VERSION 5.8 ;
BUSBITCHARS "[]" ;
DIVIDERCHAR "/" ;
UNITS
    DATABASE MICRONS 1000 ;
END UNITS

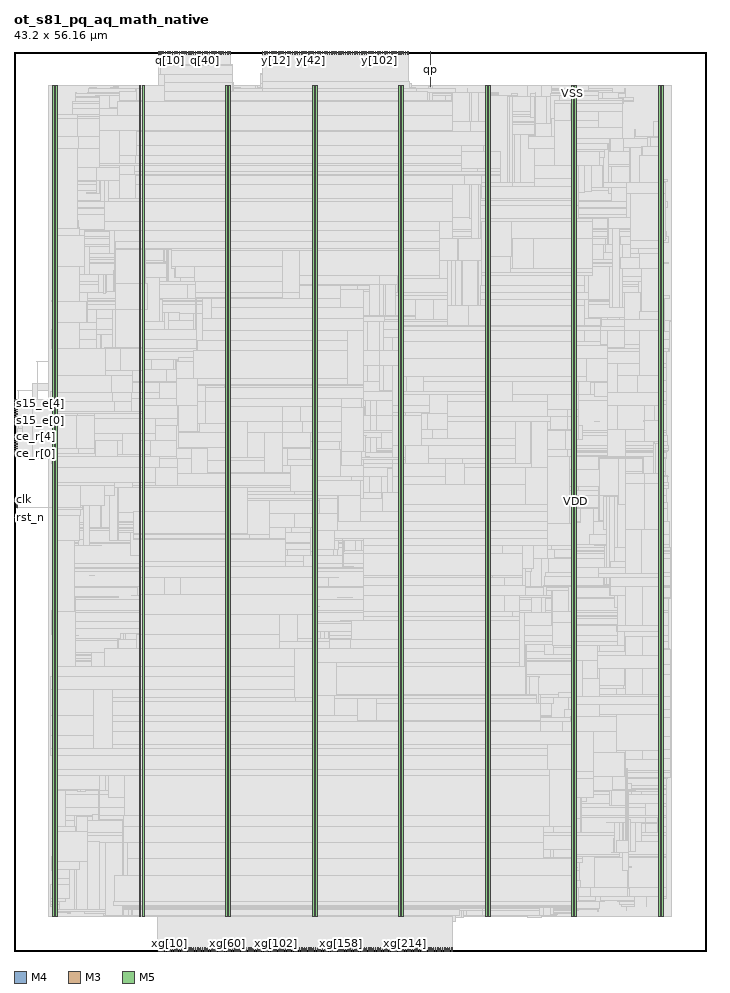
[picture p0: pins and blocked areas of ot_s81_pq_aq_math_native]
MACRO ot_s81_pq_aq_math_native
  FOREIGN ot_s81_pq_aq_math_native 0 0 ;
  CLASS BLOCK ;
  SIZE 43.2 BY 56.16 ;
  PIN ce_r[0]
    DIRECTION INPUT ;
    USE SIGNAL ;
    PORT
      LAYER M4 ;
        RECT  0 31.056 0.192 31.08 ;
    END
  END ce_r[0]
  PIN ce_r[1]
    DIRECTION INPUT ;
    USE SIGNAL ;
    PORT
      LAYER M4 ;
        RECT  0 31.2 0.192 31.224 ;
    END
  END ce_r[1]
  PIN ce_r[2]
    DIRECTION INPUT ;
    USE SIGNAL ;
    PORT
      LAYER M4 ;
        RECT  0 31.344 0.192 31.368 ;
    END
  END ce_r[2]
  PIN ce_r[3]
    DIRECTION INPUT ;
    USE SIGNAL ;
    PORT
      LAYER M4 ;
        RECT  0 31.488 0.192 31.512 ;
    END
  END ce_r[3]
  PIN ce_r[4]
    DIRECTION INPUT ;
    USE SIGNAL ;
    PORT
      LAYER M4 ;
        RECT  0 31.632 0.192 31.656 ;
    END
  END ce_r[4]
  PIN ce_r[5]
    DIRECTION INPUT ;
    USE SIGNAL ;
    PORT
      LAYER M4 ;
        RECT  0 31.776 0.192 31.8 ;
    END
  END ce_r[5]
  PIN ce_r[6]
    DIRECTION INPUT ;
    USE SIGNAL ;
    PORT
      LAYER M4 ;
        RECT  0 31.92 0.192 31.944 ;
    END
  END ce_r[6]
  PIN ce_r[7]
    DIRECTION INPUT ;
    USE SIGNAL ;
    PORT
      LAYER M4 ;
        RECT  0 32.064 0.192 32.088 ;
    END
  END ce_r[7]
  PIN ce_r[8]
    DIRECTION INPUT ;
    USE SIGNAL ;
    PORT
      LAYER M4 ;
        RECT  0 32.208 0.192 32.232 ;
    END
  END ce_r[8]
  PIN clk
    DIRECTION INPUT ;
    USE SIGNAL ;
    PORT
      LAYER M4 ;
        RECT  0 28.032 0.192 28.056 ;
    END
    PORT
      LAYER M4 ;
        RECT  0.156 28.032 0.181 28.056 ;
    END
    PORT
      LAYER M4 ;
        RECT  0.181 27.648 0.227 28.056 ;
    END
  END clk
  PIN q[0]
    DIRECTION OUTPUT ;
    USE SIGNAL ;
    PORT
      LAYER M3 ;
        RECT  9 56.016 9.018 56.16 ;
    END
  END q[0]
  PIN q[10]
    DIRECTION OUTPUT ;
    USE SIGNAL ;
    PORT
      LAYER M3 ;
        RECT  9.72 56.016 9.738 56.16 ;
    END
  END q[10]
  PIN q[11]
    DIRECTION OUTPUT ;
    USE SIGNAL ;
    PORT
      LAYER M5 ;
        RECT  9.744 55.968 9.768 56.16 ;
    END
  END q[11]
  PIN q[12]
    DIRECTION OUTPUT ;
    USE SIGNAL ;
    PORT
      LAYER M3 ;
        RECT  9.864 56.016 9.882 56.16 ;
    END
  END q[12]
  PIN q[13]
    DIRECTION OUTPUT ;
    USE SIGNAL ;
    PORT
      LAYER M5 ;
        RECT  9.888 55.968 9.912 56.16 ;
    END
  END q[13]
  PIN q[14]
    DIRECTION OUTPUT ;
    USE SIGNAL ;
    PORT
      LAYER M3 ;
        RECT  10.008 56.016 10.026 56.16 ;
    END
  END q[14]
  PIN q[15]
    DIRECTION OUTPUT ;
    USE SIGNAL ;
    PORT
      LAYER M5 ;
        RECT  10.032 55.968 10.056 56.16 ;
    END
  END q[15]
  PIN q[16]
    DIRECTION OUTPUT ;
    USE SIGNAL ;
    PORT
      LAYER M3 ;
        RECT  10.152 56.016 10.17 56.16 ;
    END
  END q[16]
  PIN q[17]
    DIRECTION OUTPUT ;
    USE SIGNAL ;
    PORT
      LAYER M5 ;
        RECT  10.176 55.968 10.2 56.16 ;
    END
  END q[17]
  PIN q[18]
    DIRECTION OUTPUT ;
    USE SIGNAL ;
    PORT
      LAYER M3 ;
        RECT  10.296 56.016 10.314 56.16 ;
    END
  END q[18]
  PIN q[19]
    DIRECTION OUTPUT ;
    USE SIGNAL ;
    PORT
      LAYER M5 ;
        RECT  10.32 55.968 10.344 56.16 ;
    END
  END q[19]
  PIN q[1]
    DIRECTION OUTPUT ;
    USE SIGNAL ;
    PORT
      LAYER M5 ;
        RECT  9.024 55.968 9.048 56.16 ;
    END
  END q[1]
  PIN q[20]
    DIRECTION OUTPUT ;
    USE SIGNAL ;
    PORT
      LAYER M3 ;
        RECT  10.44 56.016 10.458 56.16 ;
    END
  END q[20]
  PIN q[21]
    DIRECTION OUTPUT ;
    USE SIGNAL ;
    PORT
      LAYER M5 ;
        RECT  10.464 55.968 10.488 56.16 ;
    END
  END q[21]
  PIN q[22]
    DIRECTION OUTPUT ;
    USE SIGNAL ;
    PORT
      LAYER M3 ;
        RECT  10.584 56.016 10.602 56.16 ;
    END
  END q[22]
  PIN q[23]
    DIRECTION OUTPUT ;
    USE SIGNAL ;
    PORT
      LAYER M5 ;
        RECT  10.608 55.968 10.632 56.16 ;
    END
  END q[23]
  PIN q[24]
    DIRECTION OUTPUT ;
    USE SIGNAL ;
    PORT
      LAYER M3 ;
        RECT  10.728 56.016 10.746 56.16 ;
    END
  END q[24]
  PIN q[25]
    DIRECTION OUTPUT ;
    USE SIGNAL ;
    PORT
      LAYER M5 ;
        RECT  10.752 55.968 10.776 56.16 ;
    END
  END q[25]
  PIN q[26]
    DIRECTION OUTPUT ;
    USE SIGNAL ;
    PORT
      LAYER M3 ;
        RECT  10.872 56.016 10.89 56.16 ;
    END
  END q[26]
  PIN q[27]
    DIRECTION OUTPUT ;
    USE SIGNAL ;
    PORT
      LAYER M5 ;
        RECT  10.896 55.968 10.92 56.16 ;
    END
  END q[27]
  PIN q[28]
    DIRECTION OUTPUT ;
    USE SIGNAL ;
    PORT
      LAYER M3 ;
        RECT  11.016 56.016 11.034 56.16 ;
    END
  END q[28]
  PIN q[29]
    DIRECTION OUTPUT ;
    USE SIGNAL ;
    PORT
      LAYER M5 ;
        RECT  11.04 55.968 11.064 56.16 ;
    END
  END q[29]
  PIN q[2]
    DIRECTION OUTPUT ;
    USE SIGNAL ;
    PORT
      LAYER M3 ;
        RECT  9.144 56.016 9.162 56.16 ;
    END
  END q[2]
  PIN q[30]
    DIRECTION OUTPUT ;
    USE SIGNAL ;
    PORT
      LAYER M3 ;
        RECT  11.16 56.016 11.178 56.16 ;
    END
  END q[30]
  PIN q[31]
    DIRECTION OUTPUT ;
    USE SIGNAL ;
    PORT
      LAYER M5 ;
        RECT  11.184 55.968 11.208 56.16 ;
    END
  END q[31]
  PIN q[32]
    DIRECTION OUTPUT ;
    USE SIGNAL ;
    PORT
      LAYER M3 ;
        RECT  11.304 56.016 11.322 56.16 ;
    END
  END q[32]
  PIN q[33]
    DIRECTION OUTPUT ;
    USE SIGNAL ;
    PORT
      LAYER M5 ;
        RECT  11.328 55.968 11.352 56.16 ;
    END
  END q[33]
  PIN q[34]
    DIRECTION OUTPUT ;
    USE SIGNAL ;
    PORT
      LAYER M3 ;
        RECT  11.448 56.016 11.466 56.16 ;
    END
  END q[34]
  PIN q[35]
    DIRECTION OUTPUT ;
    USE SIGNAL ;
    PORT
      LAYER M5 ;
        RECT  11.472 55.968 11.496 56.16 ;
    END
  END q[35]
  PIN q[36]
    DIRECTION OUTPUT ;
    USE SIGNAL ;
    PORT
      LAYER M3 ;
        RECT  11.592 56.016 11.61 56.16 ;
    END
  END q[36]
  PIN q[37]
    DIRECTION OUTPUT ;
    USE SIGNAL ;
    PORT
      LAYER M5 ;
        RECT  11.616 55.968 11.64 56.16 ;
    END
  END q[37]
  PIN q[38]
    DIRECTION OUTPUT ;
    USE SIGNAL ;
    PORT
      LAYER M3 ;
        RECT  11.736 56.016 11.754 56.16 ;
    END
  END q[38]
  PIN q[39]
    DIRECTION OUTPUT ;
    USE SIGNAL ;
    PORT
      LAYER M5 ;
        RECT  11.76 55.968 11.784 56.16 ;
    END
  END q[39]
  PIN q[3]
    DIRECTION OUTPUT ;
    USE SIGNAL ;
    PORT
      LAYER M5 ;
        RECT  9.168 55.968 9.192 56.16 ;
    END
  END q[3]
  PIN q[40]
    DIRECTION OUTPUT ;
    USE SIGNAL ;
    PORT
      LAYER M3 ;
        RECT  11.88 56.016 11.898 56.16 ;
    END
  END q[40]
  PIN q[41]
    DIRECTION OUTPUT ;
    USE SIGNAL ;
    PORT
      LAYER M5 ;
        RECT  11.904 55.968 11.928 56.16 ;
    END
  END q[41]
  PIN q[42]
    DIRECTION OUTPUT ;
    USE SIGNAL ;
    PORT
      LAYER M3 ;
        RECT  12.024 56.016 12.042 56.16 ;
    END
  END q[42]
  PIN q[43]
    DIRECTION OUTPUT ;
    USE SIGNAL ;
    PORT
      LAYER M5 ;
        RECT  12.048 55.968 12.072 56.16 ;
    END
  END q[43]
  PIN q[44]
    DIRECTION OUTPUT ;
    USE SIGNAL ;
    PORT
      LAYER M3 ;
        RECT  12.168 56.016 12.186 56.16 ;
    END
  END q[44]
  PIN q[45]
    DIRECTION OUTPUT ;
    USE SIGNAL ;
    PORT
      LAYER M5 ;
        RECT  12.192 55.968 12.216 56.16 ;
    END
  END q[45]
  PIN q[46]
    DIRECTION OUTPUT ;
    USE SIGNAL ;
    PORT
      LAYER M3 ;
        RECT  12.312 56.016 12.33 56.16 ;
    END
  END q[46]
  PIN q[47]
    DIRECTION OUTPUT ;
    USE SIGNAL ;
    PORT
      LAYER M5 ;
        RECT  12.336 55.968 12.36 56.16 ;
    END
  END q[47]
  PIN q[48]
    DIRECTION OUTPUT ;
    USE SIGNAL ;
    PORT
      LAYER M3 ;
        RECT  12.456 56.016 12.474 56.16 ;
    END
  END q[48]
  PIN q[49]
    DIRECTION OUTPUT ;
    USE SIGNAL ;
    PORT
      LAYER M5 ;
        RECT  12.48 55.968 12.504 56.16 ;
    END
  END q[49]
  PIN q[4]
    DIRECTION OUTPUT ;
    USE SIGNAL ;
    PORT
      LAYER M3 ;
        RECT  9.288 56.016 9.306 56.16 ;
    END
  END q[4]
  PIN q[50]
    DIRECTION OUTPUT ;
    USE SIGNAL ;
    PORT
      LAYER M3 ;
        RECT  12.6 56.016 12.618 56.16 ;
    END
  END q[50]
  PIN q[51]
    DIRECTION OUTPUT ;
    USE SIGNAL ;
    PORT
      LAYER M5 ;
        RECT  12.624 55.968 12.648 56.16 ;
    END
  END q[51]
  PIN q[52]
    DIRECTION OUTPUT ;
    USE SIGNAL ;
    PORT
      LAYER M3 ;
        RECT  12.744 56.016 12.762 56.16 ;
    END
  END q[52]
  PIN q[53]
    DIRECTION OUTPUT ;
    USE SIGNAL ;
    PORT
      LAYER M5 ;
        RECT  12.768 55.968 12.792 56.16 ;
    END
  END q[53]
  PIN q[54]
    DIRECTION OUTPUT ;
    USE SIGNAL ;
    PORT
      LAYER M3 ;
        RECT  12.888 56.016 12.906 56.16 ;
    END
  END q[54]
  PIN q[55]
    DIRECTION OUTPUT ;
    USE SIGNAL ;
    PORT
      LAYER M5 ;
        RECT  12.912 55.968 12.936 56.16 ;
    END
  END q[55]
  PIN q[56]
    DIRECTION OUTPUT ;
    USE SIGNAL ;
    PORT
      LAYER M3 ;
        RECT  13.032 56.016 13.05 56.16 ;
    END
  END q[56]
  PIN q[57]
    DIRECTION OUTPUT ;
    USE SIGNAL ;
    PORT
      LAYER M5 ;
        RECT  13.056 55.968 13.08 56.16 ;
    END
  END q[57]
  PIN q[58]
    DIRECTION OUTPUT ;
    USE SIGNAL ;
    PORT
      LAYER M3 ;
        RECT  13.176 56.016 13.194 56.16 ;
    END
  END q[58]
  PIN q[59]
    DIRECTION OUTPUT ;
    USE SIGNAL ;
    PORT
      LAYER M5 ;
        RECT  13.2 55.968 13.224 56.16 ;
    END
  END q[59]
  PIN q[5]
    DIRECTION OUTPUT ;
    USE SIGNAL ;
    PORT
      LAYER M5 ;
        RECT  9.312 55.968 9.336 56.16 ;
    END
  END q[5]
  PIN q[60]
    DIRECTION OUTPUT ;
    USE SIGNAL ;
    PORT
      LAYER M3 ;
        RECT  13.32 56.016 13.338 56.16 ;
    END
  END q[60]
  PIN q[61]
    DIRECTION OUTPUT ;
    USE SIGNAL ;
    PORT
      LAYER M5 ;
        RECT  13.344 55.968 13.368 56.16 ;
    END
  END q[61]
  PIN q[62]
    DIRECTION OUTPUT ;
    USE SIGNAL ;
    PORT
      LAYER M3 ;
        RECT  13.464 56.016 13.482 56.16 ;
    END
  END q[62]
  PIN q[63]
    DIRECTION OUTPUT ;
    USE SIGNAL ;
    PORT
      LAYER M5 ;
        RECT  13.488 55.968 13.512 56.16 ;
    END
  END q[63]
  PIN q[6]
    DIRECTION OUTPUT ;
    USE SIGNAL ;
    PORT
      LAYER M3 ;
        RECT  9.432 56.016 9.45 56.16 ;
    END
  END q[6]
  PIN q[7]
    DIRECTION OUTPUT ;
    USE SIGNAL ;
    PORT
      LAYER M5 ;
        RECT  9.456 55.968 9.48 56.16 ;
    END
  END q[7]
  PIN q[8]
    DIRECTION OUTPUT ;
    USE SIGNAL ;
    PORT
      LAYER M3 ;
        RECT  9.576 56.016 9.594 56.16 ;
    END
  END q[8]
  PIN q[9]
    DIRECTION OUTPUT ;
    USE SIGNAL ;
    PORT
      LAYER M5 ;
        RECT  9.6 55.968 9.624 56.16 ;
    END
  END q[9]
  PIN qp
    DIRECTION OUTPUT ;
    USE SIGNAL ;
    PORT
      LAYER M3 ;
        RECT  25.992 56.016 26.01 56.16 ;
    END
    PORT
      LAYER M3 ;
        RECT  25.992 53.969 26.01 56.028 ;
    END
  END qp
  PIN rst_n
    DIRECTION INPUT ;
    USE SIGNAL ;
    PORT
      LAYER M4 ;
        RECT  0 27.024 0.192 27.048 ;
    END
  END rst_n
  PIN s15_e[0]
    DIRECTION INPUT ;
    USE SIGNAL ;
    PORT
      LAYER M4 ;
        RECT  0 33.072 0.192 33.096 ;
    END
  END s15_e[0]
  PIN s15_e[1]
    DIRECTION INPUT ;
    USE SIGNAL ;
    PORT
      LAYER M4 ;
        RECT  0 33.216 0.192 33.24 ;
    END
  END s15_e[1]
  PIN s15_e[2]
    DIRECTION INPUT ;
    USE SIGNAL ;
    PORT
      LAYER M4 ;
        RECT  0 33.36 0.192 33.384 ;
    END
  END s15_e[2]
  PIN s15_e[3]
    DIRECTION INPUT ;
    USE SIGNAL ;
    PORT
      LAYER M4 ;
        RECT  0 33.504 0.192 33.528 ;
    END
  END s15_e[3]
  PIN s15_e[4]
    DIRECTION INPUT ;
    USE SIGNAL ;
    PORT
      LAYER M4 ;
        RECT  0 33.648 0.192 33.672 ;
    END
  END s15_e[4]
  PIN s15_e[5]
    DIRECTION INPUT ;
    USE SIGNAL ;
    PORT
      LAYER M4 ;
        RECT  0 33.792 0.192 33.816 ;
    END
  END s15_e[5]
  PIN s15_e[6]
    DIRECTION INPUT ;
    USE SIGNAL ;
    PORT
      LAYER M4 ;
        RECT  0 33.936 0.192 33.96 ;
    END
  END s15_e[6]
  PIN s15_e[7]
    DIRECTION INPUT ;
    USE SIGNAL ;
    PORT
      LAYER M4 ;
        RECT  0 34.08 0.192 34.104 ;
    END
  END s15_e[7]
  PIN s15_e[8]
    DIRECTION INPUT ;
    USE SIGNAL ;
    PORT
      LAYER M4 ;
        RECT  0 34.224 0.192 34.248 ;
    END
  END s15_e[8]
  PIN s15_e[9]
    DIRECTION INPUT ;
    USE SIGNAL ;
    PORT
      LAYER M4 ;
        RECT  0 34.368 0.192 34.392 ;
    END
  END s15_e[9]
  PIN xg[0]
    DIRECTION INPUT ;
    USE SIGNAL ;
    PORT
      LAYER M3 ;
        RECT  9 0 9.018 0.144 ;
    END
  END xg[0]
  PIN xg[100]
    DIRECTION INPUT ;
    USE SIGNAL ;
    PORT
      LAYER M3 ;
        RECT  16.2 0 16.218 0.144 ;
    END
  END xg[100]
  PIN xg[101]
    DIRECTION INPUT ;
    USE SIGNAL ;
    PORT
      LAYER M5 ;
        RECT  16.224 0 16.248 0.192 ;
    END
  END xg[101]
  PIN xg[102]
    DIRECTION INPUT ;
    USE SIGNAL ;
    PORT
      LAYER M3 ;
        RECT  16.344 0 16.362 0.144 ;
    END
  END xg[102]
  PIN xg[103]
    DIRECTION INPUT ;
    USE SIGNAL ;
    PORT
      LAYER M5 ;
        RECT  16.368 0 16.392 0.192 ;
    END
  END xg[103]
  PIN xg[104]
    DIRECTION INPUT ;
    USE SIGNAL ;
    PORT
      LAYER M3 ;
        RECT  16.488 0 16.506 0.144 ;
    END
  END xg[104]
  PIN xg[105]
    DIRECTION INPUT ;
    USE SIGNAL ;
    PORT
      LAYER M5 ;
        RECT  16.512 0 16.536 0.192 ;
    END
  END xg[105]
  PIN xg[106]
    DIRECTION INPUT ;
    USE SIGNAL ;
    PORT
      LAYER M3 ;
        RECT  16.632 0 16.65 0.144 ;
    END
  END xg[106]
  PIN xg[107]
    DIRECTION INPUT ;
    USE SIGNAL ;
    PORT
      LAYER M5 ;
        RECT  16.656 0 16.68 0.192 ;
    END
  END xg[107]
  PIN xg[108]
    DIRECTION INPUT ;
    USE SIGNAL ;
    PORT
      LAYER M3 ;
        RECT  16.776 0 16.794 0.144 ;
    END
  END xg[108]
  PIN xg[109]
    DIRECTION INPUT ;
    USE SIGNAL ;
    PORT
      LAYER M5 ;
        RECT  16.8 0 16.824 0.192 ;
    END
  END xg[109]
  PIN xg[10]
    DIRECTION INPUT ;
    USE SIGNAL ;
    PORT
      LAYER M3 ;
        RECT  9.72 0 9.738 0.144 ;
    END
  END xg[10]
  PIN xg[110]
    DIRECTION INPUT ;
    USE SIGNAL ;
    PORT
      LAYER M3 ;
        RECT  16.92 0 16.938 0.144 ;
    END
  END xg[110]
  PIN xg[111]
    DIRECTION INPUT ;
    USE SIGNAL ;
    PORT
      LAYER M5 ;
        RECT  16.944 0 16.968 0.192 ;
    END
  END xg[111]
  PIN xg[112]
    DIRECTION INPUT ;
    USE SIGNAL ;
    PORT
      LAYER M3 ;
        RECT  17.064 0 17.082 0.144 ;
    END
  END xg[112]
  PIN xg[113]
    DIRECTION INPUT ;
    USE SIGNAL ;
    PORT
      LAYER M5 ;
        RECT  17.088 0 17.112 0.192 ;
    END
  END xg[113]
  PIN xg[114]
    DIRECTION INPUT ;
    USE SIGNAL ;
    PORT
      LAYER M3 ;
        RECT  17.208 0 17.226 0.144 ;
    END
  END xg[114]
  PIN xg[115]
    DIRECTION INPUT ;
    USE SIGNAL ;
    PORT
      LAYER M5 ;
        RECT  17.232 0 17.256 0.192 ;
    END
  END xg[115]
  PIN xg[116]
    DIRECTION INPUT ;
    USE SIGNAL ;
    PORT
      LAYER M3 ;
        RECT  17.352 0 17.37 0.144 ;
    END
  END xg[116]
  PIN xg[117]
    DIRECTION INPUT ;
    USE SIGNAL ;
    PORT
      LAYER M5 ;
        RECT  17.376 0 17.4 0.192 ;
    END
  END xg[117]
  PIN xg[118]
    DIRECTION INPUT ;
    USE SIGNAL ;
    PORT
      LAYER M3 ;
        RECT  17.496 0 17.514 0.144 ;
    END
  END xg[118]
  PIN xg[119]
    DIRECTION INPUT ;
    USE SIGNAL ;
    PORT
      LAYER M5 ;
        RECT  17.52 0 17.544 0.192 ;
    END
  END xg[119]
  PIN xg[11]
    DIRECTION INPUT ;
    USE SIGNAL ;
    PORT
      LAYER M5 ;
        RECT  9.744 0 9.768 0.192 ;
    END
  END xg[11]
  PIN xg[120]
    DIRECTION INPUT ;
    USE SIGNAL ;
    PORT
      LAYER M3 ;
        RECT  17.64 0 17.658 0.144 ;
    END
  END xg[120]
  PIN xg[121]
    DIRECTION INPUT ;
    USE SIGNAL ;
    PORT
      LAYER M5 ;
        RECT  17.664 0 17.688 0.192 ;
    END
  END xg[121]
  PIN xg[122]
    DIRECTION INPUT ;
    USE SIGNAL ;
    PORT
      LAYER M3 ;
        RECT  17.784 0 17.802 0.144 ;
    END
  END xg[122]
  PIN xg[123]
    DIRECTION INPUT ;
    USE SIGNAL ;
    PORT
      LAYER M5 ;
        RECT  17.808 0 17.832 0.192 ;
    END
  END xg[123]
  PIN xg[124]
    DIRECTION INPUT ;
    USE SIGNAL ;
    PORT
      LAYER M3 ;
        RECT  17.928 0 17.946 0.144 ;
    END
  END xg[124]
  PIN xg[125]
    DIRECTION INPUT ;
    USE SIGNAL ;
    PORT
      LAYER M5 ;
        RECT  17.952 0 17.976 0.192 ;
    END
  END xg[125]
  PIN xg[126]
    DIRECTION INPUT ;
    USE SIGNAL ;
    PORT
      LAYER M3 ;
        RECT  18.072 0 18.09 0.144 ;
    END
  END xg[126]
  PIN xg[127]
    DIRECTION INPUT ;
    USE SIGNAL ;
    PORT
      LAYER M5 ;
        RECT  18.096 0 18.12 0.192 ;
    END
  END xg[127]
  PIN xg[128]
    DIRECTION INPUT ;
    USE SIGNAL ;
    PORT
      LAYER M3 ;
        RECT  18.216 0 18.234 0.144 ;
    END
  END xg[128]
  PIN xg[129]
    DIRECTION INPUT ;
    USE SIGNAL ;
    PORT
      LAYER M5 ;
        RECT  18.24 0 18.264 0.192 ;
    END
  END xg[129]
  PIN xg[12]
    DIRECTION INPUT ;
    USE SIGNAL ;
    PORT
      LAYER M3 ;
        RECT  9.864 0 9.882 0.144 ;
    END
  END xg[12]
  PIN xg[130]
    DIRECTION INPUT ;
    USE SIGNAL ;
    PORT
      LAYER M3 ;
        RECT  18.36 0 18.378 0.144 ;
    END
  END xg[130]
  PIN xg[131]
    DIRECTION INPUT ;
    USE SIGNAL ;
    PORT
      LAYER M5 ;
        RECT  18.384 0 18.408 0.192 ;
    END
  END xg[131]
  PIN xg[132]
    DIRECTION INPUT ;
    USE SIGNAL ;
    PORT
      LAYER M3 ;
        RECT  18.504 0 18.522 0.144 ;
    END
  END xg[132]
  PIN xg[133]
    DIRECTION INPUT ;
    USE SIGNAL ;
    PORT
      LAYER M5 ;
        RECT  18.528 0 18.552 0.192 ;
    END
  END xg[133]
  PIN xg[134]
    DIRECTION INPUT ;
    USE SIGNAL ;
    PORT
      LAYER M3 ;
        RECT  18.648 0 18.666 0.144 ;
    END
  END xg[134]
  PIN xg[135]
    DIRECTION INPUT ;
    USE SIGNAL ;
    PORT
      LAYER M5 ;
        RECT  18.672 0 18.696 0.192 ;
    END
  END xg[135]
  PIN xg[136]
    DIRECTION INPUT ;
    USE SIGNAL ;
    PORT
      LAYER M3 ;
        RECT  18.792 0 18.81 0.144 ;
    END
  END xg[136]
  PIN xg[137]
    DIRECTION INPUT ;
    USE SIGNAL ;
    PORT
      LAYER M5 ;
        RECT  18.816 0 18.84 0.192 ;
    END
  END xg[137]
  PIN xg[138]
    DIRECTION INPUT ;
    USE SIGNAL ;
    PORT
      LAYER M3 ;
        RECT  18.936 0 18.954 0.144 ;
    END
  END xg[138]
  PIN xg[139]
    DIRECTION INPUT ;
    USE SIGNAL ;
    PORT
      LAYER M5 ;
        RECT  18.96 0 18.984 0.192 ;
    END
  END xg[139]
  PIN xg[13]
    DIRECTION INPUT ;
    USE SIGNAL ;
    PORT
      LAYER M5 ;
        RECT  9.888 0 9.912 0.192 ;
    END
  END xg[13]
  PIN xg[140]
    DIRECTION INPUT ;
    USE SIGNAL ;
    PORT
      LAYER M3 ;
        RECT  19.08 0 19.098 0.144 ;
    END
  END xg[140]
  PIN xg[141]
    DIRECTION INPUT ;
    USE SIGNAL ;
    PORT
      LAYER M5 ;
        RECT  19.104 0 19.128 0.192 ;
    END
  END xg[141]
  PIN xg[142]
    DIRECTION INPUT ;
    USE SIGNAL ;
    PORT
      LAYER M3 ;
        RECT  19.224 0 19.242 0.144 ;
    END
  END xg[142]
  PIN xg[143]
    DIRECTION INPUT ;
    USE SIGNAL ;
    PORT
      LAYER M5 ;
        RECT  19.248 0 19.272 0.192 ;
    END
  END xg[143]
  PIN xg[144]
    DIRECTION INPUT ;
    USE SIGNAL ;
    PORT
      LAYER M3 ;
        RECT  19.368 0 19.386 0.144 ;
    END
  END xg[144]
  PIN xg[145]
    DIRECTION INPUT ;
    USE SIGNAL ;
    PORT
      LAYER M5 ;
        RECT  19.392 0 19.416 0.192 ;
    END
  END xg[145]
  PIN xg[146]
    DIRECTION INPUT ;
    USE SIGNAL ;
    PORT
      LAYER M3 ;
        RECT  19.512 0 19.53 0.144 ;
    END
  END xg[146]
  PIN xg[147]
    DIRECTION INPUT ;
    USE SIGNAL ;
    PORT
      LAYER M5 ;
        RECT  19.536 0 19.56 0.192 ;
    END
  END xg[147]
  PIN xg[148]
    DIRECTION INPUT ;
    USE SIGNAL ;
    PORT
      LAYER M3 ;
        RECT  19.656 0 19.674 0.144 ;
    END
  END xg[148]
  PIN xg[149]
    DIRECTION INPUT ;
    USE SIGNAL ;
    PORT
      LAYER M5 ;
        RECT  19.68 0 19.704 0.192 ;
    END
  END xg[149]
  PIN xg[14]
    DIRECTION INPUT ;
    USE SIGNAL ;
    PORT
      LAYER M3 ;
        RECT  10.008 0 10.026 0.144 ;
    END
  END xg[14]
  PIN xg[150]
    DIRECTION INPUT ;
    USE SIGNAL ;
    PORT
      LAYER M3 ;
        RECT  19.8 0 19.818 0.144 ;
    END
  END xg[150]
  PIN xg[151]
    DIRECTION INPUT ;
    USE SIGNAL ;
    PORT
      LAYER M5 ;
        RECT  19.824 0 19.848 0.192 ;
    END
  END xg[151]
  PIN xg[152]
    DIRECTION INPUT ;
    USE SIGNAL ;
    PORT
      LAYER M3 ;
        RECT  19.944 0 19.962 0.144 ;
    END
  END xg[152]
  PIN xg[153]
    DIRECTION INPUT ;
    USE SIGNAL ;
    PORT
      LAYER M5 ;
        RECT  19.968 0 19.992 0.192 ;
    END
  END xg[153]
  PIN xg[154]
    DIRECTION INPUT ;
    USE SIGNAL ;
    PORT
      LAYER M3 ;
        RECT  20.088 0 20.106 0.144 ;
    END
  END xg[154]
  PIN xg[155]
    DIRECTION INPUT ;
    USE SIGNAL ;
    PORT
      LAYER M5 ;
        RECT  20.112 0 20.136 0.192 ;
    END
  END xg[155]
  PIN xg[156]
    DIRECTION INPUT ;
    USE SIGNAL ;
    PORT
      LAYER M3 ;
        RECT  20.232 0 20.25 0.144 ;
    END
  END xg[156]
  PIN xg[157]
    DIRECTION INPUT ;
    USE SIGNAL ;
    PORT
      LAYER M5 ;
        RECT  20.256 0 20.28 0.192 ;
    END
  END xg[157]
  PIN xg[158]
    DIRECTION INPUT ;
    USE SIGNAL ;
    PORT
      LAYER M3 ;
        RECT  20.376 0 20.394 0.144 ;
    END
  END xg[158]
  PIN xg[159]
    DIRECTION INPUT ;
    USE SIGNAL ;
    PORT
      LAYER M5 ;
        RECT  20.4 0 20.424 0.192 ;
    END
  END xg[159]
  PIN xg[15]
    DIRECTION INPUT ;
    USE SIGNAL ;
    PORT
      LAYER M5 ;
        RECT  10.032 0 10.056 0.192 ;
    END
  END xg[15]
  PIN xg[160]
    DIRECTION INPUT ;
    USE SIGNAL ;
    PORT
      LAYER M3 ;
        RECT  20.52 0 20.538 0.144 ;
    END
  END xg[160]
  PIN xg[161]
    DIRECTION INPUT ;
    USE SIGNAL ;
    PORT
      LAYER M5 ;
        RECT  20.544 0 20.568 0.192 ;
    END
  END xg[161]
  PIN xg[162]
    DIRECTION INPUT ;
    USE SIGNAL ;
    PORT
      LAYER M3 ;
        RECT  20.664 0 20.682 0.144 ;
    END
  END xg[162]
  PIN xg[163]
    DIRECTION INPUT ;
    USE SIGNAL ;
    PORT
      LAYER M5 ;
        RECT  20.688 0 20.712 0.192 ;
    END
  END xg[163]
  PIN xg[164]
    DIRECTION INPUT ;
    USE SIGNAL ;
    PORT
      LAYER M3 ;
        RECT  20.808 0 20.826 0.144 ;
    END
  END xg[164]
  PIN xg[165]
    DIRECTION INPUT ;
    USE SIGNAL ;
    PORT
      LAYER M5 ;
        RECT  20.832 0 20.856 0.192 ;
    END
  END xg[165]
  PIN xg[166]
    DIRECTION INPUT ;
    USE SIGNAL ;
    PORT
      LAYER M3 ;
        RECT  20.952 0 20.97 0.144 ;
    END
  END xg[166]
  PIN xg[167]
    DIRECTION INPUT ;
    USE SIGNAL ;
    PORT
      LAYER M5 ;
        RECT  20.976 0 21 0.192 ;
    END
  END xg[167]
  PIN xg[168]
    DIRECTION INPUT ;
    USE SIGNAL ;
    PORT
      LAYER M3 ;
        RECT  21.096 0 21.114 0.144 ;
    END
  END xg[168]
  PIN xg[169]
    DIRECTION INPUT ;
    USE SIGNAL ;
    PORT
      LAYER M5 ;
        RECT  21.12 0 21.144 0.192 ;
    END
  END xg[169]
  PIN xg[16]
    DIRECTION INPUT ;
    USE SIGNAL ;
    PORT
      LAYER M3 ;
        RECT  10.152 0 10.17 0.144 ;
    END
  END xg[16]
  PIN xg[170]
    DIRECTION INPUT ;
    USE SIGNAL ;
    PORT
      LAYER M3 ;
        RECT  21.24 0 21.258 0.144 ;
    END
  END xg[170]
  PIN xg[171]
    DIRECTION INPUT ;
    USE SIGNAL ;
    PORT
      LAYER M5 ;
        RECT  21.264 0 21.288 0.192 ;
    END
  END xg[171]
  PIN xg[172]
    DIRECTION INPUT ;
    USE SIGNAL ;
    PORT
      LAYER M3 ;
        RECT  21.384 0 21.402 0.144 ;
    END
  END xg[172]
  PIN xg[173]
    DIRECTION INPUT ;
    USE SIGNAL ;
    PORT
      LAYER M5 ;
        RECT  21.408 0 21.432 0.192 ;
    END
  END xg[173]
  PIN xg[174]
    DIRECTION INPUT ;
    USE SIGNAL ;
    PORT
      LAYER M3 ;
        RECT  21.528 0 21.546 0.144 ;
    END
  END xg[174]
  PIN xg[175]
    DIRECTION INPUT ;
    USE SIGNAL ;
    PORT
      LAYER M5 ;
        RECT  21.552 0 21.576 0.192 ;
    END
  END xg[175]
  PIN xg[176]
    DIRECTION INPUT ;
    USE SIGNAL ;
    PORT
      LAYER M3 ;
        RECT  21.672 0 21.69 0.144 ;
    END
  END xg[176]
  PIN xg[177]
    DIRECTION INPUT ;
    USE SIGNAL ;
    PORT
      LAYER M5 ;
        RECT  21.696 0 21.72 0.192 ;
    END
  END xg[177]
  PIN xg[178]
    DIRECTION INPUT ;
    USE SIGNAL ;
    PORT
      LAYER M3 ;
        RECT  21.816 0 21.834 0.144 ;
    END
  END xg[178]
  PIN xg[179]
    DIRECTION INPUT ;
    USE SIGNAL ;
    PORT
      LAYER M5 ;
        RECT  21.84 0 21.864 0.192 ;
    END
  END xg[179]
  PIN xg[17]
    DIRECTION INPUT ;
    USE SIGNAL ;
    PORT
      LAYER M5 ;
        RECT  10.176 0 10.2 0.192 ;
    END
  END xg[17]
  PIN xg[180]
    DIRECTION INPUT ;
    USE SIGNAL ;
    PORT
      LAYER M3 ;
        RECT  21.96 0 21.978 0.144 ;
    END
  END xg[180]
  PIN xg[181]
    DIRECTION INPUT ;
    USE SIGNAL ;
    PORT
      LAYER M5 ;
        RECT  21.984 0 22.008 0.192 ;
    END
  END xg[181]
  PIN xg[182]
    DIRECTION INPUT ;
    USE SIGNAL ;
    PORT
      LAYER M3 ;
        RECT  22.104 0 22.122 0.144 ;
    END
  END xg[182]
  PIN xg[183]
    DIRECTION INPUT ;
    USE SIGNAL ;
    PORT
      LAYER M5 ;
        RECT  22.128 0 22.152 0.192 ;
    END
  END xg[183]
  PIN xg[184]
    DIRECTION INPUT ;
    USE SIGNAL ;
    PORT
      LAYER M3 ;
        RECT  22.248 0 22.266 0.144 ;
    END
  END xg[184]
  PIN xg[185]
    DIRECTION INPUT ;
    USE SIGNAL ;
    PORT
      LAYER M5 ;
        RECT  22.272 0 22.296 0.192 ;
    END
  END xg[185]
  PIN xg[186]
    DIRECTION INPUT ;
    USE SIGNAL ;
    PORT
      LAYER M3 ;
        RECT  22.392 0 22.41 0.144 ;
    END
  END xg[186]
  PIN xg[187]
    DIRECTION INPUT ;
    USE SIGNAL ;
    PORT
      LAYER M5 ;
        RECT  22.416 0 22.44 0.192 ;
    END
  END xg[187]
  PIN xg[188]
    DIRECTION INPUT ;
    USE SIGNAL ;
    PORT
      LAYER M3 ;
        RECT  22.536 0 22.554 0.144 ;
    END
  END xg[188]
  PIN xg[189]
    DIRECTION INPUT ;
    USE SIGNAL ;
    PORT
      LAYER M5 ;
        RECT  22.56 0 22.584 0.192 ;
    END
  END xg[189]
  PIN xg[18]
    DIRECTION INPUT ;
    USE SIGNAL ;
    PORT
      LAYER M3 ;
        RECT  10.296 0 10.314 0.144 ;
    END
  END xg[18]
  PIN xg[190]
    DIRECTION INPUT ;
    USE SIGNAL ;
    PORT
      LAYER M3 ;
        RECT  22.68 0 22.698 0.144 ;
    END
  END xg[190]
  PIN xg[191]
    DIRECTION INPUT ;
    USE SIGNAL ;
    PORT
      LAYER M5 ;
        RECT  22.704 0 22.728 0.192 ;
    END
  END xg[191]
  PIN xg[192]
    DIRECTION INPUT ;
    USE SIGNAL ;
    PORT
      LAYER M3 ;
        RECT  22.824 0 22.842 0.144 ;
    END
  END xg[192]
  PIN xg[193]
    DIRECTION INPUT ;
    USE SIGNAL ;
    PORT
      LAYER M5 ;
        RECT  22.848 0 22.872 0.192 ;
    END
  END xg[193]
  PIN xg[194]
    DIRECTION INPUT ;
    USE SIGNAL ;
    PORT
      LAYER M3 ;
        RECT  22.968 0 22.986 0.144 ;
    END
  END xg[194]
  PIN xg[195]
    DIRECTION INPUT ;
    USE SIGNAL ;
    PORT
      LAYER M5 ;
        RECT  22.992 0 23.016 0.192 ;
    END
  END xg[195]
  PIN xg[196]
    DIRECTION INPUT ;
    USE SIGNAL ;
    PORT
      LAYER M3 ;
        RECT  23.112 0 23.13 0.144 ;
    END
  END xg[196]
  PIN xg[197]
    DIRECTION INPUT ;
    USE SIGNAL ;
    PORT
      LAYER M5 ;
        RECT  23.136 0 23.16 0.192 ;
    END
  END xg[197]
  PIN xg[198]
    DIRECTION INPUT ;
    USE SIGNAL ;
    PORT
      LAYER M3 ;
        RECT  23.256 0 23.274 0.144 ;
    END
  END xg[198]
  PIN xg[199]
    DIRECTION INPUT ;
    USE SIGNAL ;
    PORT
      LAYER M5 ;
        RECT  23.28 0 23.304 0.192 ;
    END
  END xg[199]
  PIN xg[19]
    DIRECTION INPUT ;
    USE SIGNAL ;
    PORT
      LAYER M5 ;
        RECT  10.32 0 10.344 0.192 ;
    END
  END xg[19]
  PIN xg[1]
    DIRECTION INPUT ;
    USE SIGNAL ;
    PORT
      LAYER M5 ;
        RECT  9.024 0 9.048 0.192 ;
    END
  END xg[1]
  PIN xg[200]
    DIRECTION INPUT ;
    USE SIGNAL ;
    PORT
      LAYER M3 ;
        RECT  23.4 0 23.418 0.144 ;
    END
  END xg[200]
  PIN xg[201]
    DIRECTION INPUT ;
    USE SIGNAL ;
    PORT
      LAYER M5 ;
        RECT  23.424 0 23.448 0.192 ;
    END
  END xg[201]
  PIN xg[202]
    DIRECTION INPUT ;
    USE SIGNAL ;
    PORT
      LAYER M3 ;
        RECT  23.544 0 23.562 0.144 ;
    END
  END xg[202]
  PIN xg[203]
    DIRECTION INPUT ;
    USE SIGNAL ;
    PORT
      LAYER M5 ;
        RECT  23.568 0 23.592 0.192 ;
    END
  END xg[203]
  PIN xg[204]
    DIRECTION INPUT ;
    USE SIGNAL ;
    PORT
      LAYER M3 ;
        RECT  23.688 0 23.706 0.144 ;
    END
  END xg[204]
  PIN xg[205]
    DIRECTION INPUT ;
    USE SIGNAL ;
    PORT
      LAYER M5 ;
        RECT  23.712 0 23.736 0.192 ;
    END
  END xg[205]
  PIN xg[206]
    DIRECTION INPUT ;
    USE SIGNAL ;
    PORT
      LAYER M3 ;
        RECT  23.832 0 23.85 0.144 ;
    END
  END xg[206]
  PIN xg[207]
    DIRECTION INPUT ;
    USE SIGNAL ;
    PORT
      LAYER M5 ;
        RECT  23.856 0 23.88 0.192 ;
    END
  END xg[207]
  PIN xg[208]
    DIRECTION INPUT ;
    USE SIGNAL ;
    PORT
      LAYER M3 ;
        RECT  23.976 0 23.994 0.144 ;
    END
  END xg[208]
  PIN xg[209]
    DIRECTION INPUT ;
    USE SIGNAL ;
    PORT
      LAYER M5 ;
        RECT  24 0 24.024 0.192 ;
    END
  END xg[209]
  PIN xg[20]
    DIRECTION INPUT ;
    USE SIGNAL ;
    PORT
      LAYER M3 ;
        RECT  10.44 0 10.458 0.144 ;
    END
  END xg[20]
  PIN xg[210]
    DIRECTION INPUT ;
    USE SIGNAL ;
    PORT
      LAYER M3 ;
        RECT  24.12 0 24.138 0.144 ;
    END
  END xg[210]
  PIN xg[211]
    DIRECTION INPUT ;
    USE SIGNAL ;
    PORT
      LAYER M5 ;
        RECT  24.144 0 24.168 0.192 ;
    END
  END xg[211]
  PIN xg[212]
    DIRECTION INPUT ;
    USE SIGNAL ;
    PORT
      LAYER M3 ;
        RECT  24.264 0 24.282 0.144 ;
    END
  END xg[212]
  PIN xg[213]
    DIRECTION INPUT ;
    USE SIGNAL ;
    PORT
      LAYER M5 ;
        RECT  24.288 0 24.312 0.192 ;
    END
  END xg[213]
  PIN xg[214]
    DIRECTION INPUT ;
    USE SIGNAL ;
    PORT
      LAYER M3 ;
        RECT  24.408 0 24.426 0.144 ;
    END
  END xg[214]
  PIN xg[215]
    DIRECTION INPUT ;
    USE SIGNAL ;
    PORT
      LAYER M5 ;
        RECT  24.432 0 24.456 0.192 ;
    END
  END xg[215]
  PIN xg[216]
    DIRECTION INPUT ;
    USE SIGNAL ;
    PORT
      LAYER M3 ;
        RECT  24.552 0 24.57 0.144 ;
    END
  END xg[216]
  PIN xg[217]
    DIRECTION INPUT ;
    USE SIGNAL ;
    PORT
      LAYER M5 ;
        RECT  24.576 0 24.6 0.192 ;
    END
  END xg[217]
  PIN xg[218]
    DIRECTION INPUT ;
    USE SIGNAL ;
    PORT
      LAYER M3 ;
        RECT  24.696 0 24.714 0.144 ;
    END
  END xg[218]
  PIN xg[219]
    DIRECTION INPUT ;
    USE SIGNAL ;
    PORT
      LAYER M5 ;
        RECT  24.72 0 24.744 0.192 ;
    END
  END xg[219]
  PIN xg[21]
    DIRECTION INPUT ;
    USE SIGNAL ;
    PORT
      LAYER M5 ;
        RECT  10.464 0 10.488 0.192 ;
    END
  END xg[21]
  PIN xg[220]
    DIRECTION INPUT ;
    USE SIGNAL ;
    PORT
      LAYER M3 ;
        RECT  24.84 0 24.858 0.144 ;
    END
  END xg[220]
  PIN xg[221]
    DIRECTION INPUT ;
    USE SIGNAL ;
    PORT
      LAYER M5 ;
        RECT  24.864 0 24.888 0.192 ;
    END
  END xg[221]
  PIN xg[222]
    DIRECTION INPUT ;
    USE SIGNAL ;
    PORT
      LAYER M3 ;
        RECT  24.984 0 25.002 0.144 ;
    END
  END xg[222]
  PIN xg[223]
    DIRECTION INPUT ;
    USE SIGNAL ;
    PORT
      LAYER M5 ;
        RECT  25.008 0 25.032 0.192 ;
    END
  END xg[223]
  PIN xg[224]
    DIRECTION INPUT ;
    USE SIGNAL ;
    PORT
      LAYER M3 ;
        RECT  25.128 0 25.146 0.144 ;
    END
  END xg[224]
  PIN xg[225]
    DIRECTION INPUT ;
    USE SIGNAL ;
    PORT
      LAYER M5 ;
        RECT  25.152 0 25.176 0.192 ;
    END
  END xg[225]
  PIN xg[226]
    DIRECTION INPUT ;
    USE SIGNAL ;
    PORT
      LAYER M3 ;
        RECT  25.272 0 25.29 0.144 ;
    END
  END xg[226]
  PIN xg[227]
    DIRECTION INPUT ;
    USE SIGNAL ;
    PORT
      LAYER M5 ;
        RECT  25.296 0 25.32 0.192 ;
    END
  END xg[227]
  PIN xg[228]
    DIRECTION INPUT ;
    USE SIGNAL ;
    PORT
      LAYER M3 ;
        RECT  25.416 0 25.434 0.144 ;
    END
  END xg[228]
  PIN xg[229]
    DIRECTION INPUT ;
    USE SIGNAL ;
    PORT
      LAYER M5 ;
        RECT  25.44 0 25.464 0.192 ;
    END
  END xg[229]
  PIN xg[22]
    DIRECTION INPUT ;
    USE SIGNAL ;
    PORT
      LAYER M3 ;
        RECT  10.584 0 10.602 0.144 ;
    END
  END xg[22]
  PIN xg[230]
    DIRECTION INPUT ;
    USE SIGNAL ;
    PORT
      LAYER M3 ;
        RECT  25.56 0 25.578 0.144 ;
    END
  END xg[230]
  PIN xg[231]
    DIRECTION INPUT ;
    USE SIGNAL ;
    PORT
      LAYER M5 ;
        RECT  25.584 0 25.608 0.192 ;
    END
  END xg[231]
  PIN xg[232]
    DIRECTION INPUT ;
    USE SIGNAL ;
    PORT
      LAYER M3 ;
        RECT  25.704 0 25.722 0.144 ;
    END
  END xg[232]
  PIN xg[233]
    DIRECTION INPUT ;
    USE SIGNAL ;
    PORT
      LAYER M5 ;
        RECT  25.728 0 25.752 0.192 ;
    END
  END xg[233]
  PIN xg[234]
    DIRECTION INPUT ;
    USE SIGNAL ;
    PORT
      LAYER M3 ;
        RECT  25.848 0 25.866 0.144 ;
    END
  END xg[234]
  PIN xg[235]
    DIRECTION INPUT ;
    USE SIGNAL ;
    PORT
      LAYER M5 ;
        RECT  25.872 0 25.896 0.192 ;
    END
  END xg[235]
  PIN xg[236]
    DIRECTION INPUT ;
    USE SIGNAL ;
    PORT
      LAYER M3 ;
        RECT  25.992 0 26.01 0.144 ;
    END
  END xg[236]
  PIN xg[237]
    DIRECTION INPUT ;
    USE SIGNAL ;
    PORT
      LAYER M5 ;
        RECT  26.016 0 26.04 0.192 ;
    END
  END xg[237]
  PIN xg[238]
    DIRECTION INPUT ;
    USE SIGNAL ;
    PORT
      LAYER M3 ;
        RECT  26.136 0 26.154 0.144 ;
    END
  END xg[238]
  PIN xg[239]
    DIRECTION INPUT ;
    USE SIGNAL ;
    PORT
      LAYER M5 ;
        RECT  26.16 0 26.184 0.192 ;
    END
  END xg[239]
  PIN xg[23]
    DIRECTION INPUT ;
    USE SIGNAL ;
    PORT
      LAYER M5 ;
        RECT  10.608 0 10.632 0.192 ;
    END
  END xg[23]
  PIN xg[240]
    DIRECTION INPUT ;
    USE SIGNAL ;
    PORT
      LAYER M3 ;
        RECT  26.28 0 26.298 0.144 ;
    END
  END xg[240]
  PIN xg[241]
    DIRECTION INPUT ;
    USE SIGNAL ;
    PORT
      LAYER M5 ;
        RECT  26.304 0 26.328 0.192 ;
    END
  END xg[241]
  PIN xg[242]
    DIRECTION INPUT ;
    USE SIGNAL ;
    PORT
      LAYER M3 ;
        RECT  26.424 0 26.442 0.144 ;
    END
  END xg[242]
  PIN xg[243]
    DIRECTION INPUT ;
    USE SIGNAL ;
    PORT
      LAYER M5 ;
        RECT  26.448 0 26.472 0.192 ;
    END
  END xg[243]
  PIN xg[244]
    DIRECTION INPUT ;
    USE SIGNAL ;
    PORT
      LAYER M3 ;
        RECT  26.568 0 26.586 0.144 ;
    END
  END xg[244]
  PIN xg[245]
    DIRECTION INPUT ;
    USE SIGNAL ;
    PORT
      LAYER M5 ;
        RECT  26.592 0 26.616 0.192 ;
    END
  END xg[245]
  PIN xg[246]
    DIRECTION INPUT ;
    USE SIGNAL ;
    PORT
      LAYER M3 ;
        RECT  26.712 0 26.73 0.144 ;
    END
  END xg[246]
  PIN xg[247]
    DIRECTION INPUT ;
    USE SIGNAL ;
    PORT
      LAYER M5 ;
        RECT  26.736 0 26.76 0.192 ;
    END
  END xg[247]
  PIN xg[248]
    DIRECTION INPUT ;
    USE SIGNAL ;
    PORT
      LAYER M3 ;
        RECT  26.856 0 26.874 0.144 ;
    END
  END xg[248]
  PIN xg[249]
    DIRECTION INPUT ;
    USE SIGNAL ;
    PORT
      LAYER M5 ;
        RECT  26.88 0 26.904 0.192 ;
    END
  END xg[249]
  PIN xg[24]
    DIRECTION INPUT ;
    USE SIGNAL ;
    PORT
      LAYER M3 ;
        RECT  10.728 0 10.746 0.144 ;
    END
  END xg[24]
  PIN xg[250]
    DIRECTION INPUT ;
    USE SIGNAL ;
    PORT
      LAYER M3 ;
        RECT  27 0 27.018 0.144 ;
    END
  END xg[250]
  PIN xg[251]
    DIRECTION INPUT ;
    USE SIGNAL ;
    PORT
      LAYER M5 ;
        RECT  27.024 0 27.048 0.192 ;
    END
  END xg[251]
  PIN xg[252]
    DIRECTION INPUT ;
    USE SIGNAL ;
    PORT
      LAYER M3 ;
        RECT  27.144 0 27.162 0.144 ;
    END
  END xg[252]
  PIN xg[253]
    DIRECTION INPUT ;
    USE SIGNAL ;
    PORT
      LAYER M5 ;
        RECT  27.168 0 27.192 0.192 ;
    END
  END xg[253]
  PIN xg[254]
    DIRECTION INPUT ;
    USE SIGNAL ;
    PORT
      LAYER M3 ;
        RECT  27.288 0 27.306 0.144 ;
    END
  END xg[254]
  PIN xg[255]
    DIRECTION INPUT ;
    USE SIGNAL ;
    PORT
      LAYER M5 ;
        RECT  27.312 0 27.336 0.192 ;
    END
  END xg[255]
  PIN xg[25]
    DIRECTION INPUT ;
    USE SIGNAL ;
    PORT
      LAYER M5 ;
        RECT  10.752 0 10.776 0.192 ;
    END
  END xg[25]
  PIN xg[26]
    DIRECTION INPUT ;
    USE SIGNAL ;
    PORT
      LAYER M3 ;
        RECT  10.872 0 10.89 0.144 ;
    END
  END xg[26]
  PIN xg[27]
    DIRECTION INPUT ;
    USE SIGNAL ;
    PORT
      LAYER M5 ;
        RECT  10.896 0 10.92 0.192 ;
    END
  END xg[27]
  PIN xg[28]
    DIRECTION INPUT ;
    USE SIGNAL ;
    PORT
      LAYER M3 ;
        RECT  11.016 0 11.034 0.144 ;
    END
  END xg[28]
  PIN xg[29]
    DIRECTION INPUT ;
    USE SIGNAL ;
    PORT
      LAYER M5 ;
        RECT  11.04 0 11.064 0.192 ;
    END
  END xg[29]
  PIN xg[2]
    DIRECTION INPUT ;
    USE SIGNAL ;
    PORT
      LAYER M3 ;
        RECT  9.144 0 9.162 0.144 ;
    END
  END xg[2]
  PIN xg[30]
    DIRECTION INPUT ;
    USE SIGNAL ;
    PORT
      LAYER M3 ;
        RECT  11.16 0 11.178 0.144 ;
    END
  END xg[30]
  PIN xg[31]
    DIRECTION INPUT ;
    USE SIGNAL ;
    PORT
      LAYER M5 ;
        RECT  11.184 0 11.208 0.192 ;
    END
  END xg[31]
  PIN xg[32]
    DIRECTION INPUT ;
    USE SIGNAL ;
    PORT
      LAYER M3 ;
        RECT  11.304 0 11.322 0.144 ;
    END
  END xg[32]
  PIN xg[33]
    DIRECTION INPUT ;
    USE SIGNAL ;
    PORT
      LAYER M5 ;
        RECT  11.328 0 11.352 0.192 ;
    END
  END xg[33]
  PIN xg[34]
    DIRECTION INPUT ;
    USE SIGNAL ;
    PORT
      LAYER M3 ;
        RECT  11.448 0 11.466 0.144 ;
    END
  END xg[34]
  PIN xg[35]
    DIRECTION INPUT ;
    USE SIGNAL ;
    PORT
      LAYER M5 ;
        RECT  11.472 0 11.496 0.192 ;
    END
  END xg[35]
  PIN xg[36]
    DIRECTION INPUT ;
    USE SIGNAL ;
    PORT
      LAYER M3 ;
        RECT  11.592 0 11.61 0.144 ;
    END
  END xg[36]
  PIN xg[37]
    DIRECTION INPUT ;
    USE SIGNAL ;
    PORT
      LAYER M5 ;
        RECT  11.616 0 11.64 0.192 ;
    END
  END xg[37]
  PIN xg[38]
    DIRECTION INPUT ;
    USE SIGNAL ;
    PORT
      LAYER M3 ;
        RECT  11.736 0 11.754 0.144 ;
    END
  END xg[38]
  PIN xg[39]
    DIRECTION INPUT ;
    USE SIGNAL ;
    PORT
      LAYER M5 ;
        RECT  11.76 0 11.784 0.192 ;
    END
  END xg[39]
  PIN xg[3]
    DIRECTION INPUT ;
    USE SIGNAL ;
    PORT
      LAYER M5 ;
        RECT  9.168 0 9.192 0.192 ;
    END
  END xg[3]
  PIN xg[40]
    DIRECTION INPUT ;
    USE SIGNAL ;
    PORT
      LAYER M3 ;
        RECT  11.88 0 11.898 0.144 ;
    END
  END xg[40]
  PIN xg[41]
    DIRECTION INPUT ;
    USE SIGNAL ;
    PORT
      LAYER M5 ;
        RECT  11.904 0 11.928 0.192 ;
    END
  END xg[41]
  PIN xg[42]
    DIRECTION INPUT ;
    USE SIGNAL ;
    PORT
      LAYER M3 ;
        RECT  12.024 0 12.042 0.144 ;
    END
  END xg[42]
  PIN xg[43]
    DIRECTION INPUT ;
    USE SIGNAL ;
    PORT
      LAYER M5 ;
        RECT  12.048 0 12.072 0.192 ;
    END
  END xg[43]
  PIN xg[44]
    DIRECTION INPUT ;
    USE SIGNAL ;
    PORT
      LAYER M3 ;
        RECT  12.168 0 12.186 0.144 ;
    END
  END xg[44]
  PIN xg[45]
    DIRECTION INPUT ;
    USE SIGNAL ;
    PORT
      LAYER M5 ;
        RECT  12.192 0 12.216 0.192 ;
    END
  END xg[45]
  PIN xg[46]
    DIRECTION INPUT ;
    USE SIGNAL ;
    PORT
      LAYER M3 ;
        RECT  12.312 0 12.33 0.144 ;
    END
  END xg[46]
  PIN xg[47]
    DIRECTION INPUT ;
    USE SIGNAL ;
    PORT
      LAYER M5 ;
        RECT  12.336 0 12.36 0.192 ;
    END
  END xg[47]
  PIN xg[48]
    DIRECTION INPUT ;
    USE SIGNAL ;
    PORT
      LAYER M3 ;
        RECT  12.456 0 12.474 0.144 ;
    END
  END xg[48]
  PIN xg[49]
    DIRECTION INPUT ;
    USE SIGNAL ;
    PORT
      LAYER M5 ;
        RECT  12.48 0 12.504 0.192 ;
    END
  END xg[49]
  PIN xg[4]
    DIRECTION INPUT ;
    USE SIGNAL ;
    PORT
      LAYER M3 ;
        RECT  9.288 0 9.306 0.144 ;
    END
  END xg[4]
  PIN xg[50]
    DIRECTION INPUT ;
    USE SIGNAL ;
    PORT
      LAYER M3 ;
        RECT  12.6 0 12.618 0.144 ;
    END
  END xg[50]
  PIN xg[51]
    DIRECTION INPUT ;
    USE SIGNAL ;
    PORT
      LAYER M5 ;
        RECT  12.624 0 12.648 0.192 ;
    END
  END xg[51]
  PIN xg[52]
    DIRECTION INPUT ;
    USE SIGNAL ;
    PORT
      LAYER M3 ;
        RECT  12.744 0 12.762 0.144 ;
    END
  END xg[52]
  PIN xg[53]
    DIRECTION INPUT ;
    USE SIGNAL ;
    PORT
      LAYER M5 ;
        RECT  12.768 0 12.792 0.192 ;
    END
  END xg[53]
  PIN xg[54]
    DIRECTION INPUT ;
    USE SIGNAL ;
    PORT
      LAYER M3 ;
        RECT  12.888 0 12.906 0.144 ;
    END
  END xg[54]
  PIN xg[55]
    DIRECTION INPUT ;
    USE SIGNAL ;
    PORT
      LAYER M5 ;
        RECT  12.912 0 12.936 0.192 ;
    END
  END xg[55]
  PIN xg[56]
    DIRECTION INPUT ;
    USE SIGNAL ;
    PORT
      LAYER M3 ;
        RECT  13.032 0 13.05 0.144 ;
    END
  END xg[56]
  PIN xg[57]
    DIRECTION INPUT ;
    USE SIGNAL ;
    PORT
      LAYER M5 ;
        RECT  13.056 0 13.08 0.192 ;
    END
  END xg[57]
  PIN xg[58]
    DIRECTION INPUT ;
    USE SIGNAL ;
    PORT
      LAYER M3 ;
        RECT  13.176 0 13.194 0.144 ;
    END
  END xg[58]
  PIN xg[59]
    DIRECTION INPUT ;
    USE SIGNAL ;
    PORT
      LAYER M5 ;
        RECT  13.2 0 13.224 0.192 ;
    END
  END xg[59]
  PIN xg[5]
    DIRECTION INPUT ;
    USE SIGNAL ;
    PORT
      LAYER M5 ;
        RECT  9.312 0 9.336 0.192 ;
    END
  END xg[5]
  PIN xg[60]
    DIRECTION INPUT ;
    USE SIGNAL ;
    PORT
      LAYER M3 ;
        RECT  13.32 0 13.338 0.144 ;
    END
  END xg[60]
  PIN xg[61]
    DIRECTION INPUT ;
    USE SIGNAL ;
    PORT
      LAYER M5 ;
        RECT  13.344 0 13.368 0.192 ;
    END
  END xg[61]
  PIN xg[62]
    DIRECTION INPUT ;
    USE SIGNAL ;
    PORT
      LAYER M3 ;
        RECT  13.464 0 13.482 0.144 ;
    END
  END xg[62]
  PIN xg[63]
    DIRECTION INPUT ;
    USE SIGNAL ;
    PORT
      LAYER M5 ;
        RECT  13.488 0 13.512 0.192 ;
    END
  END xg[63]
  PIN xg[64]
    DIRECTION INPUT ;
    USE SIGNAL ;
    PORT
      LAYER M3 ;
        RECT  13.608 0 13.626 0.144 ;
    END
  END xg[64]
  PIN xg[65]
    DIRECTION INPUT ;
    USE SIGNAL ;
    PORT
      LAYER M5 ;
        RECT  13.632 0 13.656 0.192 ;
    END
  END xg[65]
  PIN xg[66]
    DIRECTION INPUT ;
    USE SIGNAL ;
    PORT
      LAYER M3 ;
        RECT  13.752 0 13.77 0.144 ;
    END
  END xg[66]
  PIN xg[67]
    DIRECTION INPUT ;
    USE SIGNAL ;
    PORT
      LAYER M5 ;
        RECT  13.776 0 13.8 0.192 ;
    END
  END xg[67]
  PIN xg[68]
    DIRECTION INPUT ;
    USE SIGNAL ;
    PORT
      LAYER M3 ;
        RECT  13.896 0 13.914 0.144 ;
    END
  END xg[68]
  PIN xg[69]
    DIRECTION INPUT ;
    USE SIGNAL ;
    PORT
      LAYER M5 ;
        RECT  13.92 0 13.944 0.192 ;
    END
  END xg[69]
  PIN xg[6]
    DIRECTION INPUT ;
    USE SIGNAL ;
    PORT
      LAYER M3 ;
        RECT  9.432 0 9.45 0.144 ;
    END
  END xg[6]
  PIN xg[70]
    DIRECTION INPUT ;
    USE SIGNAL ;
    PORT
      LAYER M3 ;
        RECT  14.04 0 14.058 0.144 ;
    END
  END xg[70]
  PIN xg[71]
    DIRECTION INPUT ;
    USE SIGNAL ;
    PORT
      LAYER M5 ;
        RECT  14.064 0 14.088 0.192 ;
    END
  END xg[71]
  PIN xg[72]
    DIRECTION INPUT ;
    USE SIGNAL ;
    PORT
      LAYER M3 ;
        RECT  14.184 0 14.202 0.144 ;
    END
  END xg[72]
  PIN xg[73]
    DIRECTION INPUT ;
    USE SIGNAL ;
    PORT
      LAYER M5 ;
        RECT  14.208 0 14.232 0.192 ;
    END
  END xg[73]
  PIN xg[74]
    DIRECTION INPUT ;
    USE SIGNAL ;
    PORT
      LAYER M3 ;
        RECT  14.328 0 14.346 0.144 ;
    END
  END xg[74]
  PIN xg[75]
    DIRECTION INPUT ;
    USE SIGNAL ;
    PORT
      LAYER M5 ;
        RECT  14.352 0 14.376 0.192 ;
    END
  END xg[75]
  PIN xg[76]
    DIRECTION INPUT ;
    USE SIGNAL ;
    PORT
      LAYER M3 ;
        RECT  14.472 0 14.49 0.144 ;
    END
  END xg[76]
  PIN xg[77]
    DIRECTION INPUT ;
    USE SIGNAL ;
    PORT
      LAYER M5 ;
        RECT  14.496 0 14.52 0.192 ;
    END
  END xg[77]
  PIN xg[78]
    DIRECTION INPUT ;
    USE SIGNAL ;
    PORT
      LAYER M3 ;
        RECT  14.616 0 14.634 0.144 ;
    END
  END xg[78]
  PIN xg[79]
    DIRECTION INPUT ;
    USE SIGNAL ;
    PORT
      LAYER M5 ;
        RECT  14.64 0 14.664 0.192 ;
    END
  END xg[79]
  PIN xg[7]
    DIRECTION INPUT ;
    USE SIGNAL ;
    PORT
      LAYER M5 ;
        RECT  9.456 0 9.48 0.192 ;
    END
  END xg[7]
  PIN xg[80]
    DIRECTION INPUT ;
    USE SIGNAL ;
    PORT
      LAYER M3 ;
        RECT  14.76 0 14.778 0.144 ;
    END
  END xg[80]
  PIN xg[81]
    DIRECTION INPUT ;
    USE SIGNAL ;
    PORT
      LAYER M5 ;
        RECT  14.784 0 14.808 0.192 ;
    END
  END xg[81]
  PIN xg[82]
    DIRECTION INPUT ;
    USE SIGNAL ;
    PORT
      LAYER M3 ;
        RECT  14.904 0 14.922 0.144 ;
    END
  END xg[82]
  PIN xg[83]
    DIRECTION INPUT ;
    USE SIGNAL ;
    PORT
      LAYER M5 ;
        RECT  14.928 0 14.952 0.192 ;
    END
  END xg[83]
  PIN xg[84]
    DIRECTION INPUT ;
    USE SIGNAL ;
    PORT
      LAYER M3 ;
        RECT  15.048 0 15.066 0.144 ;
    END
  END xg[84]
  PIN xg[85]
    DIRECTION INPUT ;
    USE SIGNAL ;
    PORT
      LAYER M5 ;
        RECT  15.072 0 15.096 0.192 ;
    END
  END xg[85]
  PIN xg[86]
    DIRECTION INPUT ;
    USE SIGNAL ;
    PORT
      LAYER M3 ;
        RECT  15.192 0 15.21 0.144 ;
    END
  END xg[86]
  PIN xg[87]
    DIRECTION INPUT ;
    USE SIGNAL ;
    PORT
      LAYER M5 ;
        RECT  15.216 0 15.24 0.192 ;
    END
  END xg[87]
  PIN xg[88]
    DIRECTION INPUT ;
    USE SIGNAL ;
    PORT
      LAYER M3 ;
        RECT  15.336 0 15.354 0.144 ;
    END
  END xg[88]
  PIN xg[89]
    DIRECTION INPUT ;
    USE SIGNAL ;
    PORT
      LAYER M5 ;
        RECT  15.36 0 15.384 0.192 ;
    END
  END xg[89]
  PIN xg[8]
    DIRECTION INPUT ;
    USE SIGNAL ;
    PORT
      LAYER M3 ;
        RECT  9.576 0 9.594 0.144 ;
    END
  END xg[8]
  PIN xg[90]
    DIRECTION INPUT ;
    USE SIGNAL ;
    PORT
      LAYER M3 ;
        RECT  15.48 0 15.498 0.144 ;
    END
  END xg[90]
  PIN xg[91]
    DIRECTION INPUT ;
    USE SIGNAL ;
    PORT
      LAYER M5 ;
        RECT  15.504 0 15.528 0.192 ;
    END
  END xg[91]
  PIN xg[92]
    DIRECTION INPUT ;
    USE SIGNAL ;
    PORT
      LAYER M3 ;
        RECT  15.624 0 15.642 0.144 ;
    END
  END xg[92]
  PIN xg[93]
    DIRECTION INPUT ;
    USE SIGNAL ;
    PORT
      LAYER M5 ;
        RECT  15.648 0 15.672 0.192 ;
    END
  END xg[93]
  PIN xg[94]
    DIRECTION INPUT ;
    USE SIGNAL ;
    PORT
      LAYER M3 ;
        RECT  15.768 0 15.786 0.144 ;
    END
  END xg[94]
  PIN xg[95]
    DIRECTION INPUT ;
    USE SIGNAL ;
    PORT
      LAYER M5 ;
        RECT  15.792 0 15.816 0.192 ;
    END
  END xg[95]
  PIN xg[96]
    DIRECTION INPUT ;
    USE SIGNAL ;
    PORT
      LAYER M3 ;
        RECT  15.912 0 15.93 0.144 ;
    END
  END xg[96]
  PIN xg[97]
    DIRECTION INPUT ;
    USE SIGNAL ;
    PORT
      LAYER M5 ;
        RECT  15.936 0 15.96 0.192 ;
    END
  END xg[97]
  PIN xg[98]
    DIRECTION INPUT ;
    USE SIGNAL ;
    PORT
      LAYER M3 ;
        RECT  16.056 0 16.074 0.144 ;
    END
  END xg[98]
  PIN xg[99]
    DIRECTION INPUT ;
    USE SIGNAL ;
    PORT
      LAYER M5 ;
        RECT  16.08 0 16.104 0.192 ;
    END
  END xg[99]
  PIN xg[9]
    DIRECTION INPUT ;
    USE SIGNAL ;
    PORT
      LAYER M5 ;
        RECT  9.6 0 9.624 0.192 ;
    END
  END xg[9]
  PIN y[0]
    DIRECTION OUTPUT ;
    USE SIGNAL ;
    PORT
      LAYER M3 ;
        RECT  15.48 56.016 15.498 56.16 ;
    END
  END y[0]
  PIN y[100]
    DIRECTION OUTPUT ;
    USE SIGNAL ;
    PORT
      LAYER M3 ;
        RECT  22.68 56.016 22.698 56.16 ;
    END
  END y[100]
  PIN y[101]
    DIRECTION OUTPUT ;
    USE SIGNAL ;
    PORT
      LAYER M5 ;
        RECT  22.704 55.968 22.728 56.16 ;
    END
  END y[101]
  PIN y[102]
    DIRECTION OUTPUT ;
    USE SIGNAL ;
    PORT
      LAYER M3 ;
        RECT  22.824 56.016 22.842 56.16 ;
    END
  END y[102]
  PIN y[103]
    DIRECTION OUTPUT ;
    USE SIGNAL ;
    PORT
      LAYER M5 ;
        RECT  22.848 55.968 22.872 56.16 ;
    END
  END y[103]
  PIN y[104]
    DIRECTION OUTPUT ;
    USE SIGNAL ;
    PORT
      LAYER M3 ;
        RECT  22.968 56.016 22.986 56.16 ;
    END
  END y[104]
  PIN y[105]
    DIRECTION OUTPUT ;
    USE SIGNAL ;
    PORT
      LAYER M5 ;
        RECT  22.992 55.968 23.016 56.16 ;
    END
  END y[105]
  PIN y[106]
    DIRECTION OUTPUT ;
    USE SIGNAL ;
    PORT
      LAYER M3 ;
        RECT  23.112 56.016 23.13 56.16 ;
    END
  END y[106]
  PIN y[107]
    DIRECTION OUTPUT ;
    USE SIGNAL ;
    PORT
      LAYER M5 ;
        RECT  23.136 55.968 23.16 56.16 ;
    END
  END y[107]
  PIN y[108]
    DIRECTION OUTPUT ;
    USE SIGNAL ;
    PORT
      LAYER M3 ;
        RECT  23.256 56.016 23.274 56.16 ;
    END
  END y[108]
  PIN y[109]
    DIRECTION OUTPUT ;
    USE SIGNAL ;
    PORT
      LAYER M5 ;
        RECT  23.28 55.968 23.304 56.16 ;
    END
  END y[109]
  PIN y[10]
    DIRECTION OUTPUT ;
    USE SIGNAL ;
    PORT
      LAYER M3 ;
        RECT  16.2 56.016 16.218 56.16 ;
    END
  END y[10]
  PIN y[110]
    DIRECTION OUTPUT ;
    USE SIGNAL ;
    PORT
      LAYER M3 ;
        RECT  23.4 56.016 23.418 56.16 ;
    END
  END y[110]
  PIN y[111]
    DIRECTION OUTPUT ;
    USE SIGNAL ;
    PORT
      LAYER M5 ;
        RECT  23.424 55.968 23.448 56.16 ;
    END
  END y[111]
  PIN y[112]
    DIRECTION OUTPUT ;
    USE SIGNAL ;
    PORT
      LAYER M3 ;
        RECT  23.544 56.016 23.562 56.16 ;
    END
  END y[112]
  PIN y[113]
    DIRECTION OUTPUT ;
    USE SIGNAL ;
    PORT
      LAYER M5 ;
        RECT  23.568 55.968 23.592 56.16 ;
    END
  END y[113]
  PIN y[114]
    DIRECTION OUTPUT ;
    USE SIGNAL ;
    PORT
      LAYER M3 ;
        RECT  23.688 56.016 23.706 56.16 ;
    END
  END y[114]
  PIN y[115]
    DIRECTION OUTPUT ;
    USE SIGNAL ;
    PORT
      LAYER M5 ;
        RECT  23.712 55.968 23.736 56.16 ;
    END
  END y[115]
  PIN y[116]
    DIRECTION OUTPUT ;
    USE SIGNAL ;
    PORT
      LAYER M3 ;
        RECT  23.832 56.016 23.85 56.16 ;
    END
  END y[116]
  PIN y[117]
    DIRECTION OUTPUT ;
    USE SIGNAL ;
    PORT
      LAYER M5 ;
        RECT  23.856 55.968 23.88 56.16 ;
    END
  END y[117]
  PIN y[118]
    DIRECTION OUTPUT ;
    USE SIGNAL ;
    PORT
      LAYER M3 ;
        RECT  23.976 56.016 23.994 56.16 ;
    END
  END y[118]
  PIN y[119]
    DIRECTION OUTPUT ;
    USE SIGNAL ;
    PORT
      LAYER M5 ;
        RECT  24 55.968 24.024 56.16 ;
    END
  END y[119]
  PIN y[11]
    DIRECTION OUTPUT ;
    USE SIGNAL ;
    PORT
      LAYER M5 ;
        RECT  16.224 55.968 16.248 56.16 ;
    END
  END y[11]
  PIN y[120]
    DIRECTION OUTPUT ;
    USE SIGNAL ;
    PORT
      LAYER M3 ;
        RECT  24.12 56.016 24.138 56.16 ;
    END
  END y[120]
  PIN y[121]
    DIRECTION OUTPUT ;
    USE SIGNAL ;
    PORT
      LAYER M5 ;
        RECT  24.144 55.968 24.168 56.16 ;
    END
  END y[121]
  PIN y[122]
    DIRECTION OUTPUT ;
    USE SIGNAL ;
    PORT
      LAYER M3 ;
        RECT  24.264 56.016 24.282 56.16 ;
    END
  END y[122]
  PIN y[123]
    DIRECTION OUTPUT ;
    USE SIGNAL ;
    PORT
      LAYER M5 ;
        RECT  24.288 55.968 24.312 56.16 ;
    END
  END y[123]
  PIN y[124]
    DIRECTION OUTPUT ;
    USE SIGNAL ;
    PORT
      LAYER M3 ;
        RECT  24.408 56.016 24.426 56.16 ;
    END
  END y[124]
  PIN y[125]
    DIRECTION OUTPUT ;
    USE SIGNAL ;
    PORT
      LAYER M5 ;
        RECT  24.432 55.968 24.456 56.16 ;
    END
  END y[125]
  PIN y[126]
    DIRECTION OUTPUT ;
    USE SIGNAL ;
    PORT
      LAYER M3 ;
        RECT  24.552 56.016 24.57 56.16 ;
    END
  END y[126]
  PIN y[127]
    DIRECTION OUTPUT ;
    USE SIGNAL ;
    PORT
      LAYER M5 ;
        RECT  24.576 55.968 24.6 56.16 ;
    END
  END y[127]
  PIN y[12]
    DIRECTION OUTPUT ;
    USE SIGNAL ;
    PORT
      LAYER M3 ;
        RECT  16.344 56.016 16.362 56.16 ;
    END
  END y[12]
  PIN y[13]
    DIRECTION OUTPUT ;
    USE SIGNAL ;
    PORT
      LAYER M5 ;
        RECT  16.368 55.968 16.392 56.16 ;
    END
  END y[13]
  PIN y[14]
    DIRECTION OUTPUT ;
    USE SIGNAL ;
    PORT
      LAYER M3 ;
        RECT  16.488 56.016 16.506 56.16 ;
    END
  END y[14]
  PIN y[15]
    DIRECTION OUTPUT ;
    USE SIGNAL ;
    PORT
      LAYER M5 ;
        RECT  16.512 55.968 16.536 56.16 ;
    END
  END y[15]
  PIN y[16]
    DIRECTION OUTPUT ;
    USE SIGNAL ;
    PORT
      LAYER M3 ;
        RECT  16.632 56.016 16.65 56.16 ;
    END
  END y[16]
  PIN y[17]
    DIRECTION OUTPUT ;
    USE SIGNAL ;
    PORT
      LAYER M5 ;
        RECT  16.656 55.968 16.68 56.16 ;
    END
  END y[17]
  PIN y[18]
    DIRECTION OUTPUT ;
    USE SIGNAL ;
    PORT
      LAYER M3 ;
        RECT  16.776 56.016 16.794 56.16 ;
    END
  END y[18]
  PIN y[19]
    DIRECTION OUTPUT ;
    USE SIGNAL ;
    PORT
      LAYER M5 ;
        RECT  16.8 55.968 16.824 56.16 ;
    END
  END y[19]
  PIN y[1]
    DIRECTION OUTPUT ;
    USE SIGNAL ;
    PORT
      LAYER M5 ;
        RECT  15.504 55.968 15.528 56.16 ;
    END
  END y[1]
  PIN y[20]
    DIRECTION OUTPUT ;
    USE SIGNAL ;
    PORT
      LAYER M3 ;
        RECT  16.92 56.016 16.938 56.16 ;
    END
  END y[20]
  PIN y[21]
    DIRECTION OUTPUT ;
    USE SIGNAL ;
    PORT
      LAYER M5 ;
        RECT  16.944 55.968 16.968 56.16 ;
    END
  END y[21]
  PIN y[22]
    DIRECTION OUTPUT ;
    USE SIGNAL ;
    PORT
      LAYER M3 ;
        RECT  17.064 56.016 17.082 56.16 ;
    END
  END y[22]
  PIN y[23]
    DIRECTION OUTPUT ;
    USE SIGNAL ;
    PORT
      LAYER M5 ;
        RECT  17.088 55.968 17.112 56.16 ;
    END
  END y[23]
  PIN y[24]
    DIRECTION OUTPUT ;
    USE SIGNAL ;
    PORT
      LAYER M3 ;
        RECT  17.208 56.016 17.226 56.16 ;
    END
  END y[24]
  PIN y[25]
    DIRECTION OUTPUT ;
    USE SIGNAL ;
    PORT
      LAYER M5 ;
        RECT  17.232 55.968 17.256 56.16 ;
    END
  END y[25]
  PIN y[26]
    DIRECTION OUTPUT ;
    USE SIGNAL ;
    PORT
      LAYER M3 ;
        RECT  17.352 56.016 17.37 56.16 ;
    END
  END y[26]
  PIN y[27]
    DIRECTION OUTPUT ;
    USE SIGNAL ;
    PORT
      LAYER M5 ;
        RECT  17.376 55.968 17.4 56.16 ;
    END
  END y[27]
  PIN y[28]
    DIRECTION OUTPUT ;
    USE SIGNAL ;
    PORT
      LAYER M3 ;
        RECT  17.496 56.016 17.514 56.16 ;
    END
  END y[28]
  PIN y[29]
    DIRECTION OUTPUT ;
    USE SIGNAL ;
    PORT
      LAYER M5 ;
        RECT  17.52 55.968 17.544 56.16 ;
    END
  END y[29]
  PIN y[2]
    DIRECTION OUTPUT ;
    USE SIGNAL ;
    PORT
      LAYER M3 ;
        RECT  15.624 56.016 15.642 56.16 ;
    END
  END y[2]
  PIN y[30]
    DIRECTION OUTPUT ;
    USE SIGNAL ;
    PORT
      LAYER M3 ;
        RECT  17.64 56.016 17.658 56.16 ;
    END
  END y[30]
  PIN y[31]
    DIRECTION OUTPUT ;
    USE SIGNAL ;
    PORT
      LAYER M5 ;
        RECT  17.664 55.968 17.688 56.16 ;
    END
  END y[31]
  PIN y[32]
    DIRECTION OUTPUT ;
    USE SIGNAL ;
    PORT
      LAYER M3 ;
        RECT  17.784 56.016 17.802 56.16 ;
    END
  END y[32]
  PIN y[33]
    DIRECTION OUTPUT ;
    USE SIGNAL ;
    PORT
      LAYER M5 ;
        RECT  17.808 55.968 17.832 56.16 ;
    END
  END y[33]
  PIN y[34]
    DIRECTION OUTPUT ;
    USE SIGNAL ;
    PORT
      LAYER M3 ;
        RECT  17.928 56.016 17.946 56.16 ;
    END
  END y[34]
  PIN y[35]
    DIRECTION OUTPUT ;
    USE SIGNAL ;
    PORT
      LAYER M5 ;
        RECT  17.952 55.968 17.976 56.16 ;
    END
  END y[35]
  PIN y[36]
    DIRECTION OUTPUT ;
    USE SIGNAL ;
    PORT
      LAYER M3 ;
        RECT  18.072 56.016 18.09 56.16 ;
    END
  END y[36]
  PIN y[37]
    DIRECTION OUTPUT ;
    USE SIGNAL ;
    PORT
      LAYER M5 ;
        RECT  18.096 55.968 18.12 56.16 ;
    END
  END y[37]
  PIN y[38]
    DIRECTION OUTPUT ;
    USE SIGNAL ;
    PORT
      LAYER M3 ;
        RECT  18.216 56.016 18.234 56.16 ;
    END
  END y[38]
  PIN y[39]
    DIRECTION OUTPUT ;
    USE SIGNAL ;
    PORT
      LAYER M5 ;
        RECT  18.24 55.968 18.264 56.16 ;
    END
  END y[39]
  PIN y[3]
    DIRECTION OUTPUT ;
    USE SIGNAL ;
    PORT
      LAYER M5 ;
        RECT  15.648 55.968 15.672 56.16 ;
    END
  END y[3]
  PIN y[40]
    DIRECTION OUTPUT ;
    USE SIGNAL ;
    PORT
      LAYER M3 ;
        RECT  18.36 56.016 18.378 56.16 ;
    END
  END y[40]
  PIN y[41]
    DIRECTION OUTPUT ;
    USE SIGNAL ;
    PORT
      LAYER M5 ;
        RECT  18.384 55.968 18.408 56.16 ;
    END
  END y[41]
  PIN y[42]
    DIRECTION OUTPUT ;
    USE SIGNAL ;
    PORT
      LAYER M3 ;
        RECT  18.504 56.016 18.522 56.16 ;
    END
  END y[42]
  PIN y[43]
    DIRECTION OUTPUT ;
    USE SIGNAL ;
    PORT
      LAYER M5 ;
        RECT  18.528 55.968 18.552 56.16 ;
    END
  END y[43]
  PIN y[44]
    DIRECTION OUTPUT ;
    USE SIGNAL ;
    PORT
      LAYER M3 ;
        RECT  18.648 56.016 18.666 56.16 ;
    END
  END y[44]
  PIN y[45]
    DIRECTION OUTPUT ;
    USE SIGNAL ;
    PORT
      LAYER M5 ;
        RECT  18.672 55.968 18.696 56.16 ;
    END
  END y[45]
  PIN y[46]
    DIRECTION OUTPUT ;
    USE SIGNAL ;
    PORT
      LAYER M3 ;
        RECT  18.792 56.016 18.81 56.16 ;
    END
  END y[46]
  PIN y[47]
    DIRECTION OUTPUT ;
    USE SIGNAL ;
    PORT
      LAYER M5 ;
        RECT  18.816 55.968 18.84 56.16 ;
    END
  END y[47]
  PIN y[48]
    DIRECTION OUTPUT ;
    USE SIGNAL ;
    PORT
      LAYER M3 ;
        RECT  18.936 56.016 18.954 56.16 ;
    END
  END y[48]
  PIN y[49]
    DIRECTION OUTPUT ;
    USE SIGNAL ;
    PORT
      LAYER M5 ;
        RECT  18.96 55.968 18.984 56.16 ;
    END
  END y[49]
  PIN y[4]
    DIRECTION OUTPUT ;
    USE SIGNAL ;
    PORT
      LAYER M3 ;
        RECT  15.768 56.016 15.786 56.16 ;
    END
  END y[4]
  PIN y[50]
    DIRECTION OUTPUT ;
    USE SIGNAL ;
    PORT
      LAYER M3 ;
        RECT  19.08 56.016 19.098 56.16 ;
    END
  END y[50]
  PIN y[51]
    DIRECTION OUTPUT ;
    USE SIGNAL ;
    PORT
      LAYER M5 ;
        RECT  19.104 55.968 19.128 56.16 ;
    END
  END y[51]
  PIN y[52]
    DIRECTION OUTPUT ;
    USE SIGNAL ;
    PORT
      LAYER M3 ;
        RECT  19.224 56.016 19.242 56.16 ;
    END
  END y[52]
  PIN y[53]
    DIRECTION OUTPUT ;
    USE SIGNAL ;
    PORT
      LAYER M5 ;
        RECT  19.248 55.968 19.272 56.16 ;
    END
  END y[53]
  PIN y[54]
    DIRECTION OUTPUT ;
    USE SIGNAL ;
    PORT
      LAYER M3 ;
        RECT  19.368 56.016 19.386 56.16 ;
    END
  END y[54]
  PIN y[55]
    DIRECTION OUTPUT ;
    USE SIGNAL ;
    PORT
      LAYER M5 ;
        RECT  19.392 55.968 19.416 56.16 ;
    END
  END y[55]
  PIN y[56]
    DIRECTION OUTPUT ;
    USE SIGNAL ;
    PORT
      LAYER M3 ;
        RECT  19.512 56.016 19.53 56.16 ;
    END
  END y[56]
  PIN y[57]
    DIRECTION OUTPUT ;
    USE SIGNAL ;
    PORT
      LAYER M5 ;
        RECT  19.536 55.968 19.56 56.16 ;
    END
  END y[57]
  PIN y[58]
    DIRECTION OUTPUT ;
    USE SIGNAL ;
    PORT
      LAYER M3 ;
        RECT  19.656 56.016 19.674 56.16 ;
    END
  END y[58]
  PIN y[59]
    DIRECTION OUTPUT ;
    USE SIGNAL ;
    PORT
      LAYER M5 ;
        RECT  19.68 55.968 19.704 56.16 ;
    END
  END y[59]
  PIN y[5]
    DIRECTION OUTPUT ;
    USE SIGNAL ;
    PORT
      LAYER M5 ;
        RECT  15.792 55.968 15.816 56.16 ;
    END
  END y[5]
  PIN y[60]
    DIRECTION OUTPUT ;
    USE SIGNAL ;
    PORT
      LAYER M3 ;
        RECT  19.8 56.016 19.818 56.16 ;
    END
  END y[60]
  PIN y[61]
    DIRECTION OUTPUT ;
    USE SIGNAL ;
    PORT
      LAYER M5 ;
        RECT  19.824 55.968 19.848 56.16 ;
    END
  END y[61]
  PIN y[62]
    DIRECTION OUTPUT ;
    USE SIGNAL ;
    PORT
      LAYER M3 ;
        RECT  19.944 56.016 19.962 56.16 ;
    END
  END y[62]
  PIN y[63]
    DIRECTION OUTPUT ;
    USE SIGNAL ;
    PORT
      LAYER M5 ;
        RECT  19.968 55.968 19.992 56.16 ;
    END
  END y[63]
  PIN y[64]
    DIRECTION OUTPUT ;
    USE SIGNAL ;
    PORT
      LAYER M3 ;
        RECT  20.088 56.016 20.106 56.16 ;
    END
  END y[64]
  PIN y[65]
    DIRECTION OUTPUT ;
    USE SIGNAL ;
    PORT
      LAYER M5 ;
        RECT  20.112 55.968 20.136 56.16 ;
    END
  END y[65]
  PIN y[66]
    DIRECTION OUTPUT ;
    USE SIGNAL ;
    PORT
      LAYER M3 ;
        RECT  20.232 56.016 20.25 56.16 ;
    END
  END y[66]
  PIN y[67]
    DIRECTION OUTPUT ;
    USE SIGNAL ;
    PORT
      LAYER M5 ;
        RECT  20.256 55.968 20.28 56.16 ;
    END
  END y[67]
  PIN y[68]
    DIRECTION OUTPUT ;
    USE SIGNAL ;
    PORT
      LAYER M3 ;
        RECT  20.376 56.016 20.394 56.16 ;
    END
  END y[68]
  PIN y[69]
    DIRECTION OUTPUT ;
    USE SIGNAL ;
    PORT
      LAYER M5 ;
        RECT  20.4 55.968 20.424 56.16 ;
    END
  END y[69]
  PIN y[6]
    DIRECTION OUTPUT ;
    USE SIGNAL ;
    PORT
      LAYER M3 ;
        RECT  15.912 56.016 15.93 56.16 ;
    END
  END y[6]
  PIN y[70]
    DIRECTION OUTPUT ;
    USE SIGNAL ;
    PORT
      LAYER M3 ;
        RECT  20.52 56.016 20.538 56.16 ;
    END
  END y[70]
  PIN y[71]
    DIRECTION OUTPUT ;
    USE SIGNAL ;
    PORT
      LAYER M5 ;
        RECT  20.544 55.968 20.568 56.16 ;
    END
  END y[71]
  PIN y[72]
    DIRECTION OUTPUT ;
    USE SIGNAL ;
    PORT
      LAYER M3 ;
        RECT  20.664 56.016 20.682 56.16 ;
    END
  END y[72]
  PIN y[73]
    DIRECTION OUTPUT ;
    USE SIGNAL ;
    PORT
      LAYER M5 ;
        RECT  20.688 55.968 20.712 56.16 ;
    END
  END y[73]
  PIN y[74]
    DIRECTION OUTPUT ;
    USE SIGNAL ;
    PORT
      LAYER M3 ;
        RECT  20.808 56.016 20.826 56.16 ;
    END
  END y[74]
  PIN y[75]
    DIRECTION OUTPUT ;
    USE SIGNAL ;
    PORT
      LAYER M5 ;
        RECT  20.832 55.968 20.856 56.16 ;
    END
  END y[75]
  PIN y[76]
    DIRECTION OUTPUT ;
    USE SIGNAL ;
    PORT
      LAYER M3 ;
        RECT  20.952 56.016 20.97 56.16 ;
    END
  END y[76]
  PIN y[77]
    DIRECTION OUTPUT ;
    USE SIGNAL ;
    PORT
      LAYER M5 ;
        RECT  20.976 55.968 21 56.16 ;
    END
  END y[77]
  PIN y[78]
    DIRECTION OUTPUT ;
    USE SIGNAL ;
    PORT
      LAYER M3 ;
        RECT  21.096 56.016 21.114 56.16 ;
    END
  END y[78]
  PIN y[79]
    DIRECTION OUTPUT ;
    USE SIGNAL ;
    PORT
      LAYER M5 ;
        RECT  21.12 55.968 21.144 56.16 ;
    END
  END y[79]
  PIN y[7]
    DIRECTION OUTPUT ;
    USE SIGNAL ;
    PORT
      LAYER M5 ;
        RECT  15.936 55.968 15.96 56.16 ;
    END
  END y[7]
  PIN y[80]
    DIRECTION OUTPUT ;
    USE SIGNAL ;
    PORT
      LAYER M3 ;
        RECT  21.24 56.016 21.258 56.16 ;
    END
  END y[80]
  PIN y[81]
    DIRECTION OUTPUT ;
    USE SIGNAL ;
    PORT
      LAYER M5 ;
        RECT  21.264 55.968 21.288 56.16 ;
    END
  END y[81]
  PIN y[82]
    DIRECTION OUTPUT ;
    USE SIGNAL ;
    PORT
      LAYER M3 ;
        RECT  21.384 56.016 21.402 56.16 ;
    END
  END y[82]
  PIN y[83]
    DIRECTION OUTPUT ;
    USE SIGNAL ;
    PORT
      LAYER M5 ;
        RECT  21.408 55.968 21.432 56.16 ;
    END
  END y[83]
  PIN y[84]
    DIRECTION OUTPUT ;
    USE SIGNAL ;
    PORT
      LAYER M3 ;
        RECT  21.528 56.016 21.546 56.16 ;
    END
  END y[84]
  PIN y[85]
    DIRECTION OUTPUT ;
    USE SIGNAL ;
    PORT
      LAYER M5 ;
        RECT  21.552 55.968 21.576 56.16 ;
    END
  END y[85]
  PIN y[86]
    DIRECTION OUTPUT ;
    USE SIGNAL ;
    PORT
      LAYER M3 ;
        RECT  21.672 56.016 21.69 56.16 ;
    END
  END y[86]
  PIN y[87]
    DIRECTION OUTPUT ;
    USE SIGNAL ;
    PORT
      LAYER M5 ;
        RECT  21.696 55.968 21.72 56.16 ;
    END
  END y[87]
  PIN y[88]
    DIRECTION OUTPUT ;
    USE SIGNAL ;
    PORT
      LAYER M3 ;
        RECT  21.816 56.016 21.834 56.16 ;
    END
  END y[88]
  PIN y[89]
    DIRECTION OUTPUT ;
    USE SIGNAL ;
    PORT
      LAYER M5 ;
        RECT  21.84 55.968 21.864 56.16 ;
    END
  END y[89]
  PIN y[8]
    DIRECTION OUTPUT ;
    USE SIGNAL ;
    PORT
      LAYER M3 ;
        RECT  16.056 56.016 16.074 56.16 ;
    END
  END y[8]
  PIN y[90]
    DIRECTION OUTPUT ;
    USE SIGNAL ;
    PORT
      LAYER M3 ;
        RECT  21.96 56.016 21.978 56.16 ;
    END
  END y[90]
  PIN y[91]
    DIRECTION OUTPUT ;
    USE SIGNAL ;
    PORT
      LAYER M5 ;
        RECT  21.984 55.968 22.008 56.16 ;
    END
  END y[91]
  PIN y[92]
    DIRECTION OUTPUT ;
    USE SIGNAL ;
    PORT
      LAYER M3 ;
        RECT  22.104 56.016 22.122 56.16 ;
    END
  END y[92]
  PIN y[93]
    DIRECTION OUTPUT ;
    USE SIGNAL ;
    PORT
      LAYER M5 ;
        RECT  22.128 55.968 22.152 56.16 ;
    END
  END y[93]
  PIN y[94]
    DIRECTION OUTPUT ;
    USE SIGNAL ;
    PORT
      LAYER M3 ;
        RECT  22.248 56.016 22.266 56.16 ;
    END
  END y[94]
  PIN y[95]
    DIRECTION OUTPUT ;
    USE SIGNAL ;
    PORT
      LAYER M5 ;
        RECT  22.272 55.968 22.296 56.16 ;
    END
  END y[95]
  PIN y[96]
    DIRECTION OUTPUT ;
    USE SIGNAL ;
    PORT
      LAYER M3 ;
        RECT  22.392 56.016 22.41 56.16 ;
    END
  END y[96]
  PIN y[97]
    DIRECTION OUTPUT ;
    USE SIGNAL ;
    PORT
      LAYER M5 ;
        RECT  22.416 55.968 22.44 56.16 ;
    END
  END y[97]
  PIN y[98]
    DIRECTION OUTPUT ;
    USE SIGNAL ;
    PORT
      LAYER M3 ;
        RECT  22.536 56.016 22.554 56.16 ;
    END
  END y[98]
  PIN y[99]
    DIRECTION OUTPUT ;
    USE SIGNAL ;
    PORT
      LAYER M5 ;
        RECT  22.56 55.968 22.584 56.16 ;
    END
  END y[99]
  PIN y[9]
    DIRECTION OUTPUT ;
    USE SIGNAL ;
    PORT
      LAYER M5 ;
        RECT  16.08 55.968 16.104 56.16 ;
    END
  END y[9]
  PIN VDD
    DIRECTION INOUT ;
    USE POWER ;
    PORT
      LAYER M5 ;
        RECT  40.392 2.151 40.512 54.009 ;
        RECT  34.992 2.151 35.112 54.009 ;
        RECT  29.592 2.151 29.712 54.009 ;
        RECT  24.192 2.151 24.312 54.009 ;
        RECT  18.792 2.151 18.912 54.009 ;
        RECT  13.392 2.151 13.512 54.009 ;
        RECT  7.992 2.151 8.112 54.009 ;
        RECT  2.592 2.151 2.712 54.009 ;
    END
  END VDD
  PIN VSS
    DIRECTION INOUT ;
    USE GROUND ;
    PORT
      LAYER M5 ;
        RECT  40.2 2.137 40.32 54.023 ;
        RECT  34.8 2.137 34.92 54.023 ;
        RECT  29.4 2.137 29.52 54.023 ;
        RECT  24 2.137 24.12 54.023 ;
        RECT  18.6 2.137 18.72 54.023 ;
        RECT  13.2 2.137 13.32 54.023 ;
        RECT  7.8 2.137 7.92 54.023 ;
        RECT  2.4 2.137 2.52 54.023 ;
    END
  END VSS
  # OT_OBS_CLOSED layer=M5 d_um=1.536 added=229
  OBS
    LAYER RVTN ;
     RECT  2.16 2.16 41.04 2.295 ;
     RECT  2.16 2.565 41.04 2.835 ;
     RECT  2.16 3.105 41.04 3.375 ;
     RECT  2.16 3.645 41.04 3.915 ;
     RECT  2.16 4.185 41.04 4.455 ;
     RECT  2.16 4.725 41.04 4.995 ;
     RECT  2.16 5.265 41.04 5.535 ;
     RECT  2.16 5.805 41.04 6.075 ;
     RECT  2.16 6.345 41.04 6.615 ;
     RECT  2.16 6.885 41.04 7.155 ;
     RECT  2.16 7.425 41.04 7.695 ;
     RECT  2.16 7.965 41.04 8.235 ;
     RECT  2.16 8.505 41.04 8.775 ;
     RECT  2.16 9.045 41.04 9.315 ;
     RECT  2.16 9.585 41.04 9.855 ;
     RECT  2.16 10.125 41.04 10.395 ;
     RECT  2.16 10.665 41.04 10.935 ;
     RECT  2.16 11.205 41.04 11.475 ;
     RECT  2.16 11.745 41.04 12.015 ;
     RECT  2.16 12.285 41.04 12.555 ;
     RECT  2.16 12.825 41.04 13.095 ;
     RECT  2.16 13.365 41.04 13.635 ;
     RECT  2.16 13.905 41.04 14.175 ;
     RECT  2.16 14.445 41.04 14.715 ;
     RECT  2.16 14.985 41.04 15.255 ;
     RECT  2.16 15.525 41.04 15.795 ;
     RECT  2.16 16.065 41.04 16.335 ;
     RECT  2.16 16.605 41.04 16.875 ;
     RECT  2.16 17.145 41.04 17.415 ;
     RECT  2.16 17.685 41.04 17.955 ;
     RECT  2.16 18.225 41.04 18.495 ;
     RECT  2.16 18.765 41.04 19.035 ;
     RECT  2.16 19.305 41.04 19.575 ;
     RECT  2.16 19.845 41.04 20.115 ;
     RECT  2.16 20.385 41.04 20.655 ;
     RECT  2.16 20.925 41.04 21.195 ;
     RECT  2.16 21.465 41.04 21.735 ;
     RECT  2.16 22.005 41.04 22.275 ;
     RECT  2.16 22.545 41.04 22.815 ;
     RECT  2.16 23.085 41.04 23.355 ;
     RECT  2.16 23.625 41.04 23.895 ;
     RECT  2.16 24.165 41.04 24.435 ;
     RECT  2.16 24.705 41.04 24.975 ;
     RECT  2.16 25.245 41.04 25.515 ;
     RECT  2.16 25.785 41.04 26.055 ;
     RECT  2.16 26.325 41.04 26.595 ;
     RECT  2.16 26.865 41.04 27.135 ;
     RECT  2.16 27.405 41.04 27.675 ;
     RECT  2.16 27.945 41.04 28.215 ;
     RECT  2.16 28.485 41.04 28.755 ;
     RECT  2.16 29.025 41.04 29.295 ;
     RECT  2.16 29.565 41.04 29.835 ;
     RECT  2.16 30.105 41.04 30.375 ;
     RECT  2.16 30.645 41.04 30.915 ;
     RECT  2.16 31.185 41.04 31.455 ;
     RECT  2.16 31.725 41.04 31.995 ;
     RECT  2.16 32.265 41.04 32.535 ;
     RECT  2.16 32.805 41.04 33.075 ;
     RECT  2.16 33.345 41.04 33.615 ;
     RECT  2.16 33.885 41.04 34.155 ;
     RECT  2.16 34.425 41.04 34.695 ;
     RECT  2.16 34.965 41.04 35.235 ;
     RECT  2.16 35.505 41.04 35.775 ;
     RECT  2.16 36.045 41.04 36.315 ;
     RECT  2.16 36.585 41.04 36.855 ;
     RECT  2.16 37.125 41.04 37.395 ;
     RECT  2.16 37.665 41.04 37.935 ;
     RECT  2.16 38.205 41.04 38.475 ;
     RECT  2.16 38.745 41.04 39.015 ;
     RECT  2.16 39.285 41.04 39.555 ;
     RECT  2.16 39.825 41.04 40.095 ;
     RECT  2.16 40.365 41.04 40.635 ;
     RECT  2.16 40.905 41.04 41.175 ;
     RECT  2.16 41.445 41.04 41.715 ;
     RECT  2.16 41.985 41.04 42.255 ;
     RECT  2.16 42.525 41.04 42.795 ;
     RECT  2.16 43.065 41.04 43.335 ;
     RECT  2.16 43.605 41.04 43.875 ;
     RECT  2.16 44.145 41.04 44.415 ;
     RECT  2.16 44.685 41.04 44.955 ;
     RECT  2.16 45.225 41.04 45.495 ;
     RECT  2.16 45.765 41.04 46.035 ;
     RECT  2.16 46.305 41.04 46.575 ;
     RECT  2.16 46.845 41.04 47.115 ;
     RECT  2.16 47.385 41.04 47.655 ;
     RECT  2.16 47.925 41.04 48.195 ;
     RECT  2.16 48.465 41.04 48.735 ;
     RECT  2.16 49.005 41.04 49.275 ;
     RECT  2.16 49.545 41.04 49.815 ;
     RECT  2.16 50.085 41.04 50.355 ;
     RECT  2.16 50.625 41.04 50.895 ;
     RECT  2.16 51.165 41.04 51.435 ;
     RECT  2.16 51.705 41.04 51.975 ;
     RECT  2.16 52.245 41.04 52.515 ;
     RECT  2.16 52.785 41.04 53.055 ;
     RECT  2.16 53.325 41.04 53.595 ;
     RECT  2.16 53.865 41.04 54 ;
    LAYER RVTP ;
     RECT  2.16 2.295 41.04 2.565 ;
     RECT  2.16 2.835 41.04 3.105 ;
     RECT  2.16 3.375 41.04 3.645 ;
     RECT  2.16 3.915 41.04 4.185 ;
     RECT  2.16 4.455 41.04 4.725 ;
     RECT  2.16 4.995 41.04 5.265 ;
     RECT  2.16 5.535 41.04 5.805 ;
     RECT  2.16 6.075 41.04 6.345 ;
     RECT  2.16 6.615 41.04 6.885 ;
     RECT  2.16 7.155 41.04 7.425 ;
     RECT  2.16 7.695 41.04 7.965 ;
     RECT  2.16 8.235 41.04 8.505 ;
     RECT  2.16 8.775 41.04 9.045 ;
     RECT  2.16 9.315 41.04 9.585 ;
     RECT  2.16 9.855 41.04 10.125 ;
     RECT  2.16 10.395 41.04 10.665 ;
     RECT  2.16 10.935 41.04 11.205 ;
     RECT  2.16 11.475 41.04 11.745 ;
     RECT  2.16 12.015 41.04 12.285 ;
     RECT  2.16 12.555 41.04 12.825 ;
     RECT  2.16 13.095 41.04 13.365 ;
     RECT  2.16 13.635 41.04 13.905 ;
     RECT  2.16 14.175 41.04 14.445 ;
     RECT  2.16 14.715 41.04 14.985 ;
     RECT  2.16 15.255 41.04 15.525 ;
     RECT  2.16 15.795 41.04 16.065 ;
     RECT  2.16 16.335 41.04 16.605 ;
     RECT  2.16 16.875 41.04 17.145 ;
     RECT  2.16 17.415 41.04 17.685 ;
     RECT  2.16 17.955 41.04 18.225 ;
     RECT  2.16 18.495 41.04 18.765 ;
     RECT  2.16 19.035 41.04 19.305 ;
     RECT  2.16 19.575 41.04 19.845 ;
     RECT  2.16 20.115 41.04 20.385 ;
     RECT  2.16 20.655 41.04 20.925 ;
     RECT  2.16 21.195 41.04 21.465 ;
     RECT  2.16 21.735 41.04 22.005 ;
     RECT  2.16 22.275 41.04 22.545 ;
     RECT  2.16 22.815 41.04 23.085 ;
     RECT  2.16 23.355 41.04 23.625 ;
     RECT  2.16 23.895 41.04 24.165 ;
     RECT  2.16 24.435 41.04 24.705 ;
     RECT  2.16 24.975 41.04 25.245 ;
     RECT  2.16 25.515 41.04 25.785 ;
     RECT  2.16 26.055 41.04 26.325 ;
     RECT  2.16 26.595 41.04 26.865 ;
     RECT  2.16 27.135 41.04 27.405 ;
     RECT  2.16 27.675 41.04 27.945 ;
     RECT  2.16 28.215 41.04 28.485 ;
     RECT  2.16 28.755 41.04 29.025 ;
     RECT  2.16 29.295 41.04 29.565 ;
     RECT  2.16 29.835 41.04 30.105 ;
     RECT  2.16 30.375 41.04 30.645 ;
     RECT  2.16 30.915 41.04 31.185 ;
     RECT  2.16 31.455 41.04 31.725 ;
     RECT  2.16 31.995 41.04 32.265 ;
     RECT  2.16 32.535 41.04 32.805 ;
     RECT  2.16 33.075 41.04 33.345 ;
     RECT  2.16 33.615 41.04 33.885 ;
     RECT  2.16 34.155 41.04 34.425 ;
     RECT  2.16 34.695 41.04 34.965 ;
     RECT  2.16 35.235 41.04 35.505 ;
     RECT  2.16 35.775 41.04 36.045 ;
     RECT  2.16 36.315 41.04 36.585 ;
     RECT  2.16 36.855 41.04 37.125 ;
     RECT  2.16 37.395 41.04 37.665 ;
     RECT  2.16 37.935 41.04 38.205 ;
     RECT  2.16 38.475 41.04 38.745 ;
     RECT  2.16 39.015 41.04 39.285 ;
     RECT  2.16 39.555 41.04 39.825 ;
     RECT  2.16 40.095 41.04 40.365 ;
     RECT  2.16 40.635 41.04 40.905 ;
     RECT  2.16 41.175 41.04 41.445 ;
     RECT  2.16 41.715 41.04 41.985 ;
     RECT  2.16 42.255 41.04 42.525 ;
     RECT  2.16 42.795 41.04 43.065 ;
     RECT  2.16 43.335 41.04 43.605 ;
     RECT  2.16 43.875 41.04 44.145 ;
     RECT  2.16 44.415 41.04 44.685 ;
     RECT  2.16 44.955 41.04 45.225 ;
     RECT  2.16 45.495 41.04 45.765 ;
     RECT  2.16 46.035 41.04 46.305 ;
     RECT  2.16 46.575 41.04 46.845 ;
     RECT  2.16 47.115 41.04 47.385 ;
     RECT  2.16 47.655 41.04 47.925 ;
     RECT  2.16 48.195 41.04 48.465 ;
     RECT  2.16 48.735 41.04 49.005 ;
     RECT  2.16 49.275 41.04 49.545 ;
     RECT  2.16 49.815 41.04 50.085 ;
     RECT  2.16 50.355 41.04 50.625 ;
     RECT  2.16 50.895 41.04 51.165 ;
     RECT  2.16 51.435 41.04 51.705 ;
     RECT  2.16 51.975 41.04 52.245 ;
     RECT  2.16 52.515 41.04 52.785 ;
     RECT  2.16 53.055 41.04 53.325 ;
     RECT  2.16 53.595 41.04 53.865 ;
    LAYER M1 ;
     RECT  2.16 2.151 41.04 54.009 ;
    LAYER M2 ;
     RECT  0.247 34.974 1.147 34.992 ;
     RECT  0.535 33.426 2.16 33.444 ;
     RECT  0.211 34.2 2.16 34.218 ;
     RECT  1.147 34.974 2.16 35.424 ;
     RECT  1.435 36.792 2.16 36.81 ;
     RECT  2.16 2.151 8.995 54.009 ;
     RECT  8.995 2.151 9.095 54.702 ;
     RECT  9.095 2.151 9.139 54.009 ;
     RECT  9.859 0.144 9.959 0.162 ;
     RECT  9.139 1.728 10.607 54.009 ;
     RECT  11.011 0.144 11.111 0.162 ;
     RECT  10.607 2.151 11.443 54.009 ;
     RECT  11.443 2.151 11.767 54.054 ;
     RECT  11.767 2.151 11.903 54.126 ;
     RECT  11.903 2.151 13.171 54.009 ;
     RECT  13.171 2.151 13.595 54.054 ;
     RECT  13.595 2.151 15.043 54.009 ;
     RECT  15.043 1.728 15.215 54.009 ;
     RECT  16.051 55.422 16.151 55.44 ;
     RECT  16.771 54.801 16.871 54.819 ;
     RECT  15.215 2.151 17.203 54.009 ;
     RECT  17.203 1.728 17.339 54.009 ;
     RECT  17.339 2.151 18.535 54.009 ;
     RECT  18.535 2.151 19.147 54.09 ;
     RECT  19.147 2.151 19.391 54.126 ;
     RECT  19.391 2.151 19.651 54.054 ;
     RECT  19.651 2.106 20.219 54.054 ;
     RECT  20.219 2.106 20.471 54.009 ;
     RECT  20.471 2.151 21.091 54.009 ;
     RECT  21.091 2.151 21.235 54.054 ;
     RECT  21.235 2.151 21.379 54.63 ;
     RECT  21.379 2.151 21.479 54.702 ;
     RECT  22.063 0.261 22.199 0.279 ;
     RECT  21.479 2.151 22.243 54.009 ;
     RECT  22.531 0.144 23.063 0.162 ;
     RECT  22.243 2.151 23.827 54.702 ;
     RECT  23.827 2.151 23.891 55.44 ;
     RECT  24.367 1.152 24.467 1.17 ;
     RECT  23.891 55.422 24.647 55.44 ;
     RECT  23.891 2.151 24.691 54.126 ;
     RECT  24.691 1.728 24.827 54.126 ;
     RECT  24.979 0.144 25.079 0.162 ;
     RECT  24.827 1.728 26.123 54.009 ;
     RECT  26.123 2.151 32.035 54.009 ;
     RECT  32.035 2.106 32.927 54.009 ;
     RECT  32.927 2.151 41.04 54.009 ;
    LAYER M3 ;
     RECT  9 0.108 27.306 0.173 ;
     RECT  9.144 0.173 27.306 0.283 ;
     RECT  9.144 0.283 27.378 0.317 ;
     RECT  9.216 0.317 27.378 0.413 ;
     RECT  9.576 0.413 14.202 0.461 ;
     RECT  15.048 0.413 27.378 0.461 ;
     RECT  9.576 0.461 14.13 0.509 ;
     RECT  15.048 0.461 19.386 0.509 ;
     RECT  20.304 0.461 27.378 0.509 ;
     RECT  9.576 0.509 14.058 0.557 ;
     RECT  15.048 0.509 17.658 0.557 ;
     RECT  18.504 0.509 18.81 0.557 ;
     RECT  20.304 0.509 23.454 0.557 ;
     RECT  24.372 0.509 27.378 0.557 ;
     RECT  13.932 0.557 14.058 0.605 ;
     RECT  20.988 0.557 21.006 0.605 ;
     RECT  23.436 0.557 23.454 0.605 ;
     RECT  9.576 0.557 13.05 1.723 ;
     RECT  14.04 0.605 14.058 1.723 ;
     RECT  15.048 0.557 15.066 1.723 ;
     RECT  15.912 0.557 17.226 1.723 ;
     RECT  21.996 0.557 22.698 1.723 ;
     RECT  24.372 0.557 26.586 1.723 ;
     RECT  27.36 0.557 27.378 1.723 ;
     RECT  9.144 1.723 14.31 1.771 ;
     RECT  15.048 1.723 23.31 1.771 ;
     RECT  24.372 1.723 27.378 1.771 ;
     RECT  9.144 1.771 27.378 1.819 ;
     RECT  9.144 1.819 27.522 2.107 ;
     RECT  9.144 2.107 28.026 2.155 ;
     RECT  32.04 2.101 32.058 2.155 ;
     RECT  7.815 2.143 7.905 2.191 ;
     RECT  8.748 2.155 28.026 2.191 ;
     RECT  29.415 2.143 29.505 2.191 ;
     RECT  31.572 2.155 32.058 2.191 ;
     RECT  7.38 2.191 28.026 2.203 ;
     RECT  32.904 2.101 32.922 2.203 ;
     RECT  5.724 2.191 5.886 2.227 ;
     RECT  29.124 2.191 29.505 2.227 ;
     RECT  31.572 2.191 32.13 2.227 ;
     RECT  32.904 2.203 33.462 2.227 ;
     RECT  28.98 2.227 29.505 2.251 ;
     RECT  31.572 2.227 33.822 2.251 ;
     RECT  28.98 2.251 30.042 2.263 ;
     RECT  31.392 2.251 33.822 2.263 ;
     RECT  28.836 2.263 30.222 2.299 ;
     RECT  31.32 2.263 33.822 2.299 ;
     RECT  5.58 2.227 6.426 2.371 ;
     RECT  31.32 2.299 33.894 2.371 ;
     RECT  34.815 2.143 34.905 2.371 ;
     RECT  2.415 2.143 2.505 2.413 ;
     RECT  3.348 2.335 3.51 2.413 ;
     RECT  31.32 2.371 34.905 2.413 ;
     RECT  40.215 2.143 40.305 2.413 ;
     RECT  2.415 2.413 3.51 2.461 ;
     RECT  4.428 2.371 6.426 2.461 ;
     RECT  31.32 2.413 35.097 2.533 ;
     RECT  2.415 2.461 6.462 2.569 ;
     RECT  7.2 2.203 28.026 2.569 ;
     RECT  31.32 2.533 35.226 2.587 ;
     RECT  2.415 2.569 28.026 2.605 ;
     RECT  28.836 2.299 30.438 2.605 ;
     RECT  31.248 2.587 35.226 2.605 ;
     RECT  36.432 2.461 36.45 2.605 ;
     RECT  2.415 2.605 36.45 2.641 ;
     RECT  38.196 2.533 38.214 2.767 ;
     RECT  38.196 2.767 38.718 2.803 ;
     RECT  37.908 2.803 38.718 2.875 ;
     RECT  37.836 2.875 38.718 2.911 ;
     RECT  40.215 2.413 40.497 2.911 ;
     RECT  2.376 2.641 36.522 3.067 ;
     RECT  2.376 3.067 36.594 3.073 ;
     RECT  37.8 2.911 38.718 3.073 ;
     RECT  2.376 3.073 36.774 3.109 ;
     RECT  2.376 3.109 36.846 3.145 ;
     RECT  37.656 3.073 38.718 3.145 ;
     RECT  40.215 2.911 40.554 3.271 ;
     RECT  2.376 3.145 38.718 3.403 ;
     RECT  39.456 2.767 39.474 3.403 ;
     RECT  2.376 3.403 39.474 3.415 ;
     RECT  40.215 3.271 40.698 3.415 ;
     RECT  2.376 3.415 40.698 3.965 ;
     RECT  2.376 3.965 35.37 4.415 ;
     RECT  2.376 4.415 35.262 4.999 ;
     RECT  2.34 4.999 35.262 5.503 ;
     RECT  2.34 5.503 35.334 5.539 ;
     RECT  2.34 5.539 35.478 5.765 ;
     RECT  36.252 3.965 40.698 5.809 ;
     RECT  2.376 5.765 35.478 5.881 ;
     RECT  36.216 5.809 40.698 5.881 ;
     RECT  2.376 5.881 40.698 5.999 ;
     RECT  2.415 5.999 40.698 7.189 ;
     RECT  2.412 7.189 40.698 7.229 ;
     RECT  2.415 7.229 40.698 7.385 ;
     RECT  40.176 7.385 40.698 7.771 ;
     RECT  2.415 7.385 39.402 8.311 ;
     RECT  40.176 7.771 40.734 8.311 ;
     RECT  2.415 8.311 40.734 8.429 ;
     RECT  2.415 8.429 39.402 8.969 ;
     RECT  40.215 8.429 40.734 9.041 ;
     RECT  34.308 8.969 39.402 9.211 ;
     RECT  40.215 9.041 40.698 9.211 ;
     RECT  2.415 8.969 33.57 9.787 ;
     RECT  34.308 9.211 40.698 9.787 ;
     RECT  2.415 9.787 40.698 10.085 ;
     RECT  36.864 10.085 40.698 10.157 ;
     RECT  36.9 10.157 40.698 10.355 ;
     RECT  36.972 10.355 40.698 10.741 ;
     RECT  36.972 10.741 40.77 10.831 ;
     RECT  2.415 10.085 35.91 11.101 ;
     RECT  2.415 11.101 36.054 11.131 ;
     RECT  36.972 10.831 40.95 11.131 ;
     RECT  2.415 11.131 40.95 11.281 ;
     RECT  2.376 11.281 40.95 11.981 ;
     RECT  39.42 11.981 40.95 12.557 ;
     RECT  2.376 11.981 38.646 12.901 ;
     RECT  2.376 12.901 39.042 13.369 ;
     RECT  39.816 12.557 40.95 13.369 ;
     RECT  2.376 13.369 40.95 13.387 ;
     RECT  2.34 13.387 40.95 14.549 ;
     RECT  2.34 14.549 33.57 14.639 ;
     RECT  2.376 14.639 33.57 14.711 ;
     RECT  34.38 14.549 40.95 15.053 ;
     RECT  2.415 14.711 33.57 15.421 ;
     RECT  2.415 15.421 33.642 15.799 ;
     RECT  2.415 15.799 33.858 15.871 ;
     RECT  34.596 15.053 40.95 15.871 ;
     RECT  2.415 15.871 40.95 17.249 ;
     RECT  35.964 17.249 40.95 17.879 ;
     RECT  35.964 17.879 39.294 18.077 ;
     RECT  2.415 17.249 35.097 18.091 ;
     RECT  35.964 18.077 39.186 18.091 ;
     RECT  2.415 18.091 39.186 18.149 ;
     RECT  2.415 18.149 39.15 18.221 ;
     RECT  2.415 18.221 18.897 18.427 ;
     RECT  2.376 18.427 18.897 18.491 ;
     RECT  2.376 18.491 13.662 18.599 ;
     RECT  40.068 17.879 40.95 18.797 ;
     RECT  40.068 18.797 40.878 18.841 ;
     RECT  39.96 18.841 40.878 18.869 ;
     RECT  19.656 18.221 39.15 18.959 ;
     RECT  19.692 18.959 39.15 19.339 ;
     RECT  39.96 18.869 40.842 19.339 ;
     RECT  2.376 18.599 13.59 19.381 ;
     RECT  14.436 18.491 18.897 19.381 ;
     RECT  2.376 19.381 18.897 19.499 ;
     RECT  19.692 19.339 40.842 19.679 ;
     RECT  14.328 19.499 18.897 19.769 ;
     RECT  14.4 19.769 18.897 19.921 ;
     RECT  19.692 19.679 21.87 19.921 ;
     RECT  2.376 19.499 13.59 20.155 ;
     RECT  22.608 19.679 40.842 20.309 ;
     RECT  22.608 20.309 39.438 20.345 ;
     RECT  14.4 19.921 21.87 20.461 ;
     RECT  22.608 20.345 26.838 20.461 ;
     RECT  2.34 20.155 13.59 20.539 ;
     RECT  14.4 20.461 26.838 20.539 ;
     RECT  27.612 20.345 39.438 20.723 ;
     RECT  33.048 20.723 39.438 20.849 ;
     RECT  33.12 20.849 39.438 20.957 ;
     RECT  2.34 20.539 26.838 21.115 ;
     RECT  27.612 20.723 32.31 21.115 ;
     RECT  33.156 20.957 39.438 21.115 ;
     RECT  40.215 20.309 40.842 21.115 ;
     RECT  2.34 21.115 32.31 21.227 ;
     RECT  33.156 21.115 39.474 21.271 ;
     RECT  40.212 21.115 40.842 21.271 ;
     RECT  2.376 21.227 32.31 21.929 ;
     RECT  33.156 21.271 40.842 21.973 ;
     RECT  27.36 21.929 32.31 22.081 ;
     RECT  33.156 21.973 40.95 22.081 ;
     RECT  2.376 21.929 26.622 22.711 ;
     RECT  27.36 22.081 40.95 22.711 ;
     RECT  2.376 22.711 40.95 22.775 ;
     RECT  33.048 22.775 40.95 22.781 ;
     RECT  33.084 22.781 40.95 23.351 ;
     RECT  33.192 23.351 40.95 23.621 ;
     RECT  2.415 22.775 32.202 23.701 ;
     RECT  2.415 23.701 32.274 23.863 ;
     RECT  2.415 23.863 32.382 23.933 ;
     RECT  2.415 23.933 32.238 24.173 ;
     RECT  33.336 23.621 40.95 24.475 ;
     RECT  15.876 24.173 32.238 24.781 ;
     RECT  33.048 24.475 40.95 24.781 ;
     RECT  15.876 24.781 40.95 24.809 ;
     RECT  34.38 24.809 40.95 24.899 ;
     RECT  34.452 24.899 40.95 25.007 ;
     RECT  15.876 24.809 33.534 25.045 ;
     RECT  34.776 25.007 40.95 25.169 ;
     RECT  34.776 25.169 40.914 25.349 ;
     RECT  2.415 24.173 14.85 25.411 ;
     RECT  15.732 25.045 33.534 25.411 ;
     RECT  2.415 25.411 33.534 25.511 ;
     RECT  28.98 25.511 33.534 25.591 ;
     RECT  35.928 25.349 40.914 26.015 ;
     RECT  34.776 25.349 35.097 26.131 ;
     RECT  2.415 25.511 28.242 26.251 ;
     RECT  28.98 25.591 33.606 26.251 ;
     RECT  34.56 26.131 35.097 26.293 ;
     RECT  2.415 26.251 33.606 26.365 ;
     RECT  34.452 26.293 35.097 26.365 ;
     RECT  2.415 26.365 35.097 26.401 ;
     RECT  2.376 26.401 35.097 26.591 ;
     RECT  2.415 26.591 35.097 26.761 ;
     RECT  2.415 26.761 35.334 26.789 ;
     RECT  36.144 26.015 40.914 26.825 ;
     RECT  25.992 26.789 35.334 27.599 ;
     RECT  27.756 27.599 35.334 27.643 ;
     RECT  36.144 26.825 40.806 27.643 ;
     RECT  2.415 26.789 25.11 27.841 ;
     RECT  25.992 27.599 26.91 27.841 ;
     RECT  27.756 27.643 40.806 28.013 ;
     RECT  2.415 27.841 26.91 28.408 ;
     RECT  27.756 28.013 40.698 28.408 ;
     RECT  2.415 28.408 40.698 28.831 ;
     RECT  2.415 28.831 40.842 29.069 ;
     RECT  2.415 29.069 25.65 29.101 ;
     RECT  2.376 29.101 25.65 29.219 ;
     RECT  26.424 29.069 40.842 29.219 ;
     RECT  26.496 29.219 40.842 29.255 ;
     RECT  26.496 29.255 40.806 29.645 ;
     RECT  26.496 29.645 40.662 29.939 ;
     RECT  2.415 29.219 25.65 30.187 ;
     RECT  26.496 29.939 30.762 30.187 ;
     RECT  2.415 30.187 30.762 30.415 ;
     RECT  2.34 30.415 30.762 30.685 ;
     RECT  31.5 29.939 40.662 30.721 ;
     RECT  2.304 30.685 30.762 30.811 ;
     RECT  31.5 30.721 40.698 30.811 ;
     RECT  1.152 30.715 1.17 30.845 ;
     RECT  2.304 30.811 40.698 31.109 ;
     RECT  22.644 31.109 40.698 31.153 ;
     RECT  22.644 31.153 40.806 31.261 ;
     RECT  22.644 31.261 40.842 31.379 ;
     RECT  23.724 31.379 40.842 31.559 ;
     RECT  2.304 31.109 21.834 32.071 ;
     RECT  22.644 31.379 22.95 32.071 ;
     RECT  23.724 31.559 40.77 32.189 ;
     RECT  2.304 32.071 22.95 32.341 ;
     RECT  23.724 32.189 40.734 32.341 ;
     RECT  2.304 32.341 40.734 32.495 ;
     RECT  2.304 32.495 21.834 33.115 ;
     RECT  2.232 33.115 21.834 33.179 ;
     RECT  2.304 33.179 21.834 33.385 ;
     RECT  0.54 33.421 0.558 33.499 ;
     RECT  0.54 33.499 1.17 33.643 ;
     RECT  0.216 33.643 1.17 33.821 ;
     RECT  0.216 33.821 0.27 34.223 ;
     RECT  2.304 33.385 21.906 34.321 ;
     RECT  22.644 32.495 40.734 34.321 ;
     RECT  1.152 33.821 1.17 34.363 ;
     RECT  2.304 34.321 40.734 34.925 ;
     RECT  0.252 34.223 0.27 34.997 ;
     RECT  1.152 34.363 1.458 35.429 ;
     RECT  2.415 34.925 40.734 35.609 ;
     RECT  2.415 35.609 36.882 36.391 ;
     RECT  37.62 35.609 40.734 36.391 ;
     RECT  2.415 36.391 40.734 36.661 ;
     RECT  1.44 35.429 1.458 36.815 ;
     RECT  2.376 36.661 40.734 37.435 ;
     RECT  2.376 37.435 40.914 37.597 ;
     RECT  2.34 37.597 40.914 38.165 ;
     RECT  2.34 38.165 37.818 38.765 ;
     RECT  37.764 38.765 37.818 39.055 ;
     RECT  38.556 38.165 40.914 39.055 ;
     RECT  37.764 39.055 40.914 39.289 ;
     RECT  37.764 39.289 40.95 39.341 ;
     RECT  2.415 38.765 37.026 39.559 ;
     RECT  37.764 39.341 40.59 39.559 ;
     RECT  2.415 39.559 40.59 40.325 ;
     RECT  2.415 40.325 38.97 40.531 ;
     RECT  2.376 40.531 38.97 40.589 ;
     RECT  39.78 40.325 40.59 40.711 ;
     RECT  2.415 40.589 38.97 40.733 ;
     RECT  39.78 40.711 40.914 40.901 ;
     RECT  11.736 40.733 38.97 41.485 ;
     RECT  2.415 40.733 10.818 41.611 ;
     RECT  11.592 41.485 38.97 41.611 ;
     RECT  2.415 41.611 38.97 41.791 ;
     RECT  39.78 40.901 40.497 41.791 ;
     RECT  2.415 41.791 40.497 42.871 ;
     RECT  2.415 42.871 40.842 42.989 ;
     RECT  2.415 42.989 40.554 43.169 ;
     RECT  2.415 43.169 36.054 43.259 ;
     RECT  36.792 43.169 40.554 43.565 ;
     RECT  2.415 43.259 35.982 44.077 ;
     RECT  36.792 43.565 36.918 44.077 ;
     RECT  38.556 43.565 40.554 44.221 ;
     RECT  2.415 44.077 36.918 44.455 ;
     RECT  37.8 43.565 37.818 44.455 ;
     RECT  2.415 44.455 37.818 44.581 ;
     RECT  38.556 44.221 40.842 44.581 ;
     RECT  2.415 44.581 40.842 44.609 ;
     RECT  2.415 44.609 40.698 44.879 ;
     RECT  2.415 44.879 40.59 44.995 ;
     RECT  2.376 44.995 40.59 45.967 ;
     RECT  2.376 45.967 40.626 46.337 ;
     RECT  2.415 46.337 40.626 46.381 ;
     RECT  2.415 46.381 40.77 46.769 ;
     RECT  2.415 46.769 40.662 46.805 ;
     RECT  2.415 46.805 40.59 47.461 ;
     RECT  2.376 47.461 40.59 47.849 ;
     RECT  2.415 47.849 40.59 48.001 ;
     RECT  2.415 48.001 40.806 48.119 ;
     RECT  2.415 48.119 40.497 48.929 ;
     RECT  2.415 48.929 39.33 49.073 ;
     RECT  2.415 49.073 33.462 49.469 ;
     RECT  2.415 49.469 31.698 49.505 ;
     RECT  32.508 49.469 33.462 50.045 ;
     RECT  34.2 49.073 39.33 50.107 ;
     RECT  40.215 48.929 40.497 50.107 ;
     RECT  4.032 49.505 31.698 50.141 ;
     RECT  2.415 49.505 3.294 50.683 ;
     RECT  4.032 50.141 30.69 50.683 ;
     RECT  34.2 50.107 40.497 50.693 ;
     RECT  34.2 50.693 37.962 50.717 ;
     RECT  31.5 50.141 31.698 50.779 ;
     RECT  32.508 50.045 33.426 50.779 ;
     RECT  2.415 50.683 30.69 50.819 ;
     RECT  31.5 50.779 33.426 50.819 ;
     RECT  38.736 50.693 40.497 50.819 ;
     RECT  4.104 50.819 30.69 50.863 ;
     RECT  31.5 50.819 33.318 50.863 ;
     RECT  2.415 50.819 3.294 51.269 ;
     RECT  38.736 50.819 38.754 51.269 ;
     RECT  34.2 50.717 37.422 51.511 ;
     RECT  4.104 50.863 33.318 51.601 ;
     RECT  34.2 51.511 37.494 51.601 ;
     RECT  4.104 51.601 37.494 51.701 ;
     RECT  4.104 51.701 37.098 51.745 ;
     RECT  39.888 50.819 40.497 51.773 ;
     RECT  2.415 51.269 3.114 52.051 ;
     RECT  3.96 51.745 37.098 52.051 ;
     RECT  2.415 52.051 37.098 52.211 ;
     RECT  3.672 52.211 37.098 52.591 ;
     RECT  37.872 52.321 37.89 52.591 ;
     RECT  3.672 52.591 37.926 52.861 ;
     RECT  3.672 52.861 38.034 52.979 ;
     RECT  3.852 52.979 38.034 53.035 ;
     RECT  3.852 53.035 38.646 53.249 ;
     RECT  3.852 53.249 32.562 53.285 ;
     RECT  3.852 53.285 31.41 53.321 ;
     RECT  28.296 53.321 31.41 53.405 ;
     RECT  28.296 53.405 30.258 53.429 ;
     RECT  3.852 53.321 27.522 53.519 ;
     RECT  29.376 53.429 30.258 53.519 ;
     RECT  31.068 53.405 31.41 53.519 ;
     RECT  32.256 53.285 32.562 53.519 ;
     RECT  33.48 53.249 38.142 53.519 ;
     RECT  3.852 53.519 3.87 53.555 ;
     RECT  4.608 53.519 27.522 53.555 ;
     RECT  32.544 53.519 32.562 53.555 ;
     RECT  28.296 53.429 28.602 53.591 ;
     RECT  29.415 53.519 30.258 53.591 ;
     RECT  33.516 53.519 38.142 53.597 ;
     RECT  33.516 53.597 37.35 53.699 ;
     RECT  2.415 52.211 2.697 53.747 ;
     RECT  29.415 53.591 29.697 53.747 ;
     RECT  33.516 53.699 35.097 53.747 ;
     RECT  40.215 51.773 40.497 53.747 ;
     RECT  4.644 53.555 27.522 53.789 ;
     RECT  28.296 53.591 28.314 53.789 ;
     RECT  33.516 53.747 34.938 53.789 ;
     RECT  35.856 53.699 37.35 53.789 ;
     RECT  38.124 53.597 38.142 53.789 ;
     RECT  6.048 53.789 14.13 53.825 ;
     RECT  27.36 53.789 27.378 53.825 ;
     RECT  34.416 53.789 34.905 53.825 ;
     RECT  36.792 53.789 37.206 53.825 ;
     RECT  4.716 53.789 5.13 53.861 ;
     RECT  7.815 53.825 14.13 53.861 ;
     RECT  15.192 53.789 25.074 53.861 ;
     RECT  5.112 53.861 5.13 53.897 ;
     RECT  6.048 53.825 6.534 53.897 ;
     RECT  7.815 53.861 13.626 53.933 ;
     RECT  33.516 53.789 33.534 53.933 ;
     RECT  6.192 53.897 6.534 53.969 ;
     RECT  7.815 53.933 8.19 53.969 ;
     RECT  25.884 53.789 26.01 53.969 ;
     RECT  35.856 53.789 35.874 53.969 ;
     RECT  2.415 53.747 2.505 54.017 ;
     RECT  7.815 53.969 7.905 54.017 ;
     RECT  29.415 53.747 29.505 54.017 ;
     RECT  34.815 53.825 34.905 54.017 ;
     RECT  40.215 53.747 40.305 54.017 ;
     RECT  9.072 53.933 13.626 54.125 ;
     RECT  15.372 53.861 24.822 54.131 ;
     RECT  9.072 54.125 13.482 54.679 ;
     RECT  15.372 54.131 24.642 54.749 ;
     RECT  15.48 54.749 24.642 55.445 ;
     RECT  9 54.679 13.482 56.028 ;
     RECT  15.48 55.445 24.57 56.028 ;
    LAYER M4 ;
     RECT  0.156 31.056 0.181 34.392 ;
     RECT  0.181 30.816 1.141 34.392 ;
     RECT  2.293 13.392 2.329 13.416 ;
     RECT  2.293 4.128 2.401 4.152 ;
     RECT  2.365 5.856 2.401 5.88 ;
     RECT  2.293 2.784 2.408 2.808 ;
     RECT  2.401 4.128 2.408 5.88 ;
     RECT  2.401 7.2 2.408 7.224 ;
     RECT  2.293 12.24 2.408 12.264 ;
     RECT  2.329 13.392 2.408 13.704 ;
     RECT  2.293 14.736 2.408 14.76 ;
     RECT  2.293 17.088 2.408 17.112 ;
     RECT  2.365 19.776 2.408 21.192 ;
     RECT  0.227 27.648 2.408 27.672 ;
     RECT  1.141 30.72 2.408 34.392 ;
     RECT  2.329 38.736 2.408 38.76 ;
     RECT  2.365 40.56 2.408 40.584 ;
     RECT  2.408 2.148 2.512 54.012 ;
     RECT  2.512 2.418 2.704 53.742 ;
     RECT  2.704 2.592 2.819 8.472 ;
     RECT  2.704 14.688 2.867 25.32 ;
     RECT  2.867 19.392 2.905 25.32 ;
     RECT  2.905 19.392 3.061 23.976 ;
     RECT  3.061 19.392 3.521 23.832 ;
     RECT  2.867 14.688 3.587 18.216 ;
     RECT  3.521 19.392 3.587 22.104 ;
     RECT  2.905 25.104 3.593 25.32 ;
     RECT  2.704 10.032 3.629 13.704 ;
     RECT  3.521 23.808 3.665 23.832 ;
     RECT  3.587 19.392 3.709 19.992 ;
     RECT  2.819 2.592 3.797 6.984 ;
     RECT  2.819 8.16 3.797 8.472 ;
     RECT  3.587 21.12 3.827 22.104 ;
     RECT  2.704 28.992 3.841 44.856 ;
     RECT  3.709 19.68 3.845 19.992 ;
     RECT  3.841 28.992 3.845 45.144 ;
     RECT  3.797 2.592 3.881 8.472 ;
     RECT  3.845 36.864 3.917 45.144 ;
     RECT  3.917 37.056 3.925 45.144 ;
     RECT  3.629 10.032 3.949 12.888 ;
     RECT  2.704 26.736 3.973 27.576 ;
     RECT  3.845 28.992 3.973 35.592 ;
     RECT  2.704 50.688 3.973 50.712 ;
     RECT  3.925 37.056 3.989 45.576 ;
     RECT  2.704 51.888 3.989 52.2 ;
     RECT  3.593 25.296 4.021 25.32 ;
     RECT  3.845 19.68 4.025 19.704 ;
     RECT  3.989 42.192 4.025 45.576 ;
     RECT  3.989 52.176 4.025 52.2 ;
     RECT  3.973 50.112 4.061 50.808 ;
     RECT  3.973 26.736 4.067 35.592 ;
     RECT  3.989 37.056 4.067 41.112 ;
     RECT  4.025 42.192 4.097 45.144 ;
     RECT  4.067 37.056 4.115 38.136 ;
     RECT  4.097 42.192 4.115 45.048 ;
     RECT  3.949 9.936 4.169 12.888 ;
     RECT  4.061 50.784 4.205 50.808 ;
     RECT  4.021 25.296 4.309 25.656 ;
     RECT  4.067 26.736 4.309 27.912 ;
     RECT  4.115 42.192 4.403 45 ;
     RECT  4.169 9.936 4.457 12.792 ;
     RECT  4.067 39.216 4.573 41.112 ;
     RECT  3.881 2.592 4.595 8.424 ;
     RECT  4.457 10.032 4.601 12.792 ;
     RECT  3.587 14.688 4.601 17.736 ;
     RECT  4.309 25.296 4.709 27.912 ;
     RECT  4.403 42.192 4.709 43.992 ;
     RECT  4.601 17.616 4.849 17.736 ;
     RECT  4.595 8.16 4.885 8.424 ;
     RECT  4.067 28.992 4.921 35.592 ;
     RECT  4.115 37.056 4.921 37.608 ;
     RECT  4.741 23.424 4.997 23.448 ;
     RECT  4.601 14.688 5.105 16.536 ;
     RECT  4.525 47.28 5.125 47.304 ;
     RECT  4.381 48.864 5.125 48.888 ;
     RECT  4.921 28.992 5.137 37.608 ;
     RECT  4.573 39.216 5.137 40.056 ;
     RECT  5.137 28.992 5.141 40.056 ;
     RECT  4.573 41.088 5.245 41.112 ;
     RECT  4.709 42.192 5.245 42.216 ;
     RECT  4.885 8.16 5.249 8.52 ;
     RECT  5.173 51.888 5.317 51.912 ;
     RECT  5.101 53.376 5.317 53.4 ;
     RECT  4.595 2.592 5.357 6.84 ;
     RECT  5.125 47.28 5.363 48.888 ;
     RECT  4.709 26.448 5.389 27.912 ;
     RECT  5.141 28.992 5.389 38.472 ;
     RECT  5.363 47.28 5.389 48.12 ;
     RECT  4.709 25.296 5.429 25.32 ;
     RECT  5.389 26.448 5.465 38.472 ;
     RECT  5.245 41.088 5.569 42.216 ;
     RECT  5.105 15.024 5.633 16.536 ;
     RECT  4.849 17.616 5.633 18.6 ;
     RECT  5.633 15.024 5.641 18.6 ;
     RECT  4.403 44.976 5.653 45 ;
     RECT  5.389 46.752 5.653 48.12 ;
     RECT  5.569 41.04 5.681 42.216 ;
     RECT  5.653 44.976 5.699 48.12 ;
     RECT  4.601 10.032 5.701 12.504 ;
     RECT  5.357 2.592 5.713 6.792 ;
     RECT  5.641 15.024 5.717 18.84 ;
     RECT  5.681 41.088 5.753 42.216 ;
     RECT  5.249 8.16 5.789 8.424 ;
     RECT  5.701 10.032 5.893 12.6 ;
     RECT  5.893 9.6 5.897 12.6 ;
     RECT  4.709 43.536 5.929 43.992 ;
     RECT  5.699 44.976 5.929 46.728 ;
     RECT  5.465 26.448 5.965 35.976 ;
     RECT  5.317 51.888 5.977 53.4 ;
     RECT  5.465 36.96 6.145 38.472 ;
     RECT  5.141 39.456 6.145 40.056 ;
     RECT  5.753 41.136 6.217 42.216 ;
     RECT  6.181 13.68 6.265 13.704 ;
     RECT  6.217 41.136 6.284 42.456 ;
     RECT  5.929 43.536 6.284 46.728 ;
     RECT  5.699 47.712 6.325 48.12 ;
     RECT  5.965 25.632 6.433 35.976 ;
     RECT  6.145 36.96 6.433 40.056 ;
     RECT  6.145 51.456 6.461 51.48 ;
     RECT  5.717 15.504 6.469 18.84 ;
     RECT  6.461 50.688 6.469 51.48 ;
     RECT  6.325 47.712 6.505 48.936 ;
     RECT  6.469 49.968 6.505 51.48 ;
     RECT  6.433 25.632 6.509 40.056 ;
     RECT  3.827 22.08 6.545 22.104 ;
     RECT  5.977 52.656 6.565 53.4 ;
     RECT  6.469 15.504 6.649 19.416 ;
     RECT  5.713 2.208 6.757 6.792 ;
     RECT  5.789 8.16 6.757 8.232 ;
     RECT  6.757 2.208 6.805 8.232 ;
     RECT  6.649 15.504 6.829 19.8 ;
     RECT  5.897 9.6 6.937 12.456 ;
     RECT  6.829 15.312 6.973 19.8 ;
     RECT  6.805 2.208 7.117 8.424 ;
     RECT  6.937 9.6 7.117 13.128 ;
     RECT  6.505 47.712 7.153 51.48 ;
     RECT  6.565 52.656 7.153 53.592 ;
     RECT  6.509 25.632 7.261 26.136 ;
     RECT  7.261 25.248 7.297 26.136 ;
     RECT  7.117 2.208 7.333 13.128 ;
     RECT  6.284 41.136 7.429 46.728 ;
     RECT  7.153 47.712 7.429 53.592 ;
     RECT  7.429 41.04 7.58 53.592 ;
     RECT  6.973 14.832 7.669 19.8 ;
     RECT  7.333 22.176 7.693 22.2 ;
     RECT  7.333 2.208 7.808 13.656 ;
     RECT  7.669 14.64 7.808 19.8 ;
     RECT  7.693 22.176 7.808 22.776 ;
     RECT  7.297 24.672 7.808 26.136 ;
     RECT  6.509 27.36 7.808 40.056 ;
     RECT  7.58 41.04 7.808 53.784 ;
     RECT  7.808 2.148 7.912 54.012 ;
     RECT  7.912 2.16 8.104 53.742 ;
     RECT  8.104 27.36 8.165 36.888 ;
     RECT  8.165 27.648 8.597 36.888 ;
     RECT  8.597 27.648 8.908 33.24 ;
     RECT  8.908 27.648 8.993 33.192 ;
     RECT  8.917 0.144 9.029 0.168 ;
     RECT  8.104 39.312 9.065 42.024 ;
     RECT  8.104 22.272 9.157 23.976 ;
     RECT  9.013 55.296 9.157 55.32 ;
     RECT  8.993 27.648 9.173 33.096 ;
     RECT  8.104 2.16 9.244 20.568 ;
     RECT  8.104 25.056 9.277 25.08 ;
     RECT  8.104 26.112 9.277 26.232 ;
     RECT  9.065 39.312 9.281 40.68 ;
     RECT  8.104 43.104 9.349 53.352 ;
     RECT  9.349 43.056 9.385 53.352 ;
     RECT  9.157 54.72 9.385 55.32 ;
     RECT  9.244 2.16 9.421 20.136 ;
     RECT  9.281 39.312 9.421 39.864 ;
     RECT  9.385 43.056 9.521 55.32 ;
     RECT  9.065 41.76 9.529 42.024 ;
     RECT  9.521 43.056 9.529 55.368 ;
     RECT  9.529 41.76 9.605 55.368 ;
     RECT  9.605 41.76 9.635 55.32 ;
     RECT  9.421 38.784 9.641 39.864 ;
     RECT  9.277 25.056 9.673 26.232 ;
     RECT  9.173 27.648 9.673 31.656 ;
     RECT  9.421 1.728 9.683 20.136 ;
     RECT  9.673 25.056 9.683 31.656 ;
     RECT  9.109 0.192 9.685 0.408 ;
     RECT  9.683 1.728 9.685 18.216 ;
     RECT  9.157 21.888 9.713 23.976 ;
     RECT  9.683 26.208 9.713 31.656 ;
     RECT  9.713 22.224 9.74 23.976 ;
     RECT  9.683 25.056 9.74 25.08 ;
     RECT  9.635 54.72 9.779 55.32 ;
     RECT  9.74 22.224 9.821 25.08 ;
     RECT  9.685 0.192 9.923 18.216 ;
     RECT  8.597 34.368 9.925 36.888 ;
     RECT  9.173 32.736 10.079 33.096 ;
     RECT  9.925 34.368 10.079 36.936 ;
     RECT  9.713 26.304 10.165 31.656 ;
     RECT  10.079 32.736 10.165 36.936 ;
     RECT  10.165 26.304 10.211 36.936 ;
     RECT  10.211 33.648 10.249 36.936 ;
     RECT  9.821 22.224 10.259 24.504 ;
     RECT  9.641 39.36 10.325 39.864 ;
     RECT  9.635 41.76 10.396 53.688 ;
     RECT  10.211 26.304 10.433 32.424 ;
     RECT  10.259 24.48 10.691 24.504 ;
     RECT  10.259 22.224 10.924 23.4 ;
     RECT  9.923 0.192 10.933 0.456 ;
     RECT  9.923 1.728 10.933 18.216 ;
     RECT  9.779 55.296 11.005 55.32 ;
     RECT  10.433 26.304 11.036 32.184 ;
     RECT  11.036 25.68 11.077 32.184 ;
     RECT  10.933 0.192 11.081 18.216 ;
     RECT  10.249 33.648 11.173 37.032 ;
     RECT  10.325 39.36 11.185 39.768 ;
     RECT  11.005 54.72 11.225 55.32 ;
     RECT  11.225 54.72 11.315 54.744 ;
     RECT  11.185 38.784 11.317 39.768 ;
     RECT  11.173 33.648 11.393 37.464 ;
     RECT  11.317 38.784 11.393 40.728 ;
     RECT  11.393 33.648 11.405 40.728 ;
     RECT  11.077 24.528 11.413 32.184 ;
     RECT  11.081 0.288 11.429 18.216 ;
     RECT  9.683 19.2 11.429 20.04 ;
     RECT  11.429 0.288 11.461 20.04 ;
     RECT  10.396 41.76 11.461 53.64 ;
     RECT  11.461 0.288 11.507 20.568 ;
     RECT  11.507 18.816 11.513 20.568 ;
     RECT  11.413 24.528 11.555 32.424 ;
     RECT  11.461 41.76 11.581 53.688 ;
     RECT  11.555 32.4 11.585 32.424 ;
     RECT  10.924 22.224 11.617 22.776 ;
     RECT  11.581 41.76 11.689 54.168 ;
     RECT  11.689 41.712 11.747 54.168 ;
     RECT  11.747 41.712 11.756 53.688 ;
     RECT  11.555 24.528 11.797 31.416 ;
     RECT  11.617 22.032 11.837 22.776 ;
     RECT  11.797 24.48 11.845 31.416 ;
     RECT  11.756 40.8 11.873 53.688 ;
     RECT  11.405 33.648 11.893 39.768 ;
     RECT  11.893 33.6 11.9 39.768 ;
     RECT  11.513 19.392 11.945 20.568 ;
     RECT  11.9 32.928 11.987 39.768 ;
     RECT  11.845 23.952 12.017 31.416 ;
     RECT  11.987 33.6 12.053 39.768 ;
     RECT  12.017 24.672 12.083 31.416 ;
     RECT  11.507 0.288 12.149 17.64 ;
     RECT  12.149 0.192 12.233 17.64 ;
     RECT  11.837 22.032 12.236 22.056 ;
     RECT  12.053 33.648 12.437 39.768 ;
     RECT  11.873 40.8 12.437 53.64 ;
     RECT  12.233 0.288 12.589 17.64 ;
     RECT  12.589 0.288 12.625 17.688 ;
     RECT  12.613 55.296 12.661 55.32 ;
     RECT  12.625 0.288 12.709 18.36 ;
     RECT  11.945 19.392 12.709 20.184 ;
     RECT  12.661 54.72 12.757 55.32 ;
     RECT  12.757 54.72 12.881 55.368 ;
     RECT  12.709 0.288 12.899 20.184 ;
     RECT  12.437 33.648 12.901 53.64 ;
     RECT  12.881 54.72 13.091 55.32 ;
     RECT  12.901 33.648 13.093 53.736 ;
     RECT  12.899 1.728 13.208 20.184 ;
     RECT  12.236 21.648 13.208 22.056 ;
     RECT  12.949 23.664 13.208 23.688 ;
     RECT  12.083 24.672 13.208 31.32 ;
     RECT  13.093 33.648 13.208 54.168 ;
     RECT  13.208 1.728 13.504 54.168 ;
     RECT  13.504 1.728 13.565 31.368 ;
     RECT  13.565 22.752 13.619 31.368 ;
     RECT  13.091 55.296 13.619 55.32 ;
     RECT  13.504 34.368 13.667 54.168 ;
     RECT  12.899 0.288 13.877 0.552 ;
     RECT  13.877 0.192 13.906 0.552 ;
     RECT  13.619 22.8 14.041 31.368 ;
     RECT  13.906 0.192 14.429 0.6 ;
     RECT  13.667 34.368 14.537 53.64 ;
     RECT  14.429 0.288 14.629 0.6 ;
     RECT  13.565 1.728 14.629 21.672 ;
     RECT  13.504 32.976 14.705 33.048 ;
     RECT  14.041 23.568 14.725 31.368 ;
     RECT  14.725 23.568 14.749 31.848 ;
     RECT  14.629 0.288 14.867 21.672 ;
     RECT  14.867 0.336 14.897 21.672 ;
     RECT  14.897 0.336 14.933 21.144 ;
     RECT  14.749 23.568 15.037 31.944 ;
     RECT  14.705 32.976 15.037 33.384 ;
     RECT  14.933 0.432 15.221 21.144 ;
     RECT  15.037 23.568 15.301 33.384 ;
     RECT  14.537 34.368 15.301 53.592 ;
     RECT  15.361 54.72 15.613 54.744 ;
     RECT  15.301 23.568 15.637 53.592 ;
     RECT  15.637 23.568 15.829 53.64 ;
     RECT  15.829 23.328 15.925 53.64 ;
     RECT  15.613 54.72 15.925 55.32 ;
     RECT  15.925 23.328 15.937 55.32 ;
     RECT  15.221 0.432 15.973 17.736 ;
     RECT  15.937 23.28 16.028 55.32 ;
     RECT  16.028 22.752 16.045 55.32 ;
     RECT  15.973 0.288 16.225 17.736 ;
     RECT  16.045 22.752 16.259 55.368 ;
     RECT  15.221 18.768 16.316 21.144 ;
     RECT  16.259 22.752 16.373 31.896 ;
     RECT  16.225 0.192 16.549 17.736 ;
     RECT  16.316 18.768 16.549 21.384 ;
     RECT  16.373 22.752 16.553 31.416 ;
     RECT  16.549 0.192 16.585 21.384 ;
     RECT  16.553 22.752 16.585 30.264 ;
     RECT  16.259 33.024 16.633 55.368 ;
     RECT  16.585 0.192 16.732 30.264 ;
     RECT  16.633 39.36 16.805 55.368 ;
     RECT  16.805 55.296 16.837 55.368 ;
     RECT  16.732 0.192 16.841 25.08 ;
     RECT  16.841 0.192 17.057 25.032 ;
     RECT  16.837 55.296 17.077 55.512 ;
     RECT  17.057 0.192 17.123 16.104 ;
     RECT  17.077 55.296 17.219 55.896 ;
     RECT  17.219 55.296 17.267 55.512 ;
     RECT  16.732 26.112 17.308 30.264 ;
     RECT  16.553 31.344 17.309 31.416 ;
     RECT  17.057 17.088 17.345 17.16 ;
     RECT  17.345 17.136 17.597 17.16 ;
     RECT  16.805 39.36 17.597 54.168 ;
     RECT  16.633 33.024 17.603 38.232 ;
     RECT  17.603 34.752 17.845 38.232 ;
     RECT  17.597 39.36 17.845 54.12 ;
     RECT  17.665 31.92 17.881 31.944 ;
     RECT  17.603 33.024 17.881 33.048 ;
     RECT  17.123 0.192 18.349 0.552 ;
     RECT  17.123 1.728 18.608 16.104 ;
     RECT  17.057 18.192 18.608 25.032 ;
     RECT  17.308 26.112 18.608 29.64 ;
     RECT  18.469 30.672 18.608 30.696 ;
     RECT  17.881 31.92 18.608 33.048 ;
     RECT  17.845 34.752 18.608 54.12 ;
     RECT  18.608 1.728 18.661 54.12 ;
     RECT  17.267 55.296 18.851 55.416 ;
     RECT  18.661 1.728 18.904 54.168 ;
     RECT  18.904 22.56 18.929 23.304 ;
     RECT  18.904 21.504 19.073 21.528 ;
     RECT  18.904 33.024 19.093 54.168 ;
     RECT  18.904 26.112 19.181 29.304 ;
     RECT  19.093 33.024 19.325 54.216 ;
     RECT  19.325 33.84 19.427 54.216 ;
     RECT  19.181 26.112 19.433 29.256 ;
     RECT  18.349 0.144 19.475 0.552 ;
     RECT  19.427 34.176 19.525 54.216 ;
     RECT  18.851 55.296 19.525 55.32 ;
     RECT  18.929 22.752 19.613 23.304 ;
     RECT  19.525 34.176 19.685 55.32 ;
     RECT  19.685 34.512 19.9 55.32 ;
     RECT  18.904 24.672 19.925 25.032 ;
     RECT  18.904 30.864 19.969 31.896 ;
     RECT  18.904 1.728 19.973 19.464 ;
     RECT  19.433 26.208 20.003 29.256 ;
     RECT  19.925 24.672 20.197 25.08 ;
     RECT  19.613 23.28 20.225 23.304 ;
     RECT  19.969 30.816 20.225 31.896 ;
     RECT  20.003 26.784 20.389 29.256 ;
     RECT  20.197 24.672 20.473 25.176 ;
     RECT  19.9 34.512 20.477 54.168 ;
     RECT  20.473 23.952 20.485 25.176 ;
     RECT  19.9 55.296 20.533 55.32 ;
     RECT  20.485 23.952 20.549 25.752 ;
     RECT  20.533 55.296 20.581 55.368 ;
     RECT  20.389 26.784 20.617 29.64 ;
     RECT  20.225 30.816 20.617 31.848 ;
     RECT  20.549 24.96 20.621 25.752 ;
     RECT  20.617 26.784 20.621 31.848 ;
     RECT  20.581 55.296 20.867 55.464 ;
     RECT  19.475 0.192 20.869 0.552 ;
     RECT  19.973 1.728 21.025 19.416 ;
     RECT  21.025 1.728 21.125 19.368 ;
     RECT  20.185 22.032 21.125 22.056 ;
     RECT  21.125 1.728 21.197 17.688 ;
     RECT  20.549 23.952 21.197 23.976 ;
     RECT  21.197 15.792 21.203 17.688 ;
     RECT  20.477 34.512 21.244 53.592 ;
     RECT  20.867 55.296 21.253 55.368 ;
     RECT  20.869 0.192 21.301 0.6 ;
     RECT  21.197 1.728 21.301 14.376 ;
     RECT  20.621 25.008 21.337 25.752 ;
     RECT  20.621 26.784 21.337 31.128 ;
     RECT  21.301 0.192 21.373 14.376 ;
     RECT  20.365 20.592 21.449 20.616 ;
     RECT  21.125 18.768 21.593 19.368 ;
     RECT  21.244 35.328 21.625 53.592 ;
     RECT  21.253 54.72 21.625 55.368 ;
     RECT  21.337 25.008 21.665 31.128 ;
     RECT  21.665 30.864 21.731 31.128 ;
     RECT  21.625 35.328 21.731 55.368 ;
     RECT  21.685 33.936 21.877 33.96 ;
     RECT  21.877 33.408 21.917 33.96 ;
     RECT  21.925 32.16 22.012 32.184 ;
     RECT  21.373 0.144 22.025 14.376 ;
     RECT  21.625 22.752 22.057 22.776 ;
     RECT  21.731 35.52 22.067 55.368 ;
     RECT  21.203 15.84 22.165 17.688 ;
     RECT  22.021 23.808 22.165 23.832 ;
     RECT  21.665 25.008 22.165 29.64 ;
     RECT  21.731 30.864 22.205 30.888 ;
     RECT  22.165 15.744 22.211 17.688 ;
     RECT  22.211 17.04 22.213 17.688 ;
     RECT  21.593 18.768 22.213 19.08 ;
     RECT  22.213 17.04 22.259 19.08 ;
     RECT  22.259 17.04 22.307 18.888 ;
     RECT  21.949 21.648 22.46 21.672 ;
     RECT  22.46 20.736 22.547 21.672 ;
     RECT  22.547 21.408 22.597 21.672 ;
     RECT  22.057 22.752 22.597 22.824 ;
     RECT  22.025 0.192 22.693 14.376 ;
     RECT  22.211 15.744 22.693 16.008 ;
     RECT  22.693 0.192 22.787 16.008 ;
     RECT  22.067 35.52 22.813 54.792 ;
     RECT  22.733 30.672 22.889 30.792 ;
     RECT  22.597 21.408 22.957 22.824 ;
     RECT  22.165 23.808 22.957 29.64 ;
     RECT  22.813 34.992 23.033 54.792 ;
     RECT  23.033 39.312 23.212 54.792 ;
     RECT  22.307 17.808 23.281 18.888 ;
     RECT  22.777 19.968 23.281 19.992 ;
     RECT  22.957 21.408 23.317 29.64 ;
     RECT  23.245 55.296 23.413 55.32 ;
     RECT  22.787 1.728 23.497 16.008 ;
     RECT  23.281 17.808 23.497 19.992 ;
     RECT  22.787 0.192 23.603 0.6 ;
     RECT  21.917 33.408 23.605 33.432 ;
     RECT  23.033 34.992 23.605 38.28 ;
     RECT  23.497 1.728 23.641 19.992 ;
     RECT  23.317 21.408 23.852 30.12 ;
     RECT  23.413 55.296 23.861 55.368 ;
     RECT  23.852 21.408 23.893 30.504 ;
     RECT  23.893 21.408 23.965 31.416 ;
     RECT  23.641 1.728 24.008 20.28 ;
     RECT  23.965 21.408 24.008 31.512 ;
     RECT  23.605 33.024 24.008 38.28 ;
     RECT  23.212 39.312 24.008 54.216 ;
     RECT  24.008 1.728 24.304 54.216 ;
     RECT  24.304 31.392 24.419 31.512 ;
     RECT  23.861 55.296 24.515 55.32 ;
     RECT  24.419 31.392 24.581 31.416 ;
     RECT  23.603 0.192 24.661 0.552 ;
     RECT  24.304 1.728 24.661 30.408 ;
     RECT  24.304 33.024 24.707 54.216 ;
     RECT  24.661 0.192 24.803 30.408 ;
     RECT  24.803 0.192 24.905 0.552 ;
     RECT  24.803 1.728 25.049 30.408 ;
     RECT  25.049 1.728 25.091 27.336 ;
     RECT  24.707 33.024 25.139 53.832 ;
     RECT  25.091 1.728 25.337 26.28 ;
     RECT  25.139 33.024 25.436 53.592 ;
     RECT  24.905 0.288 25.475 0.552 ;
     RECT  25.388 31.536 25.475 31.56 ;
     RECT  25.049 28.32 25.861 30.408 ;
     RECT  25.436 32.928 25.907 53.592 ;
     RECT  25.907 32.928 26.053 48.696 ;
     RECT  25.475 0.288 26.089 0.456 ;
     RECT  25.907 50.016 26.129 53.592 ;
     RECT  25.091 27.264 26.204 27.336 ;
     RECT  25.861 28.32 26.204 30.84 ;
     RECT  26.089 0.192 26.485 0.456 ;
     RECT  25.337 2.208 26.629 26.28 ;
     RECT  26.204 27.264 26.629 30.84 ;
     RECT  26.629 2.112 26.677 30.84 ;
     RECT  26.485 0.192 26.705 0.552 ;
     RECT  26.053 32.496 26.777 48.696 ;
     RECT  26.677 1.728 26.917 31.368 ;
     RECT  26.777 32.496 26.917 44.472 ;
     RECT  26.777 45.552 26.953 48.696 ;
     RECT  26.129 50.016 26.953 53.4 ;
     RECT  26.705 0.192 27.209 0.504 ;
     RECT  26.953 45.552 27.308 53.4 ;
     RECT  26.917 1.728 27.325 44.472 ;
     RECT  27.209 0.288 27.347 0.504 ;
     RECT  27.308 45.552 27.388 53.544 ;
     RECT  27.347 0.288 27.389 0.312 ;
     RECT  27.325 1.824 27.533 44.472 ;
     RECT  27.533 2.112 27.893 44.472 ;
     RECT  27.893 38.64 27.965 44.472 ;
     RECT  27.893 2.112 28.037 37.56 ;
     RECT  28.037 2.208 28.253 37.56 ;
     RECT  28.253 36.48 28.361 37.56 ;
     RECT  27.388 45.792 28.429 53.544 ;
     RECT  27.965 44.112 28.537 44.472 ;
     RECT  28.429 45.696 28.537 53.544 ;
     RECT  28.361 36.912 28.897 37.56 ;
     RECT  27.965 38.64 28.897 43.08 ;
     RECT  28.897 36.912 28.969 43.08 ;
     RECT  28.537 44.112 28.969 53.544 ;
     RECT  28.253 2.208 29.221 35.496 ;
     RECT  29.221 2.208 29.408 35.736 ;
     RECT  28.969 36.912 29.408 53.544 ;
     RECT  29.408 2.148 29.512 54.012 ;
     RECT  29.512 2.256 29.704 53.742 ;
     RECT  29.704 2.256 30.035 25.32 ;
     RECT  29.704 27.744 30.305 32.904 ;
     RECT  30.305 29.472 30.593 32.904 ;
     RECT  30.035 10.8 30.665 25.32 ;
     RECT  30.593 30.816 30.709 32.904 ;
     RECT  30.305 27.744 30.773 28.248 ;
     RECT  29.704 26.64 30.805 26.664 ;
     RECT  29.704 36.912 30.809 53.4 ;
     RECT  30.035 2.256 30.853 9.624 ;
     RECT  30.773 28.224 30.881 28.248 ;
     RECT  30.805 26.352 30.908 26.664 ;
     RECT  29.704 34.224 30.908 35.832 ;
     RECT  30.809 36.912 30.908 53.304 ;
     RECT  30.665 10.8 30.953 22.824 ;
     RECT  30.665 23.904 30.985 25.32 ;
     RECT  30.908 26.352 30.985 27.144 ;
     RECT  30.709 30.816 31.129 33.096 ;
     RECT  30.908 34.224 31.129 53.304 ;
     RECT  30.593 29.472 31.133 29.64 ;
     RECT  31.129 30.816 31.133 53.304 ;
     RECT  31.133 30.816 31.205 50.952 ;
     RECT  30.853 2.208 31.237 9.624 ;
     RECT  30.953 10.8 31.237 21.144 ;
     RECT  31.205 30.816 31.321 33.672 ;
     RECT  31.133 29.616 31.597 29.64 ;
     RECT  31.205 34.8 31.601 50.952 ;
     RECT  30.953 22.176 31.676 22.824 ;
     RECT  30.985 23.904 31.676 27.144 ;
     RECT  31.676 22.176 31.763 27.144 ;
     RECT  31.763 23.904 31.777 27.144 ;
     RECT  31.237 2.16 31.853 21.144 ;
     RECT  31.853 2.208 31.907 19.128 ;
     RECT  31.321 31.92 31.907 33.672 ;
     RECT  31.597 29.616 31.925 30.408 ;
     RECT  31.763 22.176 31.933 22.824 ;
     RECT  31.907 2.208 31.961 13.656 ;
     RECT  31.907 15.072 31.961 19.128 ;
     RECT  31.669 28.464 32.033 28.584 ;
     RECT  31.925 29.616 32.101 30.264 ;
     RECT  31.961 2.208 32.105 13.512 ;
     RECT  31.961 15.072 32.147 17.112 ;
     RECT  31.133 52.416 32.209 53.304 ;
     RECT  31.777 23.904 32.285 27.384 ;
     RECT  31.907 31.92 32.285 33.48 ;
     RECT  32.105 2.208 32.291 13.464 ;
     RECT  32.291 2.208 32.387 8.04 ;
     RECT  32.285 27.36 32.389 27.384 ;
     RECT  32.285 23.904 32.435 26.328 ;
     RECT  32.291 9.024 32.465 13.464 ;
     RECT  31.601 34.896 32.485 50.952 ;
     RECT  32.209 52.032 32.485 53.304 ;
     RECT  32.485 34.896 32.537 53.304 ;
     RECT  32.389 27.36 32.573 27.864 ;
     RECT  32.147 15.408 32.717 17.112 ;
     RECT  32.573 27.648 32.753 27.864 ;
     RECT  32.717 17.088 32.789 17.112 ;
     RECT  32.101 29.568 32.857 30.264 ;
     RECT  32.717 15.408 32.869 16.008 ;
     RECT  32.285 32.928 33.013 33.48 ;
     RECT  32.537 34.896 33.013 46.152 ;
     RECT  31.933 22.176 33.037 22.2 ;
     RECT  32.387 2.208 33.059 7.992 ;
     RECT  31.961 18.72 33.109 19.128 ;
     RECT  32.465 9.072 33.113 13.464 ;
     RECT  32.537 47.28 33.251 53.304 ;
     RECT  33.113 12.528 33.253 13.464 ;
     RECT  33.113 9.072 33.257 11.544 ;
     RECT  33.037 22.176 33.257 22.776 ;
     RECT  33.013 32.928 33.257 46.152 ;
     RECT  32.435 24.48 33.299 26.328 ;
     RECT  33.299 26.304 33.365 26.328 ;
     RECT  33.109 31.536 33.445 31.56 ;
     RECT  33.257 32.928 33.445 45.72 ;
     RECT  33.059 2.208 33.473 6.36 ;
     RECT  33.251 50.016 33.505 53.304 ;
     RECT  31.853 20.304 33.541 21.144 ;
     RECT  33.257 22.176 33.541 22.488 ;
     RECT  33.541 20.304 33.589 22.488 ;
     RECT  33.251 47.28 33.625 48.984 ;
     RECT  32.857 28.944 33.649 30.264 ;
     RECT  33.109 18.48 33.661 19.128 ;
     RECT  33.473 2.256 33.689 6.312 ;
     RECT  33.059 7.392 33.689 7.992 ;
     RECT  33.257 9.504 33.689 11.544 ;
     RECT  33.253 12.528 33.689 13.704 ;
     RECT  33.299 24.48 33.725 25.08 ;
     RECT  33.649 28.944 33.725 30.36 ;
     RECT  32.869 15.84 33.973 16.008 ;
     RECT  33.725 29.28 33.973 30.36 ;
     RECT  33.445 31.536 33.973 45.72 ;
     RECT  33.689 12.912 34.213 13.704 ;
     RECT  33.625 47.664 34.261 48.984 ;
     RECT  33.505 50.016 34.261 53.4 ;
     RECT  33.689 9.504 34.441 11.256 ;
     RECT  32.753 27.648 34.513 27.72 ;
     RECT  33.589 20.256 34.585 22.488 ;
     RECT  34.081 26.592 34.604 26.616 ;
     RECT  34.513 27.648 34.604 28.008 ;
     RECT  34.441 9.36 34.657 11.256 ;
     RECT  34.604 26.592 34.693 28.008 ;
     RECT  33.973 29.28 34.693 45.72 ;
     RECT  34.213 12.912 34.729 14.28 ;
     RECT  33.689 7.392 34.801 7.416 ;
     RECT  34.657 8.832 34.801 11.256 ;
     RECT  34.693 26.592 34.801 45.72 ;
     RECT  33.689 2.736 34.808 6.312 ;
     RECT  34.801 7.392 34.808 11.256 ;
     RECT  34.729 12.912 34.808 14.664 ;
     RECT  33.973 15.84 34.808 16.104 ;
     RECT  34.765 17.088 34.808 17.112 ;
     RECT  33.661 18.48 34.808 18.504 ;
     RECT  34.585 20.256 34.808 22.776 ;
     RECT  33.725 24.528 34.808 25.08 ;
     RECT  34.801 26.592 34.808 46.536 ;
     RECT  34.261 47.664 34.808 53.4 ;
     RECT  34.808 2.148 34.912 54.012 ;
     RECT  34.912 2.418 35.104 53.742 ;
     RECT  35.104 27.648 35.129 33.384 ;
     RECT  35.104 5.184 35.165 5.208 ;
     RECT  35.104 34.752 35.165 39.192 ;
     RECT  35.104 3.072 35.201 3.96 ;
     RECT  35.129 31.92 35.219 33.384 ;
     RECT  35.104 40.656 35.219 53.592 ;
     RECT  35.104 7.392 35.381 11.16 ;
     RECT  35.219 45.168 35.381 45.768 ;
     RECT  35.219 31.92 35.453 32.808 ;
     RECT  35.104 18.096 35.459 18.408 ;
     RECT  35.453 32.784 35.489 32.808 ;
     RECT  35.381 7.392 35.597 7.416 ;
     RECT  35.219 47.328 35.597 53.592 ;
     RECT  35.129 27.648 35.603 30.936 ;
     RECT  35.219 43.824 35.633 44.088 ;
     RECT  35.381 9.36 35.705 11.16 ;
     RECT  35.705 9.6 35.932 11.16 ;
     RECT  35.165 34.752 35.957 36.984 ;
     RECT  35.201 3.408 35.993 3.96 ;
     RECT  35.597 47.376 36.065 53.592 ;
     RECT  35.932 9.6 36.179 10.056 ;
     RECT  35.104 13.056 36.181 17.112 ;
     RECT  35.459 18.384 36.205 18.408 ;
     RECT  35.957 34.752 36.205 35.496 ;
     RECT  35.993 3.408 36.277 3.432 ;
     RECT  35.932 11.136 36.349 11.16 ;
     RECT  35.104 23.328 36.469 23.352 ;
     RECT  35.603 27.648 36.493 29.208 ;
     RECT  36.493 26.88 36.515 29.208 ;
     RECT  36.181 14.64 36.529 17.112 ;
     RECT  36.205 18.384 36.529 19.08 ;
     RECT  36.241 33.024 36.533 33.048 ;
     RECT  35.957 36.96 36.533 36.984 ;
     RECT  36.529 14.64 36.563 19.08 ;
     RECT  35.165 38.016 36.565 39.192 ;
     RECT  36.277 3.072 36.605 3.432 ;
     RECT  36.565 37.632 36.613 39.192 ;
     RECT  36.613 37.632 36.7 39.432 ;
     RECT  36.469 23.328 36.745 23.928 ;
     RECT  36.065 47.664 36.749 53.592 ;
     RECT  36.745 23.28 36.781 23.928 ;
     RECT  36.515 26.88 36.781 28.488 ;
     RECT  36.781 26.304 36.785 28.488 ;
     RECT  36.781 22.848 36.817 23.928 ;
     RECT  36.241 25.296 36.817 25.32 ;
     RECT  36.179 9.936 36.925 10.056 ;
     RECT  36.817 22.848 36.961 25.32 ;
     RECT  36.785 26.304 36.961 28.344 ;
     RECT  36.181 13.056 36.997 13.368 ;
     RECT  35.633 44.064 37.033 44.088 ;
     RECT  35.381 45.552 37.033 45.768 ;
     RECT  35.603 30.816 37.043 30.936 ;
     RECT  36.749 47.664 37.069 51.384 ;
     RECT  36.563 14.784 37.073 19.08 ;
     RECT  37.069 47.28 37.073 51.384 ;
     RECT  37.033 44.064 37.091 45.768 ;
     RECT  37.073 49.92 37.145 51.384 ;
     RECT  36.925 9.936 37.177 10.152 ;
     RECT  35.219 40.656 37.177 42.744 ;
     RECT  36.961 22.848 37.189 28.344 ;
     RECT  37.145 49.92 37.217 50.856 ;
     RECT  37.073 47.28 37.285 48.936 ;
     RECT  37.177 9.072 37.313 10.152 ;
     RECT  36.349 11.136 37.313 11.4 ;
     RECT  37.073 14.784 37.331 18.648 ;
     RECT  37.177 40.176 37.357 42.744 ;
     RECT  37.091 44.064 37.357 45.576 ;
     RECT  37.285 6.144 37.393 6.168 ;
     RECT  36.997 13.008 37.429 13.368 ;
     RECT  37.393 6.144 37.465 7.032 ;
     RECT  36.997 8.016 37.465 8.04 ;
     RECT  37.189 22.176 37.465 28.344 ;
     RECT  37.331 14.784 37.541 18.456 ;
     RECT  36.205 34.608 37.58 35.496 ;
     RECT  37.58 34.608 37.581 35.88 ;
     RECT  35.104 20.304 37.609 20.328 ;
     RECT  37.429 12.384 37.619 13.368 ;
     RECT  37.043 30.816 37.621 30.84 ;
     RECT  37.465 21.456 37.667 28.344 ;
     RECT  37.581 34.608 37.667 36.648 ;
     RECT  37.619 12.528 37.681 13.368 ;
     RECT  37.681 12.528 37.717 13.464 ;
     RECT  36.749 52.368 37.721 53.592 ;
     RECT  37.465 6.144 37.753 8.04 ;
     RECT  37.621 30.72 37.763 30.84 ;
     RECT  37.357 40.176 37.793 45.576 ;
     RECT  37.721 52.368 37.901 53.208 ;
     RECT  37.717 12.528 37.937 13.608 ;
     RECT  37.753 5.856 37.957 8.04 ;
     RECT  37.793 40.176 37.973 44.088 ;
     RECT  37.217 49.92 38.003 50.712 ;
     RECT  37.901 52.944 38.003 53.208 ;
     RECT  37.763 30.816 38.005 30.84 ;
     RECT  37.667 25.152 38.009 28.344 ;
     RECT  38.003 52.944 38.009 53.064 ;
     RECT  37.957 5.04 38.044 8.04 ;
     RECT  37.667 21.456 38.045 23.928 ;
     RECT  36.7 37.632 38.081 39.192 ;
     RECT  38.005 30.816 38.099 30.936 ;
     RECT  38.081 37.824 38.101 39.192 ;
     RECT  37.973 40.176 38.101 41.112 ;
     RECT  38.044 5.232 38.149 8.04 ;
     RECT  37.313 9.072 38.149 11.4 ;
     RECT  37.667 34.608 38.149 35.352 ;
     RECT  38.045 22.224 38.153 23.928 ;
     RECT  38.077 32.496 38.161 32.52 ;
     RECT  38.149 5.232 38.189 11.4 ;
     RECT  37.793 45.072 38.261 45.576 ;
     RECT  36.605 3.408 38.293 3.432 ;
     RECT  38.189 6.24 38.297 11.4 ;
     RECT  38.293 3.408 38.377 3.96 ;
     RECT  37.937 13.584 38.437 13.608 ;
     RECT  37.541 14.784 38.437 16.632 ;
     RECT  37.285 46.752 38.437 48.936 ;
     RECT  38.003 49.92 38.437 50.136 ;
     RECT  38.009 25.152 38.441 28.296 ;
     RECT  38.297 6.24 38.477 8.232 ;
     RECT  38.437 46.752 38.477 50.136 ;
     RECT  38.477 46.752 38.485 46.824 ;
     RECT  38.297 9.792 38.513 10.44 ;
     RECT  38.189 5.232 38.549 5.256 ;
     RECT  37.609 19.92 38.581 20.328 ;
     RECT  38.441 25.536 38.621 28.296 ;
     RECT  38.149 34.08 38.653 35.352 ;
     RECT  38.437 13.584 38.657 16.632 ;
     RECT  38.009 53.04 38.657 53.064 ;
     RECT  38.621 25.536 38.765 27.336 ;
     RECT  38.477 6.24 38.801 7.992 ;
     RECT  38.657 14.208 38.801 16.632 ;
     RECT  38.653 34.08 38.828 35.64 ;
     RECT  37.667 36.624 38.828 36.648 ;
     RECT  38.153 22.752 38.833 23.928 ;
     RECT  38.801 15.6 38.837 16.632 ;
     RECT  37.541 17.616 38.837 18.456 ;
     RECT  38.837 18.048 38.869 18.456 ;
     RECT  38.581 19.632 38.869 20.328 ;
     RECT  38.837 15.6 38.909 15.624 ;
     RECT  38.485 46.752 39.011 46.776 ;
     RECT  38.833 22.752 39.053 23.976 ;
     RECT  38.765 26.256 39.089 27.336 ;
     RECT  38.828 34.08 39.121 36.648 ;
     RECT  38.101 37.824 39.121 41.112 ;
     RECT  38.377 3.408 39.125 3.432 ;
     RECT  38.477 47.904 39.157 50.136 ;
     RECT  38.801 6.816 39.161 7.992 ;
     RECT  38.513 9.792 39.161 10.056 ;
     RECT  38.869 18.048 39.161 20.328 ;
     RECT  37.937 12.528 39.193 12.552 ;
     RECT  39.013 29.76 39.193 29.784 ;
     RECT  38.099 30.816 39.193 30.84 ;
     RECT  39.089 26.256 39.203 26.808 ;
     RECT  39.161 19.344 39.205 20.328 ;
     RECT  39.053 22.752 39.229 22.92 ;
     RECT  39.193 28.464 39.301 28.488 ;
     RECT  39.193 29.76 39.301 30.84 ;
     RECT  39.205 19.344 39.337 21.048 ;
     RECT  39.229 22.224 39.337 22.92 ;
     RECT  39.193 11.952 39.349 12.552 ;
     RECT  39.157 47.904 39.553 50.184 ;
     RECT  39.301 28.464 39.925 30.84 ;
     RECT  39.301 31.824 39.925 31.848 ;
     RECT  37.973 42.096 39.925 44.088 ;
     RECT  38.261 45.12 39.925 45.576 ;
     RECT  39.301 33.072 39.98 33.096 ;
     RECT  39.925 28.464 40.021 31.848 ;
     RECT  39.98 33.024 40.021 33.096 ;
     RECT  39.121 34.08 40.021 41.112 ;
     RECT  39.161 6.816 40.208 6.84 ;
     RECT  39.161 7.968 40.208 7.992 ;
     RECT  39.161 10.032 40.208 10.056 ;
     RECT  39.349 11.952 40.208 13.128 ;
     RECT  38.801 14.208 40.208 14.232 ;
     RECT  38.837 16.608 40.208 16.632 ;
     RECT  39.161 18.048 40.208 18.072 ;
     RECT  39.337 19.344 40.208 22.92 ;
     RECT  39.053 23.952 40.208 23.976 ;
     RECT  39.661 25.104 40.208 25.128 ;
     RECT  39.203 26.784 40.208 26.808 ;
     RECT  40.021 28.464 40.208 41.112 ;
     RECT  39.925 42.096 40.208 45.576 ;
     RECT  39.553 47.904 40.208 50.76 ;
     RECT  40.208 2.148 40.312 54.012 ;
     RECT  40.312 2.418 40.504 53.742 ;
     RECT  40.504 36.816 40.529 37.608 ;
     RECT  40.504 38.688 40.565 39.864 ;
     RECT  40.504 34.08 40.637 34.104 ;
     RECT  40.504 44.352 40.643 44.472 ;
     RECT  40.504 47.904 40.643 47.928 ;
     RECT  40.504 31.776 40.709 31.8 ;
     RECT  40.643 44.448 40.709 44.472 ;
     RECT  40.504 29.616 40.817 29.64 ;
     RECT  40.529 37.44 40.817 37.608 ;
     RECT  40.565 38.688 40.889 39.336 ;
     RECT  40.817 37.44 40.925 37.464 ;
     RECT  40.889 39.312 40.961 39.336 ;
    LAYER M5 ;
     RECT  8.928 0.133 8.952 0.144 ;
     RECT  19.44 0.133 19.464 0.144 ;
     RECT  7.8 2.137 7.92 2.149 ;
     RECT  8.928 0.144 27.336 2.149 ;
     RECT  2.4 2.137 2.52 2.151 ;
     RECT  29.4 2.137 29.52 2.151 ;
     RECT  34.8 2.137 34.92 2.151 ;
     RECT  40.2 2.137 40.32 2.151 ;
     RECT  7.8 2.149 27.336 2.197 ;
     RECT  31.248 2.149 31.8 2.197 ;
     RECT  7.8 2.197 27.576 2.245 ;
     RECT  29.4 2.151 29.712 2.245 ;
     RECT  30.864 2.197 32.472 2.245 ;
     RECT  29.4 2.245 32.808 2.533 ;
     RECT  7.392 2.245 27.768 2.581 ;
     RECT  6.864 2.581 27.768 2.677 ;
     RECT  29.232 2.533 32.808 2.677 ;
     RECT  6.864 2.677 32.808 2.725 ;
     RECT  2.4 2.151 2.712 2.773 ;
     RECT  6.864 2.725 33.624 2.773 ;
     RECT  34.8 2.151 35.112 2.773 ;
     RECT  6.864 2.773 35.112 2.821 ;
     RECT  6.816 2.821 35.112 2.869 ;
     RECT  2.304 2.773 2.712 2.917 ;
     RECT  6.192 2.869 35.112 3.107 ;
     RECT  2.304 2.917 2.856 3.109 ;
     RECT  2.304 3.109 3.192 3.301 ;
     RECT  2.304 3.301 3.432 4.163 ;
     RECT  2.4 4.163 3.432 4.501 ;
     RECT  6.24 3.107 35.112 4.691 ;
     RECT  38.304 3.925 38.328 5.029 ;
     RECT  2.4 4.501 3.48 5.077 ;
     RECT  2.4 5.077 4.104 5.557 ;
     RECT  7.104 4.691 35.112 5.747 ;
     RECT  34.128 5.747 35.112 5.843 ;
     RECT  37.968 5.029 38.328 6.133 ;
     RECT  7.104 5.747 33.048 6.757 ;
     RECT  37.584 6.133 38.328 6.899 ;
     RECT  34.8 5.843 35.112 7.381 ;
     RECT  2.4 5.557 4.584 7.475 ;
     RECT  2.4 7.475 3.864 7.763 ;
     RECT  6.816 6.757 33.048 7.765 ;
     RECT  34.8 7.381 35.352 8.291 ;
     RECT  6.816 7.765 33.384 8.435 ;
     RECT  38.304 6.899 38.328 9.925 ;
     RECT  2.4 7.763 3.192 10.021 ;
     RECT  38.304 9.925 38.76 10.021 ;
     RECT  37.344 10.021 38.76 10.067 ;
     RECT  2.4 10.021 3.24 10.069 ;
     RECT  5.28 8.197 5.304 10.069 ;
     RECT  34.8 8.291 35.112 10.741 ;
     RECT  36.144 9.589 36.168 10.741 ;
     RECT  37.344 10.067 38.136 10.883 ;
     RECT  2.4 10.069 5.304 10.981 ;
     RECT  6.912 8.435 33.384 10.981 ;
     RECT  34.8 10.741 36.168 11.171 ;
     RECT  2.4 10.981 33.384 11.315 ;
     RECT  40.2 2.151 40.512 11.941 ;
     RECT  2.4 11.315 33.288 12.229 ;
     RECT  38.064 10.883 38.136 12.373 ;
     RECT  37.584 12.373 38.136 12.517 ;
     RECT  39.216 11.941 40.512 12.517 ;
     RECT  2.304 12.229 33.288 12.611 ;
     RECT  6.144 12.611 33.288 12.901 ;
     RECT  34.8 11.171 35.112 12.901 ;
     RECT  2.304 12.611 4.968 13.427 ;
     RECT  6.144 12.901 35.112 13.715 ;
     RECT  36.144 11.171 36.168 13.715 ;
     RECT  34.224 13.715 35.112 14.291 ;
     RECT  6.144 13.715 32.856 14.339 ;
     RECT  22.416 14.339 32.856 14.387 ;
     RECT  6.144 14.339 21.432 14.675 ;
     RECT  2.4 13.427 4.968 14.725 ;
     RECT  36.528 14.629 36.552 14.773 ;
     RECT  37.584 12.517 40.512 14.773 ;
     RECT  34.8 14.291 35.112 15.397 ;
     RECT  36.528 14.773 40.512 15.397 ;
     RECT  22.608 14.387 32.856 15.443 ;
     RECT  6.144 14.675 18.912 15.539 ;
     RECT  19.968 14.675 21.432 15.733 ;
     RECT  22.608 15.443 32.616 15.733 ;
     RECT  6.144 15.539 17.544 15.827 ;
     RECT  34.8 15.397 40.512 15.875 ;
     RECT  19.968 15.733 32.616 15.971 ;
     RECT  20.112 15.971 32.616 16.019 ;
     RECT  36.528 15.875 40.512 16.019 ;
     RECT  2.304 14.725 4.968 16.309 ;
     RECT  6.144 15.827 17.496 16.309 ;
     RECT  37.584 16.019 38.136 16.355 ;
     RECT  38.016 16.355 38.136 16.595 ;
     RECT  36.528 16.019 36.552 17.029 ;
     RECT  2.304 16.309 17.496 17.123 ;
     RECT  36.432 17.029 36.552 17.605 ;
     RECT  38.064 16.595 38.136 17.605 ;
     RECT  39.216 16.019 40.512 17.605 ;
     RECT  2.4 17.123 17.496 17.747 ;
     RECT  20.112 16.019 31.896 17.747 ;
     RECT  18.6 15.539 18.912 17.989 ;
     RECT  20.112 17.747 31.56 17.989 ;
     RECT  34.8 15.875 35.448 18.131 ;
     RECT  36.432 17.605 40.512 18.419 ;
     RECT  36.432 18.419 38.136 18.659 ;
     RECT  5.664 17.747 17.496 18.851 ;
     RECT  18.6 17.989 31.56 18.851 ;
     RECT  7.632 18.851 17.496 18.899 ;
     RECT  36.432 18.659 36.552 19.043 ;
     RECT  36.528 19.043 36.552 19.091 ;
     RECT  18.6 18.851 19.704 19.285 ;
     RECT  6.48 18.851 6.504 19.427 ;
     RECT  20.976 18.851 31.56 19.427 ;
     RECT  17.664 19.285 19.704 19.475 ;
     RECT  38.064 18.659 38.136 19.621 ;
     RECT  39.216 18.419 40.512 19.621 ;
     RECT  7.632 18.899 16.584 19.763 ;
     RECT  38.064 19.621 40.512 19.909 ;
     RECT  37.632 19.909 40.512 20.291 ;
     RECT  33.6 19.093 33.624 20.485 ;
     RECT  34.8 18.131 35.112 20.485 ;
     RECT  21.072 19.427 31.56 20.627 ;
     RECT  21.792 20.627 31.56 20.867 ;
     RECT  7.8 19.763 16.584 21.013 ;
     RECT  17.664 19.475 18.912 21.013 ;
     RECT  2.4 17.747 3.816 21.155 ;
     RECT  21.792 20.867 31.08 21.155 ;
     RECT  33.6 20.485 35.112 21.155 ;
     RECT  34.416 21.155 35.112 21.203 ;
     RECT  21.792 21.155 30.6 22.165 ;
     RECT  37.632 20.291 38.136 22.165 ;
     RECT  7.8 21.013 18.912 22.259 ;
     RECT  37.2 22.165 38.136 22.741 ;
     RECT  39.216 20.291 40.512 22.741 ;
     RECT  21.792 22.165 31.896 22.835 ;
     RECT  21.792 22.835 30.6 23.315 ;
     RECT  7.8 22.259 9.384 23.317 ;
     RECT  10.416 22.259 18.912 23.317 ;
     RECT  37.2 22.741 40.512 23.317 ;
     RECT  21.792 23.315 29.88 23.411 ;
     RECT  36.48 23.317 40.512 23.555 ;
     RECT  31.728 22.835 31.752 23.893 ;
     RECT  36.48 23.555 38.136 23.939 ;
     RECT  7.8 23.317 18.912 23.987 ;
     RECT  37.2 23.939 38.136 24.275 ;
     RECT  7.8 23.987 16.968 24.323 ;
     RECT  18.048 23.987 18.912 24.659 ;
     RECT  21.792 23.411 29.712 24.805 ;
     RECT  18.48 24.659 18.912 24.947 ;
     RECT  37.488 24.275 38.136 25.187 ;
     RECT  21.792 24.805 30.456 25.285 ;
     RECT  31.728 23.893 32.424 25.285 ;
     RECT  21.792 25.285 32.424 25.333 ;
     RECT  2.4 21.155 3.768 25.621 ;
     RECT  19.968 25.045 20.232 25.621 ;
     RECT  7.8 24.323 16.92 25.669 ;
     RECT  7.44 25.669 16.92 25.715 ;
     RECT  19.968 25.621 20.52 25.717 ;
     RECT  21.792 25.333 33.288 25.717 ;
     RECT  7.44 25.715 14.664 26.003 ;
     RECT  7.44 26.003 14.568 26.051 ;
     RECT  19.968 25.717 33.288 26.243 ;
     RECT  39.168 23.555 40.512 26.291 ;
     RECT  15.936 25.715 16.92 26.437 ;
     RECT  34.8 21.203 35.112 26.677 ;
     RECT  20.208 26.243 33.288 26.819 ;
     RECT  2.4 25.621 4.056 27.205 ;
     RECT  15.936 26.437 17.496 27.301 ;
     RECT  18.6 24.947 18.912 27.301 ;
     RECT  7.44 26.051 13.512 27.395 ;
     RECT  21.6 26.819 33.288 27.395 ;
     RECT  2.4 27.205 4.152 27.541 ;
     RECT  2.4 27.541 4.248 27.683 ;
     RECT  24 27.395 33.288 27.875 ;
     RECT  37.632 25.187 38.136 27.875 ;
     RECT  0.192 27.637 0.216 28.067 ;
     RECT  14.544 26.051 14.568 28.117 ;
     RECT  15.936 27.301 19.08 28.117 ;
     RECT  14.544 28.117 19.08 28.211 ;
     RECT  21.6 27.395 22.968 28.259 ;
     RECT  5.616 27.781 5.64 28.405 ;
     RECT  20.208 26.819 20.232 28.451 ;
     RECT  14.544 28.211 18.912 28.499 ;
     RECT  22.944 28.259 22.968 28.595 ;
     RECT  14.544 28.499 17.496 28.691 ;
     RECT  34.656 26.677 35.112 28.741 ;
     RECT  7.8 27.395 13.512 28.933 ;
     RECT  14.544 28.691 17.256 28.933 ;
     RECT  34.656 28.741 35.208 28.981 ;
     RECT  36.48 28.453 36.504 28.981 ;
     RECT  7.392 28.933 17.256 29.027 ;
     RECT  2.4 27.683 4.152 29.029 ;
     RECT  5.616 28.405 6.264 29.029 ;
     RECT  24 27.875 31.896 29.123 ;
     RECT  39.312 26.291 40.512 29.171 ;
     RECT  2.4 29.029 6.264 29.221 ;
     RECT  7.392 29.027 8.856 29.221 ;
     RECT  21.6 28.259 21.816 29.365 ;
     RECT  21.072 29.365 21.816 29.605 ;
     RECT  24 29.123 26.952 29.605 ;
     RECT  10.224 29.027 17.256 29.795 ;
     RECT  39.36 29.171 40.512 29.795 ;
     RECT  12.048 29.795 17.256 29.843 ;
     RECT  34.656 28.981 36.504 30.035 ;
     RECT  2.4 29.221 8.856 30.181 ;
     RECT  28.128 29.123 31.896 30.181 ;
     RECT  16.752 29.843 17.256 30.275 ;
     RECT  20.4 29.605 21.816 30.275 ;
     RECT  23.616 29.605 26.952 30.419 ;
     RECT  28.128 30.181 32.28 30.419 ;
     RECT  28.128 30.419 31.272 30.421 ;
     RECT  12.048 29.843 15.624 30.611 ;
     RECT  18.6 28.499 18.912 30.661 ;
     RECT  21.696 30.275 21.816 30.661 ;
     RECT  23.616 30.419 24.408 30.661 ;
     RECT  10.224 29.795 11.064 30.709 ;
     RECT  25.872 30.419 26.952 30.709 ;
     RECT  27.984 30.421 31.272 30.709 ;
     RECT  37.728 27.875 38.136 30.709 ;
     RECT  13.2 30.611 15.624 30.803 ;
     RECT  21.696 30.661 24.408 30.803 ;
     RECT  36.48 30.035 36.504 30.805 ;
     RECT  37.632 30.709 38.136 30.805 ;
     RECT  2.4 30.181 9.096 30.851 ;
     RECT  36.48 30.805 38.136 30.851 ;
     RECT  34.656 30.035 35.112 30.853 ;
     RECT  6.48 30.851 8.52 30.995 ;
     RECT  2.4 30.851 5.112 31.043 ;
     RECT  21.696 30.803 21.96 31.139 ;
     RECT  20.4 30.275 20.424 31.285 ;
     RECT  34.512 30.853 35.112 31.285 ;
     RECT  2.4 31.043 4.008 31.379 ;
     RECT  10.128 30.709 11.064 31.379 ;
     RECT  16.752 30.275 17.064 31.379 ;
     RECT  12.048 30.611 12.072 31.427 ;
     RECT  16.752 31.379 16.824 31.427 ;
     RECT  23.616 30.803 24.408 31.523 ;
     RECT  25.872 30.709 31.272 31.525 ;
     RECT  40.032 29.795 40.512 31.669 ;
     RECT  0.192 30.805 0.216 31.765 ;
     RECT  18.48 30.661 18.912 31.813 ;
     RECT  20.304 31.285 20.424 31.813 ;
     RECT  39.936 31.669 40.512 31.813 ;
     RECT  4.992 31.043 5.112 31.861 ;
     RECT  6.48 30.995 6.744 31.861 ;
     RECT  7.8 30.995 8.52 31.861 ;
     RECT  25.44 31.525 31.272 31.955 ;
     RECT  21.792 31.139 21.96 32.195 ;
     RECT  0.192 31.765 0.264 32.197 ;
     RECT  4.992 31.861 6.744 32.293 ;
     RECT  7.8 31.861 8.856 32.293 ;
     RECT  0.192 32.197 0.504 32.339 ;
     RECT  14.544 30.803 15.624 32.341 ;
     RECT  16.752 31.427 16.776 32.341 ;
     RECT  18.48 31.813 20.424 32.341 ;
     RECT  11.52 32.341 11.544 32.389 ;
     RECT  33.264 27.875 33.288 32.485 ;
     RECT  34.416 31.285 35.112 32.485 ;
     RECT  25.44 31.955 26.088 32.531 ;
     RECT  33.264 32.485 35.112 32.531 ;
     RECT  37.008 30.851 38.136 32.531 ;
     RECT  0.24 32.339 0.504 32.579 ;
     RECT  10.128 31.379 10.248 32.771 ;
     RECT  11.424 32.389 11.544 32.917 ;
     RECT  13.2 30.803 13.512 33.013 ;
     RECT  14.544 32.341 16.776 33.013 ;
     RECT  18 32.341 20.424 33.013 ;
     RECT  27.072 31.955 31.272 33.013 ;
     RECT  32.256 30.419 32.28 33.013 ;
     RECT  33.264 32.531 33.48 33.013 ;
     RECT  39.312 31.813 40.512 33.107 ;
     RECT  0.288 32.579 0.504 33.203 ;
     RECT  0.384 33.203 0.504 33.251 ;
     RECT  4.992 32.293 8.856 33.251 ;
     RECT  27.072 33.013 33.48 33.347 ;
     RECT  34.56 32.531 35.112 33.349 ;
     RECT  0.48 33.251 0.504 33.395 ;
     RECT  2.4 31.379 3.912 33.445 ;
     RECT  23.616 31.523 24.312 33.445 ;
     RECT  2.4 33.445 3.96 33.541 ;
     RECT  4.992 33.251 8.112 33.541 ;
     RECT  25.44 32.531 25.8 33.541 ;
     RECT  23.616 33.445 24.456 33.589 ;
     RECT  25.44 33.541 25.944 33.589 ;
     RECT  2.4 33.541 8.112 33.683 ;
     RECT  34.56 33.349 35.208 33.779 ;
     RECT  21.792 32.195 21.816 33.925 ;
     RECT  13.2 33.013 16.776 33.973 ;
     RECT  17.904 33.013 20.424 33.973 ;
     RECT  10.176 32.771 10.248 34.021 ;
     RECT  10.128 34.021 10.248 34.067 ;
     RECT  23.616 33.589 25.944 34.067 ;
     RECT  37.008 32.531 37.656 34.069 ;
     RECT  39.936 33.107 40.512 34.069 ;
     RECT  2.4 33.683 6.264 34.259 ;
     RECT  27.072 33.347 33.288 34.259 ;
     RECT  11.424 32.917 11.976 34.307 ;
     RECT  7.344 33.683 8.112 34.501 ;
     RECT  13.2 33.973 20.424 34.501 ;
     RECT  21.696 33.925 21.816 34.501 ;
     RECT  24 34.067 25.944 34.741 ;
     RECT  27.072 34.259 29.712 34.741 ;
     RECT  31.104 34.259 33.288 34.741 ;
     RECT  34.8 33.779 35.208 34.741 ;
     RECT  2.4 34.259 6.12 34.835 ;
     RECT  7.344 34.501 9.096 34.835 ;
     RECT  37.008 34.069 40.512 34.835 ;
     RECT  24 34.741 29.712 34.883 ;
     RECT  13.2 34.501 21.816 35.173 ;
     RECT  11.424 34.307 11.928 35.317 ;
     RECT  13.104 35.173 21.816 35.317 ;
     RECT  11.424 35.317 21.816 35.363 ;
     RECT  7.392 34.835 9.096 35.461 ;
     RECT  10.128 34.067 10.152 35.461 ;
     RECT  7.392 35.461 10.152 35.507 ;
     RECT  25.536 34.883 29.712 35.557 ;
     RECT  31.104 34.741 35.208 35.557 ;
     RECT  11.424 35.363 20.808 35.749 ;
     RECT  24 34.883 24.504 35.845 ;
     RECT  25.536 35.557 35.736 35.845 ;
     RECT  2.4 34.835 6.072 35.939 ;
     RECT  38.88 34.835 40.512 35.939 ;
     RECT  7.392 35.507 8.112 36.229 ;
     RECT  9.504 35.507 10.152 36.275 ;
     RECT  21.792 35.363 21.816 36.517 ;
     RECT  37.008 34.835 37.656 36.659 ;
     RECT  10.128 36.275 10.152 36.755 ;
     RECT  24 35.845 35.736 36.995 ;
     RECT  11.184 35.749 20.808 37.475 ;
     RECT  21.792 36.517 22.776 37.475 ;
     RECT  2.4 35.939 5.688 37.573 ;
     RECT  6.672 36.229 8.112 37.573 ;
     RECT  2.4 37.573 8.112 37.619 ;
     RECT  5.664 37.619 8.112 37.667 ;
     RECT  37.008 36.659 37.032 37.813 ;
     RECT  36.576 37.813 37.032 37.859 ;
     RECT  24 36.995 35.112 38.005 ;
     RECT  11.424 37.475 20.808 38.099 ;
     RECT  11.76 38.099 20.808 38.725 ;
     RECT  21.792 37.475 21.816 38.725 ;
     RECT  24 38.005 35.592 38.725 ;
     RECT  36.576 37.859 36.6 38.725 ;
     RECT  39.024 35.939 40.512 38.725 ;
     RECT  24 38.725 36.6 38.965 ;
     RECT  24 38.965 36.648 39.011 ;
     RECT  2.4 37.619 4.104 39.205 ;
     RECT  24 39.011 27.048 39.301 ;
     RECT  23.136 39.301 27.048 39.395 ;
     RECT  38.112 38.725 40.512 39.395 ;
     RECT  36.624 39.011 36.648 39.443 ;
     RECT  11.76 38.725 21.816 39.491 ;
     RECT  23.136 39.395 25.08 39.587 ;
     RECT  23.232 39.587 25.08 39.683 ;
     RECT  39.024 39.395 40.512 39.923 ;
     RECT  6.336 37.667 8.112 40.021 ;
     RECT  12.336 39.491 21.816 40.163 ;
     RECT  28.368 39.011 35.592 40.307 ;
     RECT  2.4 39.205 4.536 40.499 ;
     RECT  24 39.683 25.08 40.645 ;
     RECT  26.16 39.395 27.048 40.645 ;
     RECT  29.136 40.307 35.592 40.645 ;
     RECT  12.336 40.163 20.376 40.739 ;
     RECT  11.328 40.693 11.352 40.789 ;
     RECT  12.336 40.739 16.776 40.789 ;
     RECT  24 40.645 27.048 40.933 ;
     RECT  11.328 40.789 16.776 41.075 ;
     RECT  23.808 40.933 27.048 41.075 ;
     RECT  29.136 40.645 35.832 41.075 ;
     RECT  21.792 40.163 21.816 41.173 ;
     RECT  21.792 41.173 22.152 41.269 ;
     RECT  29.136 41.075 35.592 41.507 ;
     RECT  17.808 40.739 20.376 41.509 ;
     RECT  21.456 41.269 22.152 41.509 ;
     RECT  17.808 41.509 22.152 41.605 ;
     RECT  6.336 40.021 8.328 41.651 ;
     RECT  11.328 41.075 16.728 41.797 ;
     RECT  23.904 41.075 27.048 41.939 ;
     RECT  17.808 41.605 22.824 42.133 ;
     RECT  23.904 41.939 26.568 42.133 ;
     RECT  29.184 41.507 35.592 42.133 ;
     RECT  29.184 42.133 36.072 42.323 ;
     RECT  10.032 42.037 10.056 42.565 ;
     RECT  31.008 42.323 36.072 42.611 ;
     RECT  39.168 39.923 40.512 42.613 ;
     RECT  2.4 40.499 4.104 42.709 ;
     RECT  9.84 42.565 10.056 42.709 ;
     RECT  11.232 41.797 16.728 42.709 ;
     RECT  37.824 42.613 37.848 43.283 ;
     RECT  31.008 42.611 31.08 43.331 ;
     RECT  39.024 42.613 40.512 43.525 ;
     RECT  9.84 42.709 16.728 43.717 ;
     RECT  17.808 42.133 26.568 43.717 ;
     RECT  6.336 41.651 8.232 43.765 ;
     RECT  6.336 43.765 8.856 43.861 ;
     RECT  9.84 43.717 26.568 43.861 ;
     RECT  38.976 43.525 40.512 43.861 ;
     RECT  6.336 43.861 26.568 44.245 ;
     RECT  38.448 43.861 40.512 44.341 ;
     RECT  31.056 43.331 31.08 44.437 ;
     RECT  32.4 42.611 36.072 44.437 ;
     RECT  27.696 43.093 27.72 44.483 ;
     RECT  2.4 42.709 4.392 44.627 ;
     RECT  6.288 44.245 26.568 44.965 ;
     RECT  2.4 44.627 4.104 45.059 ;
     RECT  5.664 44.965 26.568 45.541 ;
     RECT  29.184 42.323 29.712 45.541 ;
     RECT  31.056 44.437 36.072 45.541 ;
     RECT  29.136 45.541 36.072 45.731 ;
     RECT  37.056 45.109 37.08 45.779 ;
     RECT  29.136 45.731 35.208 46.547 ;
     RECT  5.664 45.541 27.336 46.787 ;
     RECT  29.136 46.547 35.112 46.837 ;
     RECT  5.904 46.787 27.336 46.931 ;
     RECT  29.088 46.837 35.112 46.979 ;
     RECT  38.448 44.341 40.632 47.269 ;
     RECT  29.184 46.979 35.112 47.699 ;
     RECT  7.584 46.931 27.336 47.845 ;
     RECT  29.184 47.699 31.08 47.939 ;
     RECT  38.208 47.269 40.632 47.939 ;
     RECT  5.904 46.931 6.552 48.085 ;
     RECT  32.448 47.699 35.112 48.179 ;
     RECT  7.584 47.845 28.104 48.421 ;
     RECT  29.184 47.939 30.36 48.421 ;
     RECT  7.584 48.421 30.36 48.469 ;
     RECT  7.536 48.469 30.36 48.659 ;
     RECT  28.944 48.659 30.36 48.803 ;
     RECT  5.136 48.085 6.552 48.899 ;
     RECT  32.496 48.179 35.112 48.995 ;
     RECT  5.328 48.899 6.552 48.997 ;
     RECT  7.536 48.659 27.912 48.997 ;
     RECT  36.768 47.653 36.792 48.997 ;
     RECT  5.328 48.997 27.912 49.139 ;
     RECT  36.528 48.997 36.792 49.525 ;
     RECT  7.584 49.139 27.912 49.619 ;
     RECT  39.024 47.939 40.512 49.619 ;
     RECT  29.4 48.803 30.36 49.907 ;
     RECT  29.4 49.907 29.712 49.909 ;
     RECT  34.8 48.995 35.112 49.909 ;
     RECT  36.528 49.525 36.84 49.909 ;
     RECT  34.8 49.909 36.84 50.005 ;
     RECT  2.4 45.059 3.96 50.101 ;
     RECT  32.496 48.995 33.72 50.101 ;
     RECT  39.216 49.619 40.512 50.195 ;
     RECT  7.632 49.619 27.912 50.293 ;
     RECT  29.28 49.909 29.712 50.293 ;
     RECT  34.8 50.005 37.032 50.389 ;
     RECT  34.8 50.389 37.128 50.677 ;
     RECT  39.696 50.195 40.512 50.771 ;
     RECT  2.4 50.101 4.008 50.819 ;
     RECT  32.112 50.101 33.72 50.819 ;
     RECT  32.112 50.819 32.52 50.867 ;
     RECT  7.632 50.293 29.712 51.107 ;
     RECT  5.328 49.139 6.6 51.205 ;
     RECT  7.632 51.107 27.384 51.205 ;
     RECT  34.8 50.677 37.992 51.395 ;
     RECT  32.496 50.867 32.52 51.635 ;
     RECT  28.512 51.107 29.712 51.779 ;
     RECT  34.8 51.395 36.456 51.829 ;
     RECT  2.4 50.819 3.96 51.923 ;
     RECT  33.552 50.819 33.72 51.923 ;
     RECT  5.328 51.205 27.384 52.115 ;
     RECT  34.704 51.829 36.456 52.357 ;
     RECT  37.968 51.395 37.992 52.357 ;
     RECT  5.328 52.115 5.352 52.595 ;
     RECT  33.696 51.923 33.72 52.885 ;
     RECT  34.704 52.357 37.992 52.885 ;
     RECT  6.48 52.115 27.384 52.979 ;
     RECT  6.48 52.979 8.112 53.027 ;
     RECT  6.576 53.027 8.112 53.075 ;
     RECT  9.408 52.979 27.384 53.075 ;
     RECT  33.696 52.885 37.992 53.075 ;
     RECT  37.968 53.075 37.992 53.219 ;
     RECT  34.032 53.075 36.456 53.411 ;
     RECT  27.36 53.075 27.384 53.555 ;
     RECT  6.576 53.075 6.6 53.603 ;
     RECT  9.408 53.075 25.8 53.603 ;
     RECT  34.8 53.411 36.456 53.603 ;
     RECT  9.408 53.603 14.136 53.651 ;
     RECT  7.632 53.075 8.112 53.795 ;
     RECT  15.504 53.603 25.128 53.843 ;
     RECT  2.4 51.923 2.712 54.009 ;
     RECT  7.8 53.795 8.112 54.009 ;
     RECT  29.4 51.779 29.712 54.009 ;
     RECT  34.8 53.603 35.112 54.009 ;
     RECT  40.2 50.771 40.512 54.009 ;
     RECT  2.4 54.009 2.52 54.023 ;
     RECT  7.8 54.009 7.92 54.023 ;
     RECT  29.4 54.009 29.52 54.023 ;
     RECT  34.8 54.009 34.92 54.023 ;
     RECT  40.2 54.009 40.32 54.023 ;
     RECT  9.408 53.651 13.656 54.179 ;
     RECT  15.504 53.843 24.696 54.227 ;
     RECT  9.408 54.179 13.608 54.709 ;
     RECT  9.168 54.709 13.608 55.285 ;
     RECT  9.024 55.285 13.608 55.331 ;
     RECT  9.024 55.331 13.512 56.016 ;
     RECT  15.504 54.227 24.6 56.016 ;
     RECT  7.92 2.137 8.928 2.149 ;
     RECT  29.712 2.197 30.864 2.245 ;
     RECT  27.768 2.533 29.232 2.677 ;
     RECT  33.624 2.725 34.8 2.773 ;
     RECT  33.048 5.747 34.128 5.843 ;
     RECT  33.384 7.765 34.8 11.315 ;
     RECT  5.304 8.197 6.816 8.435 ;
     RECT  35.112 8.291 35.352 9.589 ;
     RECT  35.112 9.589 36.144 10.741 ;
     RECT  38.76 9.925 40.2 10.067 ;
     RECT  36.168 10.021 37.344 10.883 ;
     RECT  36.168 10.883 38.064 12.373 ;
     RECT  35.112 11.171 36.144 13.715 ;
     RECT  33.288 11.315 34.8 12.901 ;
     RECT  38.136 11.941 39.216 12.517 ;
     RECT  36.168 12.373 37.584 13.715 ;
     RECT  4.968 12.611 6.144 16.309 ;
     RECT  2.304 13.427 2.4 14.725 ;
     RECT  32.856 13.715 34.224 14.291 ;
     RECT  35.112 13.715 37.584 14.629 ;
     RECT  21.432 14.339 22.416 14.387 ;
     RECT  21.432 14.387 22.608 15.733 ;
     RECT  35.112 14.629 36.528 15.397 ;
     RECT  36.552 14.629 37.584 14.773 ;
     RECT  18.912 14.675 19.968 15.971 ;
     RECT  17.544 15.539 18.6 15.827 ;
     RECT  17.496 15.827 18.6 18.899 ;
     RECT  35.448 15.875 36.528 17.029 ;
     RECT  18.912 15.971 20.112 17.989 ;
     RECT  36.552 16.019 37.584 16.355 ;
     RECT  38.136 16.019 39.216 17.605 ;
     RECT  36.552 16.355 38.016 16.595 ;
     RECT  36.552 16.595 38.064 17.605 ;
     RECT  35.448 17.029 36.432 18.131 ;
     RECT  35.112 18.131 36.432 19.043 ;
     RECT  38.136 18.419 39.216 19.621 ;
     RECT  36.552 18.659 38.064 19.091 ;
     RECT  6.504 18.851 7.632 19.427 ;
     RECT  19.704 18.851 20.976 19.427 ;
     RECT  16.584 18.899 18.6 19.285 ;
     RECT  35.112 19.043 36.528 19.091 ;
     RECT  37.632 19.091 38.064 19.909 ;
     RECT  33.624 19.093 34.8 20.485 ;
     RECT  16.584 19.285 17.664 21.013 ;
     RECT  19.704 19.427 21.072 19.475 ;
     RECT  38.136 20.291 39.216 22.741 ;
     RECT  31.08 20.867 31.56 21.155 ;
     RECT  30.6 21.155 31.56 22.165 ;
     RECT  9.384 22.259 10.416 23.317 ;
     RECT  30.6 22.835 31.728 23.315 ;
     RECT  31.752 22.835 31.896 23.893 ;
     RECT  29.88 23.315 31.728 23.411 ;
     RECT  35.112 23.317 36.48 23.939 ;
     RECT  29.712 23.411 31.728 24.805 ;
     RECT  38.136 23.555 39.168 26.291 ;
     RECT  16.968 23.987 18.048 24.323 ;
     RECT  16.92 24.323 18.048 24.659 ;
     RECT  30.456 24.805 31.728 25.285 ;
     RECT  18.48 24.947 18.6 26.437 ;
     RECT  18.912 25.045 19.968 26.243 ;
     RECT  33.288 25.333 34.8 26.677 ;
     RECT  20.52 25.621 21.792 25.717 ;
     RECT  14.664 25.715 15.936 26.003 ;
     RECT  14.568 26.003 15.936 28.117 ;
     RECT  13.512 26.051 14.544 28.933 ;
     RECT  18.912 26.243 20.208 27.301 ;
     RECT  38.136 26.291 39.312 29.171 ;
     RECT  17.496 26.437 18.6 27.301 ;
     RECT  33.288 26.677 34.656 30.853 ;
     RECT  20.232 26.819 21.6 28.451 ;
     RECT  19.08 27.301 20.208 28.211 ;
     RECT  22.968 27.395 24 28.595 ;
     RECT  4.152 27.683 4.248 27.781 ;
     RECT  4.152 27.781 5.616 29.029 ;
     RECT  31.896 27.875 33.264 30.181 ;
     RECT  37.632 27.875 37.728 28.453 ;
     RECT  18.912 28.211 20.208 28.451 ;
     RECT  21.816 28.259 22.944 28.595 ;
     RECT  18.912 28.451 21.6 29.365 ;
     RECT  35.112 28.453 36.48 28.741 ;
     RECT  36.504 28.453 37.728 30.709 ;
     RECT  17.496 28.499 18.6 28.691 ;
     RECT  23.616 28.595 24 29.605 ;
     RECT  17.256 28.691 18.6 30.275 ;
     RECT  35.208 28.741 36.48 28.981 ;
     RECT  6.264 28.933 7.392 29.221 ;
     RECT  8.856 29.027 10.224 30.181 ;
     RECT  26.952 29.123 28.128 30.421 ;
     RECT  38.136 29.171 39.36 29.795 ;
     RECT  18.912 29.365 21.072 29.605 ;
     RECT  18.912 29.605 20.4 31.285 ;
     RECT  11.064 29.795 12.048 31.379 ;
     RECT  15.624 29.843 16.752 32.341 ;
     RECT  35.112 30.035 36.48 30.851 ;
     RECT  9.096 30.181 10.224 30.709 ;
     RECT  32.28 30.181 33.264 33.013 ;
     RECT  17.064 30.275 18.6 30.661 ;
     RECT  20.424 30.275 21.696 31.139 ;
     RECT  24.408 30.419 25.872 31.523 ;
     RECT  31.272 30.419 32.256 33.013 ;
     RECT  26.952 30.421 27.984 30.709 ;
     RECT  12.072 30.611 13.2 31.427 ;
     RECT  17.064 30.661 18.48 31.379 ;
     RECT  9.096 30.709 10.128 30.851 ;
     RECT  36.504 30.709 37.632 30.805 ;
     RECT  13.512 30.803 14.544 33.013 ;
     RECT  5.112 30.851 6.48 31.861 ;
     RECT  8.52 30.851 10.128 31.861 ;
     RECT  33.288 30.853 34.512 31.285 ;
     RECT  6.744 30.995 7.8 32.293 ;
     RECT  4.008 31.043 4.992 31.379 ;
     RECT  20.424 31.139 21.792 33.925 ;
     RECT  18.912 31.285 20.304 31.813 ;
     RECT  33.288 31.285 34.416 32.485 ;
     RECT  3.912 31.379 4.992 33.445 ;
     RECT  10.248 31.379 12.048 31.427 ;
     RECT  16.824 31.379 18.48 31.427 ;
     RECT  10.248 31.427 13.2 32.341 ;
     RECT  16.776 31.427 18.48 32.341 ;
     RECT  24.312 31.523 25.872 31.525 ;
     RECT  24.312 31.525 25.44 33.445 ;
     RECT  38.136 31.813 39.312 32.531 ;
     RECT  8.856 31.861 10.128 32.771 ;
     RECT  26.088 31.955 27.072 32.531 ;
     RECT  10.248 32.341 11.52 32.389 ;
     RECT  11.544 32.341 13.2 32.917 ;
     RECT  16.776 32.341 18 33.013 ;
     RECT  10.248 32.389 11.424 34.067 ;
     RECT  25.8 32.531 27.072 33.541 ;
     RECT  33.48 32.531 34.56 33.347 ;
     RECT  8.856 32.771 10.176 33.251 ;
     RECT  11.976 32.917 13.2 34.307 ;
     RECT  16.776 33.013 17.904 33.973 ;
     RECT  39.312 33.107 39.936 34.069 ;
     RECT  8.112 33.251 10.176 34.021 ;
     RECT  33.288 33.347 34.56 33.779 ;
     RECT  3.96 33.445 4.992 33.541 ;
     RECT  24.456 33.445 25.44 33.589 ;
     RECT  25.944 33.541 27.072 34.741 ;
     RECT  6.264 33.683 7.344 34.259 ;
     RECT  33.288 33.779 34.8 34.741 ;
     RECT  20.424 33.925 21.696 34.501 ;
     RECT  8.112 34.021 10.128 34.501 ;
     RECT  10.152 34.067 11.424 35.749 ;
     RECT  6.12 34.259 7.344 34.835 ;
     RECT  29.712 34.259 31.104 35.557 ;
     RECT  11.928 34.307 13.2 35.173 ;
     RECT  9.096 34.501 10.128 35.461 ;
     RECT  6.072 34.835 7.392 35.939 ;
     RECT  37.656 34.835 38.88 35.939 ;
     RECT  24.504 34.883 25.536 35.845 ;
     RECT  11.928 35.173 13.104 35.317 ;
     RECT  20.808 35.363 21.792 38.725 ;
     RECT  8.112 35.507 9.504 36.275 ;
     RECT  35.736 35.557 37.008 36.995 ;
     RECT  10.152 35.749 11.184 36.755 ;
     RECT  5.688 35.939 7.392 36.229 ;
     RECT  37.656 35.939 39.024 36.659 ;
     RECT  5.688 36.229 6.672 37.573 ;
     RECT  22.776 36.517 24 37.475 ;
     RECT  35.112 36.995 37.008 37.813 ;
     RECT  35.112 37.813 36.576 38.005 ;
     RECT  36.6 37.859 37.032 38.725 ;
     RECT  35.592 38.005 36.576 38.725 ;
     RECT  36.6 38.725 38.112 38.965 ;
     RECT  36.648 38.965 38.112 39.395 ;
     RECT  27.048 39.011 28.368 40.307 ;
     RECT  35.592 39.011 36.624 39.443 ;
     RECT  21.816 39.301 23.136 39.587 ;
     RECT  25.08 39.395 26.16 40.645 ;
     RECT  35.592 39.443 35.832 40.645 ;
     RECT  11.76 39.491 12.336 40.693 ;
     RECT  21.816 39.587 23.232 39.683 ;
     RECT  21.816 39.683 22.152 41.173 ;
     RECT  23.808 39.683 24 40.933 ;
     RECT  20.376 40.163 21.792 41.269 ;
     RECT  11.352 40.693 12.336 40.789 ;
     RECT  16.776 40.739 17.808 41.075 ;
     RECT  16.728 41.075 17.808 43.717 ;
     RECT  23.808 41.075 23.904 41.605 ;
     RECT  35.592 41.075 35.832 42.133 ;
     RECT  20.376 41.269 21.456 41.509 ;
     RECT  22.824 41.605 23.904 42.133 ;
     RECT  26.568 41.939 27.048 43.093 ;
     RECT  10.056 42.037 11.232 42.709 ;
     RECT  29.712 42.323 31.008 43.331 ;
     RECT  31.08 42.611 32.4 44.437 ;
     RECT  37.848 42.613 39.024 43.283 ;
     RECT  26.568 43.093 27.696 44.483 ;
     RECT  27.72 43.093 29.184 44.483 ;
     RECT  38.448 43.283 39.024 43.525 ;
     RECT  29.712 43.331 31.056 45.541 ;
     RECT  38.448 43.525 38.976 43.861 ;
     RECT  8.856 43.765 9.84 43.861 ;
     RECT  26.568 44.483 27.336 45.541 ;
     RECT  29.136 44.483 29.184 45.541 ;
     RECT  36.072 45.109 37.056 45.731 ;
     RECT  37.08 45.109 38.448 45.779 ;
     RECT  38.208 45.779 38.448 47.269 ;
     RECT  5.664 46.787 5.904 48.085 ;
     RECT  6.552 46.931 7.584 48.469 ;
     RECT  29.088 46.979 29.184 47.845 ;
     RECT  36.792 47.653 38.208 47.939 ;
     RECT  31.08 47.699 32.448 47.939 ;
     RECT  28.104 47.845 29.184 48.421 ;
     RECT  3.96 48.085 5.136 48.899 ;
     RECT  6.552 48.469 7.536 48.997 ;
     RECT  27.912 48.659 28.944 48.803 ;
     RECT  27.912 48.803 29.4 49.909 ;
     RECT  3.96 48.899 5.328 50.101 ;
     RECT  33.72 48.995 34.8 51.829 ;
     RECT  35.112 48.997 36.528 49.909 ;
     RECT  6.6 49.139 7.584 49.619 ;
     RECT  6.6 49.619 7.632 51.205 ;
     RECT  27.912 49.909 29.28 50.293 ;
     RECT  4.008 50.101 5.328 50.819 ;
     RECT  3.96 50.819 5.328 51.923 ;
     RECT  32.52 50.819 33.552 51.635 ;
     RECT  27.384 51.107 28.512 51.779 ;
     RECT  36.456 51.395 37.968 52.357 ;
     RECT  33.72 51.829 34.704 52.885 ;
     RECT  5.352 52.115 6.48 52.595 ;
     RECT  8.112 52.979 9.408 54.009 ;
     RECT  6.6 53.075 7.632 53.603 ;
     RECT  36.456 53.075 37.968 53.219 ;
     RECT  14.136 53.603 15.504 53.651 ;
     RECT  7.92 54.009 9.408 54.023 ;
     RECT  9.024 54.023 9.408 54.709 ;
     RECT  9.024 54.709 9.168 55.285 ;
  END
END ot_s81_pq_aq_math_native
END LIBRARY
